VERSION 5.8 ;
BUSBITCHARS "[]" ;
DIVIDERCHAR "/" ;
UNITS
    DATABASE MICRONS 1000 ;
END UNITS

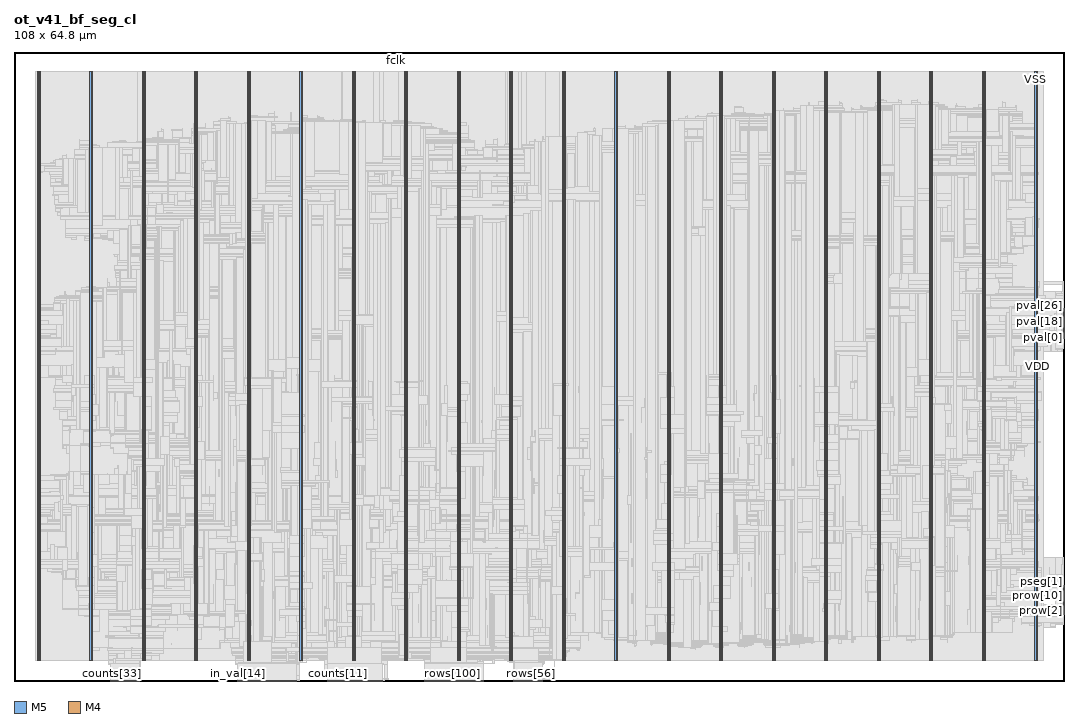
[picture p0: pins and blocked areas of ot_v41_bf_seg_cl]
MACRO ot_v41_bf_seg_cl
  FOREIGN ot_v41_bf_seg_cl 0 0 ;
  CLASS BLOCK ;
  SIZE 108 BY 64.8 ;
  PIN counts[0]
    DIRECTION INPUT ;
    USE SIGNAL ;
    PORT
      LAYER M5 ;
        RECT  32.208 0 32.232 0.084 ;
    END
  END counts[0]
  PIN counts[10]
    DIRECTION INPUT ;
    USE SIGNAL ;
    PORT
      LAYER M5 ;
        RECT  33.168 0 33.192 0.084 ;
    END
  END counts[10]
  PIN counts[11]
    DIRECTION INPUT ;
    USE SIGNAL ;
    PORT
      LAYER M5 ;
        RECT  33.264 0 33.288 0.084 ;
    END
  END counts[11]
  PIN counts[12]
    DIRECTION INPUT ;
    USE SIGNAL ;
    PORT
      LAYER M5 ;
        RECT  33.36 0 33.384 0.084 ;
    END
  END counts[12]
  PIN counts[13]
    DIRECTION INPUT ;
    USE SIGNAL ;
    PORT
      LAYER M5 ;
        RECT  33.456 0 33.48 0.084 ;
    END
  END counts[13]
  PIN counts[14]
    DIRECTION INPUT ;
    USE SIGNAL ;
    PORT
      LAYER M5 ;
        RECT  33.552 0 33.576 0.084 ;
    END
  END counts[14]
  PIN counts[15]
    DIRECTION INPUT ;
    USE SIGNAL ;
    PORT
      LAYER M5 ;
        RECT  33.648 0 33.672 0.084 ;
    END
  END counts[15]
  PIN counts[16]
    DIRECTION INPUT ;
    USE SIGNAL ;
    PORT
      LAYER M5 ;
        RECT  33.744 0 33.768 0.084 ;
    END
  END counts[16]
  PIN counts[17]
    DIRECTION INPUT ;
    USE SIGNAL ;
    PORT
      LAYER M5 ;
        RECT  33.84 0 33.864 0.084 ;
    END
  END counts[17]
  PIN counts[18]
    DIRECTION INPUT ;
    USE SIGNAL ;
    PORT
      LAYER M5 ;
        RECT  33.936 0 33.96 0.084 ;
    END
  END counts[18]
  PIN counts[19]
    DIRECTION INPUT ;
    USE SIGNAL ;
    PORT
      LAYER M5 ;
        RECT  34.032 0 34.056 0.084 ;
    END
  END counts[19]
  PIN counts[1]
    DIRECTION INPUT ;
    USE SIGNAL ;
    PORT
      LAYER M5 ;
        RECT  32.304 0 32.328 0.084 ;
    END
  END counts[1]
  PIN counts[20]
    DIRECTION INPUT ;
    USE SIGNAL ;
    PORT
      LAYER M5 ;
        RECT  34.128 0 34.152 0.084 ;
    END
  END counts[20]
  PIN counts[21]
    DIRECTION INPUT ;
    USE SIGNAL ;
    PORT
      LAYER M5 ;
        RECT  34.224 0 34.248 0.084 ;
    END
  END counts[21]
  PIN counts[22]
    DIRECTION INPUT ;
    USE SIGNAL ;
    PORT
      LAYER M5 ;
        RECT  34.32 0 34.344 0.084 ;
    END
  END counts[22]
  PIN counts[23]
    DIRECTION INPUT ;
    USE SIGNAL ;
    PORT
      LAYER M5 ;
        RECT  34.416 0 34.44 0.084 ;
    END
  END counts[23]
  PIN counts[24]
    DIRECTION INPUT ;
    USE SIGNAL ;
    PORT
      LAYER M5 ;
        RECT  34.512 0 34.536 0.084 ;
    END
  END counts[24]
  PIN counts[25]
    DIRECTION INPUT ;
    USE SIGNAL ;
    PORT
      LAYER M5 ;
        RECT  34.608 0 34.632 0.084 ;
    END
  END counts[25]
  PIN counts[26]
    DIRECTION INPUT ;
    USE SIGNAL ;
    PORT
      LAYER M5 ;
        RECT  34.704 0 34.728 0.084 ;
    END
  END counts[26]
  PIN counts[27]
    DIRECTION INPUT ;
    USE SIGNAL ;
    PORT
      LAYER M5 ;
        RECT  34.8 0 34.824 0.084 ;
    END
  END counts[27]
  PIN counts[28]
    DIRECTION INPUT ;
    USE SIGNAL ;
    PORT
      LAYER M5 ;
        RECT  34.896 0 34.92 0.084 ;
    END
  END counts[28]
  PIN counts[29]
    DIRECTION INPUT ;
    USE SIGNAL ;
    PORT
      LAYER M5 ;
        RECT  34.992 0 35.016 0.084 ;
    END
  END counts[29]
  PIN counts[2]
    DIRECTION INPUT ;
    USE SIGNAL ;
    PORT
      LAYER M5 ;
        RECT  32.4 0 32.424 0.084 ;
    END
  END counts[2]
  PIN counts[30]
    DIRECTION INPUT ;
    USE SIGNAL ;
    PORT
      LAYER M5 ;
        RECT  35.088 0 35.112 0.084 ;
    END
  END counts[30]
  PIN counts[31]
    DIRECTION INPUT ;
    USE SIGNAL ;
    PORT
      LAYER M5 ;
        RECT  35.184 0 35.208 0.084 ;
    END
  END counts[31]
  PIN counts[32]
    DIRECTION INPUT ;
    USE SIGNAL ;
    PORT
      LAYER M5 ;
        RECT  9.936 0 9.96 0.084 ;
    END
  END counts[32]
  PIN counts[33]
    DIRECTION INPUT ;
    USE SIGNAL ;
    PORT
      LAYER M5 ;
        RECT  10.032 0 10.056 0.084 ;
    END
  END counts[33]
  PIN counts[34]
    DIRECTION INPUT ;
    USE SIGNAL ;
    PORT
      LAYER M5 ;
        RECT  10.128 0 10.152 0.084 ;
    END
  END counts[34]
  PIN counts[35]
    DIRECTION INPUT ;
    USE SIGNAL ;
    PORT
      LAYER M5 ;
        RECT  10.224 0 10.248 0.084 ;
    END
  END counts[35]
  PIN counts[36]
    DIRECTION INPUT ;
    USE SIGNAL ;
    PORT
      LAYER M5 ;
        RECT  10.32 0 10.344 0.084 ;
    END
  END counts[36]
  PIN counts[37]
    DIRECTION INPUT ;
    USE SIGNAL ;
    PORT
      LAYER M5 ;
        RECT  10.416 0 10.44 0.084 ;
    END
  END counts[37]
  PIN counts[38]
    DIRECTION INPUT ;
    USE SIGNAL ;
    PORT
      LAYER M5 ;
        RECT  10.512 0 10.536 0.084 ;
    END
  END counts[38]
  PIN counts[39]
    DIRECTION INPUT ;
    USE SIGNAL ;
    PORT
      LAYER M5 ;
        RECT  10.608 0 10.632 0.084 ;
    END
  END counts[39]
  PIN counts[3]
    DIRECTION INPUT ;
    USE SIGNAL ;
    PORT
      LAYER M5 ;
        RECT  32.496 0 32.52 0.084 ;
    END
  END counts[3]
  PIN counts[4]
    DIRECTION INPUT ;
    USE SIGNAL ;
    PORT
      LAYER M5 ;
        RECT  32.592 0 32.616 0.084 ;
    END
  END counts[4]
  PIN counts[5]
    DIRECTION INPUT ;
    USE SIGNAL ;
    PORT
      LAYER M5 ;
        RECT  32.688 0 32.712 0.084 ;
    END
  END counts[5]
  PIN counts[6]
    DIRECTION INPUT ;
    USE SIGNAL ;
    PORT
      LAYER M5 ;
        RECT  32.784 0 32.808 0.084 ;
    END
  END counts[6]
  PIN counts[7]
    DIRECTION INPUT ;
    USE SIGNAL ;
    PORT
      LAYER M5 ;
        RECT  32.88 0 32.904 0.084 ;
    END
  END counts[7]
  PIN counts[8]
    DIRECTION INPUT ;
    USE SIGNAL ;
    PORT
      LAYER M5 ;
        RECT  32.976 0 33 0.084 ;
    END
  END counts[8]
  PIN counts[9]
    DIRECTION INPUT ;
    USE SIGNAL ;
    PORT
      LAYER M5 ;
        RECT  33.072 0 33.096 0.084 ;
    END
  END counts[9]
  PIN fault
    DIRECTION OUTPUT ;
    USE SIGNAL ;
    PORT
      LAYER M4 ;
        RECT  107.916 6.864 108 6.888 ;
    END
  END fault
  PIN fclk
    DIRECTION INPUT ;
    USE SIGNAL ;
    PORT
      LAYER M5 ;
        RECT  39.312 64.716 39.336 64.8 ;
    END
  END fclk
  PIN in_err
    DIRECTION INPUT ;
    USE SIGNAL ;
    PORT
      LAYER M5 ;
        RECT  10.704 0 10.728 0.084 ;
    END
  END in_err
  PIN in_final
    DIRECTION INPUT ;
    USE SIGNAL ;
    PORT
      LAYER M5 ;
        RECT  10.8 0 10.824 0.084 ;
    END
  END in_final
  PIN in_pos[0]
    DIRECTION INPUT ;
    USE SIGNAL ;
    PORT
      LAYER M5 ;
        RECT  10.896 0 10.92 0.084 ;
    END
  END in_pos[0]
  PIN in_pos[1]
    DIRECTION INPUT ;
    USE SIGNAL ;
    PORT
      LAYER M5 ;
        RECT  10.992 0 11.016 0.084 ;
    END
  END in_pos[1]
  PIN in_pos[2]
    DIRECTION INPUT ;
    USE SIGNAL ;
    PORT
      LAYER M5 ;
        RECT  11.088 0 11.112 0.084 ;
    END
  END in_pos[2]
  PIN in_tree[0]
    DIRECTION INPUT ;
    USE SIGNAL ;
    PORT
      LAYER M5 ;
        RECT  11.184 0 11.208 0.084 ;
    END
  END in_tree[0]
  PIN in_tree[1]
    DIRECTION INPUT ;
    USE SIGNAL ;
    PORT
      LAYER M5 ;
        RECT  11.28 0 11.304 0.084 ;
    END
  END in_tree[1]
  PIN in_tree[2]
    DIRECTION INPUT ;
    USE SIGNAL ;
    PORT
      LAYER M5 ;
        RECT  11.376 0 11.4 0.084 ;
    END
  END in_tree[2]
  PIN in_tree[3]
    DIRECTION INPUT ;
    USE SIGNAL ;
    PORT
      LAYER M5 ;
        RECT  11.472 0 11.496 0.084 ;
    END
  END in_tree[3]
  PIN in_v
    DIRECTION INPUT ;
    USE SIGNAL ;
    PORT
      LAYER M5 ;
        RECT  11.568 0 11.592 0.084 ;
    END
  END in_v
  PIN in_val[0]
    DIRECTION INPUT ;
    USE SIGNAL ;
    PORT
      LAYER M5 ;
        RECT  11.664 0 11.688 0.084 ;
    END
  END in_val[0]
  PIN in_val[10]
    DIRECTION INPUT ;
    USE SIGNAL ;
    PORT
      LAYER M5 ;
        RECT  12.624 0 12.648 0.084 ;
    END
  END in_val[10]
  PIN in_val[11]
    DIRECTION INPUT ;
    USE SIGNAL ;
    PORT
      LAYER M5 ;
        RECT  12.72 0 12.744 0.084 ;
    END
  END in_val[11]
  PIN in_val[12]
    DIRECTION INPUT ;
    USE SIGNAL ;
    PORT
      LAYER M5 ;
        RECT  12.816 0 12.84 0.084 ;
    END
  END in_val[12]
  PIN in_val[13]
    DIRECTION INPUT ;
    USE SIGNAL ;
    PORT
      LAYER M5 ;
        RECT  12.912 0 12.936 0.084 ;
    END
  END in_val[13]
  PIN in_val[14]
    DIRECTION INPUT ;
    USE SIGNAL ;
    PORT
      LAYER M5 ;
        RECT  22.992 0 23.016 0.084 ;
    END
  END in_val[14]
  PIN in_val[15]
    DIRECTION INPUT ;
    USE SIGNAL ;
    PORT
      LAYER M5 ;
        RECT  23.088 0 23.112 0.084 ;
    END
  END in_val[15]
  PIN in_val[16]
    DIRECTION INPUT ;
    USE SIGNAL ;
    PORT
      LAYER M5 ;
        RECT  23.184 0 23.208 0.084 ;
    END
  END in_val[16]
  PIN in_val[17]
    DIRECTION INPUT ;
    USE SIGNAL ;
    PORT
      LAYER M5 ;
        RECT  23.28 0 23.304 0.084 ;
    END
  END in_val[17]
  PIN in_val[18]
    DIRECTION INPUT ;
    USE SIGNAL ;
    PORT
      LAYER M5 ;
        RECT  23.376 0 23.4 0.084 ;
    END
  END in_val[18]
  PIN in_val[19]
    DIRECTION INPUT ;
    USE SIGNAL ;
    PORT
      LAYER M5 ;
        RECT  23.472 0 23.496 0.084 ;
    END
  END in_val[19]
  PIN in_val[1]
    DIRECTION INPUT ;
    USE SIGNAL ;
    PORT
      LAYER M5 ;
        RECT  11.76 0 11.784 0.084 ;
    END
  END in_val[1]
  PIN in_val[20]
    DIRECTION INPUT ;
    USE SIGNAL ;
    PORT
      LAYER M5 ;
        RECT  23.568 0 23.592 0.084 ;
    END
  END in_val[20]
  PIN in_val[21]
    DIRECTION INPUT ;
    USE SIGNAL ;
    PORT
      LAYER M5 ;
        RECT  23.664 0 23.688 0.084 ;
    END
  END in_val[21]
  PIN in_val[22]
    DIRECTION INPUT ;
    USE SIGNAL ;
    PORT
      LAYER M5 ;
        RECT  23.76 0 23.784 0.084 ;
    END
  END in_val[22]
  PIN in_val[23]
    DIRECTION INPUT ;
    USE SIGNAL ;
    PORT
      LAYER M5 ;
        RECT  23.856 0 23.88 0.084 ;
    END
  END in_val[23]
  PIN in_val[24]
    DIRECTION INPUT ;
    USE SIGNAL ;
    PORT
      LAYER M5 ;
        RECT  23.952 0 23.976 0.084 ;
    END
  END in_val[24]
  PIN in_val[25]
    DIRECTION INPUT ;
    USE SIGNAL ;
    PORT
      LAYER M5 ;
        RECT  24.048 0 24.072 0.084 ;
    END
  END in_val[25]
  PIN in_val[26]
    DIRECTION INPUT ;
    USE SIGNAL ;
    PORT
      LAYER M5 ;
        RECT  24.144 0 24.168 0.084 ;
    END
  END in_val[26]
  PIN in_val[27]
    DIRECTION INPUT ;
    USE SIGNAL ;
    PORT
      LAYER M5 ;
        RECT  24.24 0 24.264 0.084 ;
    END
  END in_val[27]
  PIN in_val[28]
    DIRECTION INPUT ;
    USE SIGNAL ;
    PORT
      LAYER M5 ;
        RECT  24.336 0 24.36 0.084 ;
    END
  END in_val[28]
  PIN in_val[29]
    DIRECTION INPUT ;
    USE SIGNAL ;
    PORT
      LAYER M5 ;
        RECT  24.432 0 24.456 0.084 ;
    END
  END in_val[29]
  PIN in_val[2]
    DIRECTION INPUT ;
    USE SIGNAL ;
    PORT
      LAYER M5 ;
        RECT  11.856 0 11.88 0.084 ;
    END
  END in_val[2]
  PIN in_val[30]
    DIRECTION INPUT ;
    USE SIGNAL ;
    PORT
      LAYER M5 ;
        RECT  24.528 0 24.552 0.084 ;
    END
  END in_val[30]
  PIN in_val[31]
    DIRECTION INPUT ;
    USE SIGNAL ;
    PORT
      LAYER M5 ;
        RECT  24.624 0 24.648 0.084 ;
    END
  END in_val[31]
  PIN in_val[3]
    DIRECTION INPUT ;
    USE SIGNAL ;
    PORT
      LAYER M5 ;
        RECT  11.952 0 11.976 0.084 ;
    END
  END in_val[3]
  PIN in_val[4]
    DIRECTION INPUT ;
    USE SIGNAL ;
    PORT
      LAYER M5 ;
        RECT  12.048 0 12.072 0.084 ;
    END
  END in_val[4]
  PIN in_val[5]
    DIRECTION INPUT ;
    USE SIGNAL ;
    PORT
      LAYER M5 ;
        RECT  12.144 0 12.168 0.084 ;
    END
  END in_val[5]
  PIN in_val[6]
    DIRECTION INPUT ;
    USE SIGNAL ;
    PORT
      LAYER M5 ;
        RECT  12.24 0 12.264 0.084 ;
    END
  END in_val[6]
  PIN in_val[7]
    DIRECTION INPUT ;
    USE SIGNAL ;
    PORT
      LAYER M5 ;
        RECT  12.336 0 12.36 0.084 ;
    END
  END in_val[7]
  PIN in_val[8]
    DIRECTION INPUT ;
    USE SIGNAL ;
    PORT
      LAYER M5 ;
        RECT  12.432 0 12.456 0.084 ;
    END
  END in_val[8]
  PIN in_val[9]
    DIRECTION INPUT ;
    USE SIGNAL ;
    PORT
      LAYER M5 ;
        RECT  12.528 0 12.552 0.084 ;
    END
  END in_val[9]
  PIN indices[0]
    DIRECTION INPUT ;
    USE SIGNAL ;
    PORT
      LAYER M5 ;
        RECT  24.72 0 24.744 0.084 ;
    END
  END indices[0]
  PIN indices[10]
    DIRECTION INPUT ;
    USE SIGNAL ;
    PORT
      LAYER M5 ;
        RECT  25.68 0 25.704 0.084 ;
    END
  END indices[10]
  PIN indices[11]
    DIRECTION INPUT ;
    USE SIGNAL ;
    PORT
      LAYER M5 ;
        RECT  25.776 0 25.8 0.084 ;
    END
  END indices[11]
  PIN indices[12]
    DIRECTION INPUT ;
    USE SIGNAL ;
    PORT
      LAYER M5 ;
        RECT  25.872 0 25.896 0.084 ;
    END
  END indices[12]
  PIN indices[13]
    DIRECTION INPUT ;
    USE SIGNAL ;
    PORT
      LAYER M5 ;
        RECT  25.968 0 25.992 0.084 ;
    END
  END indices[13]
  PIN indices[14]
    DIRECTION INPUT ;
    USE SIGNAL ;
    PORT
      LAYER M5 ;
        RECT  26.064 0 26.088 0.084 ;
    END
  END indices[14]
  PIN indices[15]
    DIRECTION INPUT ;
    USE SIGNAL ;
    PORT
      LAYER M5 ;
        RECT  26.16 0 26.184 0.084 ;
    END
  END indices[15]
  PIN indices[16]
    DIRECTION INPUT ;
    USE SIGNAL ;
    PORT
      LAYER M5 ;
        RECT  26.256 0 26.28 0.084 ;
    END
  END indices[16]
  PIN indices[17]
    DIRECTION INPUT ;
    USE SIGNAL ;
    PORT
      LAYER M5 ;
        RECT  26.352 0 26.376 0.084 ;
    END
  END indices[17]
  PIN indices[18]
    DIRECTION INPUT ;
    USE SIGNAL ;
    PORT
      LAYER M5 ;
        RECT  26.448 0 26.472 0.084 ;
    END
  END indices[18]
  PIN indices[19]
    DIRECTION INPUT ;
    USE SIGNAL ;
    PORT
      LAYER M5 ;
        RECT  26.544 0 26.568 0.084 ;
    END
  END indices[19]
  PIN indices[1]
    DIRECTION INPUT ;
    USE SIGNAL ;
    PORT
      LAYER M5 ;
        RECT  24.816 0 24.84 0.084 ;
    END
  END indices[1]
  PIN indices[20]
    DIRECTION INPUT ;
    USE SIGNAL ;
    PORT
      LAYER M5 ;
        RECT  26.64 0 26.664 0.084 ;
    END
  END indices[20]
  PIN indices[21]
    DIRECTION INPUT ;
    USE SIGNAL ;
    PORT
      LAYER M5 ;
        RECT  26.736 0 26.76 0.084 ;
    END
  END indices[21]
  PIN indices[22]
    DIRECTION INPUT ;
    USE SIGNAL ;
    PORT
      LAYER M5 ;
        RECT  26.832 0 26.856 0.084 ;
    END
  END indices[22]
  PIN indices[23]
    DIRECTION INPUT ;
    USE SIGNAL ;
    PORT
      LAYER M5 ;
        RECT  26.928 0 26.952 0.084 ;
    END
  END indices[23]
  PIN indices[24]
    DIRECTION INPUT ;
    USE SIGNAL ;
    PORT
      LAYER M5 ;
        RECT  27.024 0 27.048 0.084 ;
    END
  END indices[24]
  PIN indices[25]
    DIRECTION INPUT ;
    USE SIGNAL ;
    PORT
      LAYER M5 ;
        RECT  27.12 0 27.144 0.084 ;
    END
  END indices[25]
  PIN indices[26]
    DIRECTION INPUT ;
    USE SIGNAL ;
    PORT
      LAYER M5 ;
        RECT  27.216 0 27.24 0.084 ;
    END
  END indices[26]
  PIN indices[27]
    DIRECTION INPUT ;
    USE SIGNAL ;
    PORT
      LAYER M5 ;
        RECT  27.312 0 27.336 0.084 ;
    END
  END indices[27]
  PIN indices[28]
    DIRECTION INPUT ;
    USE SIGNAL ;
    PORT
      LAYER M5 ;
        RECT  27.408 0 27.432 0.084 ;
    END
  END indices[28]
  PIN indices[29]
    DIRECTION INPUT ;
    USE SIGNAL ;
    PORT
      LAYER M5 ;
        RECT  27.504 0 27.528 0.084 ;
    END
  END indices[29]
  PIN indices[2]
    DIRECTION INPUT ;
    USE SIGNAL ;
    PORT
      LAYER M5 ;
        RECT  24.912 0 24.936 0.084 ;
    END
  END indices[2]
  PIN indices[30]
    DIRECTION INPUT ;
    USE SIGNAL ;
    PORT
      LAYER M5 ;
        RECT  27.6 0 27.624 0.084 ;
    END
  END indices[30]
  PIN indices[31]
    DIRECTION INPUT ;
    USE SIGNAL ;
    PORT
      LAYER M5 ;
        RECT  27.696 0 27.72 0.084 ;
    END
  END indices[31]
  PIN indices[32]
    DIRECTION INPUT ;
    USE SIGNAL ;
    PORT
      LAYER M5 ;
        RECT  27.792 0 27.816 0.084 ;
    END
  END indices[32]
  PIN indices[33]
    DIRECTION INPUT ;
    USE SIGNAL ;
    PORT
      LAYER M5 ;
        RECT  27.888 0 27.912 0.084 ;
    END
  END indices[33]
  PIN indices[34]
    DIRECTION INPUT ;
    USE SIGNAL ;
    PORT
      LAYER M5 ;
        RECT  27.984 0 28.008 0.084 ;
    END
  END indices[34]
  PIN indices[35]
    DIRECTION INPUT ;
    USE SIGNAL ;
    PORT
      LAYER M5 ;
        RECT  28.08 0 28.104 0.084 ;
    END
  END indices[35]
  PIN indices[36]
    DIRECTION INPUT ;
    USE SIGNAL ;
    PORT
      LAYER M5 ;
        RECT  28.176 0 28.2 0.084 ;
    END
  END indices[36]
  PIN indices[37]
    DIRECTION INPUT ;
    USE SIGNAL ;
    PORT
      LAYER M5 ;
        RECT  28.272 0 28.296 0.084 ;
    END
  END indices[37]
  PIN indices[38]
    DIRECTION INPUT ;
    USE SIGNAL ;
    PORT
      LAYER M5 ;
        RECT  28.368 0 28.392 0.084 ;
    END
  END indices[38]
  PIN indices[39]
    DIRECTION INPUT ;
    USE SIGNAL ;
    PORT
      LAYER M5 ;
        RECT  28.464 0 28.488 0.084 ;
    END
  END indices[39]
  PIN indices[3]
    DIRECTION INPUT ;
    USE SIGNAL ;
    PORT
      LAYER M5 ;
        RECT  25.008 0 25.032 0.084 ;
    END
  END indices[3]
  PIN indices[4]
    DIRECTION INPUT ;
    USE SIGNAL ;
    PORT
      LAYER M5 ;
        RECT  25.104 0 25.128 0.084 ;
    END
  END indices[4]
  PIN indices[5]
    DIRECTION INPUT ;
    USE SIGNAL ;
    PORT
      LAYER M5 ;
        RECT  25.2 0 25.224 0.084 ;
    END
  END indices[5]
  PIN indices[6]
    DIRECTION INPUT ;
    USE SIGNAL ;
    PORT
      LAYER M5 ;
        RECT  25.296 0 25.32 0.084 ;
    END
  END indices[6]
  PIN indices[7]
    DIRECTION INPUT ;
    USE SIGNAL ;
    PORT
      LAYER M5 ;
        RECT  25.392 0 25.416 0.084 ;
    END
  END indices[7]
  PIN indices[8]
    DIRECTION INPUT ;
    USE SIGNAL ;
    PORT
      LAYER M5 ;
        RECT  25.488 0 25.512 0.084 ;
    END
  END indices[8]
  PIN indices[9]
    DIRECTION INPUT ;
    USE SIGNAL ;
    PORT
      LAYER M5 ;
        RECT  25.584 0 25.608 0.084 ;
    END
  END indices[9]
  PIN perr
    DIRECTION OUTPUT ;
    USE SIGNAL ;
    PORT
      LAYER M4 ;
        RECT  107.916 6.96 108 6.984 ;
    END
  END perr
  PIN pnseg[0]
    DIRECTION OUTPUT ;
    USE SIGNAL ;
    PORT
      LAYER M4 ;
        RECT  107.916 7.056 108 7.08 ;
    END
  END pnseg[0]
  PIN pnseg[1]
    DIRECTION OUTPUT ;
    USE SIGNAL ;
    PORT
      LAYER M4 ;
        RECT  107.916 7.152 108 7.176 ;
    END
  END pnseg[1]
  PIN pnseg[2]
    DIRECTION OUTPUT ;
    USE SIGNAL ;
    PORT
      LAYER M4 ;
        RECT  107.916 7.248 108 7.272 ;
    END
  END pnseg[2]
  PIN pnseg[3]
    DIRECTION OUTPUT ;
    USE SIGNAL ;
    PORT
      LAYER M4 ;
        RECT  107.916 7.344 108 7.368 ;
    END
  END pnseg[3]
  PIN pnseg[4]
    DIRECTION OUTPUT ;
    USE SIGNAL ;
    PORT
      LAYER M4 ;
        RECT  107.916 7.44 108 7.464 ;
    END
  END pnseg[4]
  PIN ppos[0]
    DIRECTION OUTPUT ;
    USE SIGNAL ;
    PORT
      LAYER M4 ;
        RECT  107.916 7.536 108 7.56 ;
    END
  END ppos[0]
  PIN ppos[1]
    DIRECTION OUTPUT ;
    USE SIGNAL ;
    PORT
      LAYER M4 ;
        RECT  107.916 7.632 108 7.656 ;
    END
  END ppos[1]
  PIN ppos[2]
    DIRECTION OUTPUT ;
    USE SIGNAL ;
    PORT
      LAYER M4 ;
        RECT  107.916 7.728 108 7.752 ;
    END
  END ppos[2]
  PIN prow[0]
    DIRECTION OUTPUT ;
    USE SIGNAL ;
    PORT
      LAYER M4 ;
        RECT  107.916 7.824 108 7.848 ;
    END
  END prow[0]
  PIN prow[10]
    DIRECTION OUTPUT ;
    USE SIGNAL ;
    PORT
      LAYER M4 ;
        RECT  107.916 8.784 108 8.808 ;
    END
  END prow[10]
  PIN prow[11]
    DIRECTION OUTPUT ;
    USE SIGNAL ;
    PORT
      LAYER M4 ;
        RECT  107.916 8.88 108 8.904 ;
    END
  END prow[11]
  PIN prow[12]
    DIRECTION OUTPUT ;
    USE SIGNAL ;
    PORT
      LAYER M4 ;
        RECT  107.916 8.976 108 9 ;
    END
  END prow[12]
  PIN prow[13]
    DIRECTION OUTPUT ;
    USE SIGNAL ;
    PORT
      LAYER M4 ;
        RECT  107.916 9.072 108 9.096 ;
    END
  END prow[13]
  PIN prow[14]
    DIRECTION OUTPUT ;
    USE SIGNAL ;
    PORT
      LAYER M4 ;
        RECT  107.916 9.168 108 9.192 ;
    END
  END prow[14]
  PIN prow[15]
    DIRECTION OUTPUT ;
    USE SIGNAL ;
    PORT
      LAYER M4 ;
        RECT  107.916 9.264 108 9.288 ;
    END
  END prow[15]
  PIN prow[1]
    DIRECTION OUTPUT ;
    USE SIGNAL ;
    PORT
      LAYER M4 ;
        RECT  107.916 7.92 108 7.944 ;
    END
  END prow[1]
  PIN prow[2]
    DIRECTION OUTPUT ;
    USE SIGNAL ;
    PORT
      LAYER M4 ;
        RECT  107.916 8.016 108 8.04 ;
    END
  END prow[2]
  PIN prow[3]
    DIRECTION OUTPUT ;
    USE SIGNAL ;
    PORT
      LAYER M4 ;
        RECT  107.916 8.112 108 8.136 ;
    END
  END prow[3]
  PIN prow[4]
    DIRECTION OUTPUT ;
    USE SIGNAL ;
    PORT
      LAYER M4 ;
        RECT  107.916 8.208 108 8.232 ;
    END
  END prow[4]
  PIN prow[5]
    DIRECTION OUTPUT ;
    USE SIGNAL ;
    PORT
      LAYER M4 ;
        RECT  107.916 8.304 108 8.328 ;
    END
  END prow[5]
  PIN prow[6]
    DIRECTION OUTPUT ;
    USE SIGNAL ;
    PORT
      LAYER M4 ;
        RECT  107.916 8.4 108 8.424 ;
    END
  END prow[6]
  PIN prow[7]
    DIRECTION OUTPUT ;
    USE SIGNAL ;
    PORT
      LAYER M4 ;
        RECT  107.916 8.496 108 8.52 ;
    END
  END prow[7]
  PIN prow[8]
    DIRECTION OUTPUT ;
    USE SIGNAL ;
    PORT
      LAYER M4 ;
        RECT  107.916 8.592 108 8.616 ;
    END
  END prow[8]
  PIN prow[9]
    DIRECTION OUTPUT ;
    USE SIGNAL ;
    PORT
      LAYER M4 ;
        RECT  107.916 8.688 108 8.712 ;
    END
  END prow[9]
  PIN pseg[0]
    DIRECTION OUTPUT ;
    USE SIGNAL ;
    PORT
      LAYER M4 ;
        RECT  107.916 9.36 108 9.384 ;
    END
  END pseg[0]
  PIN pseg[1]
    DIRECTION OUTPUT ;
    USE SIGNAL ;
    PORT
      LAYER M4 ;
        RECT  107.916 9.456 108 9.48 ;
    END
  END pseg[1]
  PIN pseg[2]
    DIRECTION OUTPUT ;
    USE SIGNAL ;
    PORT
      LAYER M4 ;
        RECT  107.916 9.552 108 9.576 ;
    END
  END pseg[2]
  PIN pseg[3]
    DIRECTION OUTPUT ;
    USE SIGNAL ;
    PORT
      LAYER M4 ;
        RECT  107.916 9.648 108 9.672 ;
    END
  END pseg[3]
  PIN pseg[4]
    DIRECTION OUTPUT ;
    USE SIGNAL ;
    PORT
      LAYER M4 ;
        RECT  107.916 9.744 108 9.768 ;
    END
  END pseg[4]
  PIN pv
    DIRECTION OUTPUT ;
    USE SIGNAL ;
    PORT
      LAYER M4 ;
        RECT  107.916 9.84 108 9.864 ;
    END
  END pv
  PIN pval[0]
    DIRECTION OUTPUT ;
    USE SIGNAL ;
    PORT
      LAYER M4 ;
        RECT  107.916 35.28 108 35.304 ;
    END
  END pval[0]
  PIN pval[10]
    DIRECTION OUTPUT ;
    USE SIGNAL ;
    PORT
      LAYER M4 ;
        RECT  107.916 36.24 108 36.264 ;
    END
  END pval[10]
  PIN pval[11]
    DIRECTION OUTPUT ;
    USE SIGNAL ;
    PORT
      LAYER M4 ;
        RECT  107.916 36.336 108 36.36 ;
    END
  END pval[11]
  PIN pval[12]
    DIRECTION OUTPUT ;
    USE SIGNAL ;
    PORT
      LAYER M4 ;
        RECT  107.916 36.432 108 36.456 ;
    END
  END pval[12]
  PIN pval[13]
    DIRECTION OUTPUT ;
    USE SIGNAL ;
    PORT
      LAYER M4 ;
        RECT  107.916 36.528 108 36.552 ;
    END
  END pval[13]
  PIN pval[14]
    DIRECTION OUTPUT ;
    USE SIGNAL ;
    PORT
      LAYER M4 ;
        RECT  107.916 36.624 108 36.648 ;
    END
  END pval[14]
  PIN pval[15]
    DIRECTION OUTPUT ;
    USE SIGNAL ;
    PORT
      LAYER M4 ;
        RECT  107.916 36.72 108 36.744 ;
    END
  END pval[15]
  PIN pval[16]
    DIRECTION OUTPUT ;
    USE SIGNAL ;
    PORT
      LAYER M4 ;
        RECT  107.916 36.816 108 36.84 ;
    END
  END pval[16]
  PIN pval[17]
    DIRECTION OUTPUT ;
    USE SIGNAL ;
    PORT
      LAYER M4 ;
        RECT  107.916 36.912 108 36.936 ;
    END
  END pval[17]
  PIN pval[18]
    DIRECTION OUTPUT ;
    USE SIGNAL ;
    PORT
      LAYER M4 ;
        RECT  107.916 37.008 108 37.032 ;
    END
  END pval[18]
  PIN pval[19]
    DIRECTION OUTPUT ;
    USE SIGNAL ;
    PORT
      LAYER M4 ;
        RECT  107.916 37.104 108 37.128 ;
    END
  END pval[19]
  PIN pval[1]
    DIRECTION OUTPUT ;
    USE SIGNAL ;
    PORT
      LAYER M4 ;
        RECT  107.916 35.376 108 35.4 ;
    END
  END pval[1]
  PIN pval[20]
    DIRECTION OUTPUT ;
    USE SIGNAL ;
    PORT
      LAYER M4 ;
        RECT  107.916 37.2 108 37.224 ;
    END
  END pval[20]
  PIN pval[21]
    DIRECTION OUTPUT ;
    USE SIGNAL ;
    PORT
      LAYER M4 ;
        RECT  107.916 37.296 108 37.32 ;
    END
  END pval[21]
  PIN pval[22]
    DIRECTION OUTPUT ;
    USE SIGNAL ;
    PORT
      LAYER M4 ;
        RECT  107.916 37.392 108 37.416 ;
    END
  END pval[22]
  PIN pval[23]
    DIRECTION OUTPUT ;
    USE SIGNAL ;
    PORT
      LAYER M4 ;
        RECT  107.916 37.488 108 37.512 ;
    END
  END pval[23]
  PIN pval[24]
    DIRECTION OUTPUT ;
    USE SIGNAL ;
    PORT
      LAYER M4 ;
        RECT  107.916 37.584 108 37.608 ;
    END
  END pval[24]
  PIN pval[25]
    DIRECTION OUTPUT ;
    USE SIGNAL ;
    PORT
      LAYER M4 ;
        RECT  107.916 37.68 108 37.704 ;
    END
  END pval[25]
  PIN pval[26]
    DIRECTION OUTPUT ;
    USE SIGNAL ;
    PORT
      LAYER M4 ;
        RECT  107.916 37.776 108 37.8 ;
    END
  END pval[26]
  PIN pval[27]
    DIRECTION OUTPUT ;
    USE SIGNAL ;
    PORT
      LAYER M4 ;
        RECT  107.916 37.872 108 37.896 ;
    END
  END pval[27]
  PIN pval[28]
    DIRECTION OUTPUT ;
    USE SIGNAL ;
    PORT
      LAYER M4 ;
        RECT  107.916 37.968 108 37.992 ;
    END
  END pval[28]
  PIN pval[29]
    DIRECTION OUTPUT ;
    USE SIGNAL ;
    PORT
      LAYER M4 ;
        RECT  107.916 38.064 108 38.088 ;
    END
  END pval[29]
  PIN pval[2]
    DIRECTION OUTPUT ;
    USE SIGNAL ;
    PORT
      LAYER M4 ;
        RECT  107.916 35.472 108 35.496 ;
    END
  END pval[2]
  PIN pval[30]
    DIRECTION OUTPUT ;
    USE SIGNAL ;
    PORT
      LAYER M4 ;
        RECT  107.916 38.16 108 38.184 ;
    END
  END pval[30]
  PIN pval[31]
    DIRECTION OUTPUT ;
    USE SIGNAL ;
    PORT
      LAYER M4 ;
        RECT  107.916 38.256 108 38.28 ;
    END
  END pval[31]
  PIN pval[3]
    DIRECTION OUTPUT ;
    USE SIGNAL ;
    PORT
      LAYER M4 ;
        RECT  107.916 35.568 108 35.592 ;
    END
  END pval[3]
  PIN pval[4]
    DIRECTION OUTPUT ;
    USE SIGNAL ;
    PORT
      LAYER M4 ;
        RECT  107.916 35.664 108 35.688 ;
    END
  END pval[4]
  PIN pval[5]
    DIRECTION OUTPUT ;
    USE SIGNAL ;
    PORT
      LAYER M4 ;
        RECT  107.916 35.76 108 35.784 ;
    END
  END pval[5]
  PIN pval[6]
    DIRECTION OUTPUT ;
    USE SIGNAL ;
    PORT
      LAYER M4 ;
        RECT  107.916 35.856 108 35.88 ;
    END
  END pval[6]
  PIN pval[7]
    DIRECTION OUTPUT ;
    USE SIGNAL ;
    PORT
      LAYER M4 ;
        RECT  107.916 35.952 108 35.976 ;
    END
  END pval[7]
  PIN pval[8]
    DIRECTION OUTPUT ;
    USE SIGNAL ;
    PORT
      LAYER M4 ;
        RECT  107.916 36.048 108 36.072 ;
    END
  END pval[8]
  PIN pval[9]
    DIRECTION OUTPUT ;
    USE SIGNAL ;
    PORT
      LAYER M4 ;
        RECT  107.916 36.144 108 36.168 ;
    END
  END pval[9]
  PIN rows[0]
    DIRECTION INPUT ;
    USE SIGNAL ;
    PORT
      LAYER M5 ;
        RECT  28.56 0 28.584 0.084 ;
    END
  END rows[0]
  PIN rows[100]
    DIRECTION INPUT ;
    USE SIGNAL ;
    PORT
      LAYER M5 ;
        RECT  45.072 0 45.096 0.084 ;
    END
  END rows[100]
  PIN rows[101]
    DIRECTION INPUT ;
    USE SIGNAL ;
    PORT
      LAYER M5 ;
        RECT  45.168 0 45.192 0.084 ;
    END
  END rows[101]
  PIN rows[102]
    DIRECTION INPUT ;
    USE SIGNAL ;
    PORT
      LAYER M5 ;
        RECT  35.28 0 35.304 0.084 ;
    END
  END rows[102]
  PIN rows[103]
    DIRECTION INPUT ;
    USE SIGNAL ;
    PORT
      LAYER M5 ;
        RECT  35.376 0 35.4 0.084 ;
    END
  END rows[103]
  PIN rows[104]
    DIRECTION INPUT ;
    USE SIGNAL ;
    PORT
      LAYER M5 ;
        RECT  35.472 0 35.496 0.084 ;
    END
  END rows[104]
  PIN rows[105]
    DIRECTION INPUT ;
    USE SIGNAL ;
    PORT
      LAYER M5 ;
        RECT  35.568 0 35.592 0.084 ;
    END
  END rows[105]
  PIN rows[106]
    DIRECTION INPUT ;
    USE SIGNAL ;
    PORT
      LAYER M5 ;
        RECT  35.664 0 35.688 0.084 ;
    END
  END rows[106]
  PIN rows[107]
    DIRECTION INPUT ;
    USE SIGNAL ;
    PORT
      LAYER M5 ;
        RECT  35.76 0 35.784 0.084 ;
    END
  END rows[107]
  PIN rows[108]
    DIRECTION INPUT ;
    USE SIGNAL ;
    PORT
      LAYER M5 ;
        RECT  35.856 0 35.88 0.084 ;
    END
  END rows[108]
  PIN rows[109]
    DIRECTION INPUT ;
    USE SIGNAL ;
    PORT
      LAYER M5 ;
        RECT  35.952 0 35.976 0.084 ;
    END
  END rows[109]
  PIN rows[10]
    DIRECTION INPUT ;
    USE SIGNAL ;
    PORT
      LAYER M5 ;
        RECT  45.648 0 45.672 0.084 ;
    END
  END rows[10]
  PIN rows[110]
    DIRECTION INPUT ;
    USE SIGNAL ;
    PORT
      LAYER M5 ;
        RECT  36.048 0 36.072 0.084 ;
    END
  END rows[110]
  PIN rows[111]
    DIRECTION INPUT ;
    USE SIGNAL ;
    PORT
      LAYER M5 ;
        RECT  36.144 0 36.168 0.084 ;
    END
  END rows[111]
  PIN rows[112]
    DIRECTION INPUT ;
    USE SIGNAL ;
    PORT
      LAYER M5 ;
        RECT  36.24 0 36.264 0.084 ;
    END
  END rows[112]
  PIN rows[113]
    DIRECTION INPUT ;
    USE SIGNAL ;
    PORT
      LAYER M5 ;
        RECT  36.336 0 36.36 0.084 ;
    END
  END rows[113]
  PIN rows[114]
    DIRECTION INPUT ;
    USE SIGNAL ;
    PORT
      LAYER M5 ;
        RECT  36.432 0 36.456 0.084 ;
    END
  END rows[114]
  PIN rows[115]
    DIRECTION INPUT ;
    USE SIGNAL ;
    PORT
      LAYER M5 ;
        RECT  36.528 0 36.552 0.084 ;
    END
  END rows[115]
  PIN rows[116]
    DIRECTION INPUT ;
    USE SIGNAL ;
    PORT
      LAYER M5 ;
        RECT  36.624 0 36.648 0.084 ;
    END
  END rows[116]
  PIN rows[117]
    DIRECTION INPUT ;
    USE SIGNAL ;
    PORT
      LAYER M5 ;
        RECT  36.72 0 36.744 0.084 ;
    END
  END rows[117]
  PIN rows[118]
    DIRECTION INPUT ;
    USE SIGNAL ;
    PORT
      LAYER M5 ;
        RECT  36.816 0 36.84 0.084 ;
    END
  END rows[118]
  PIN rows[119]
    DIRECTION INPUT ;
    USE SIGNAL ;
    PORT
      LAYER M5 ;
        RECT  36.912 0 36.936 0.084 ;
    END
  END rows[119]
  PIN rows[11]
    DIRECTION INPUT ;
    USE SIGNAL ;
    PORT
      LAYER M5 ;
        RECT  45.744 0 45.768 0.084 ;
    END
  END rows[11]
  PIN rows[120]
    DIRECTION INPUT ;
    USE SIGNAL ;
    PORT
      LAYER M5 ;
        RECT  37.008 0 37.032 0.084 ;
    END
  END rows[120]
  PIN rows[121]
    DIRECTION INPUT ;
    USE SIGNAL ;
    PORT
      LAYER M5 ;
        RECT  37.104 0 37.128 0.084 ;
    END
  END rows[121]
  PIN rows[122]
    DIRECTION INPUT ;
    USE SIGNAL ;
    PORT
      LAYER M5 ;
        RECT  37.2 0 37.224 0.084 ;
    END
  END rows[122]
  PIN rows[123]
    DIRECTION INPUT ;
    USE SIGNAL ;
    PORT
      LAYER M5 ;
        RECT  37.296 0 37.32 0.084 ;
    END
  END rows[123]
  PIN rows[124]
    DIRECTION INPUT ;
    USE SIGNAL ;
    PORT
      LAYER M5 ;
        RECT  37.392 0 37.416 0.084 ;
    END
  END rows[124]
  PIN rows[125]
    DIRECTION INPUT ;
    USE SIGNAL ;
    PORT
      LAYER M5 ;
        RECT  37.488 0 37.512 0.084 ;
    END
  END rows[125]
  PIN rows[126]
    DIRECTION INPUT ;
    USE SIGNAL ;
    PORT
      LAYER M5 ;
        RECT  37.584 0 37.608 0.084 ;
    END
  END rows[126]
  PIN rows[127]
    DIRECTION INPUT ;
    USE SIGNAL ;
    PORT
      LAYER M5 ;
        RECT  37.68 0 37.704 0.084 ;
    END
  END rows[127]
  PIN rows[12]
    DIRECTION INPUT ;
    USE SIGNAL ;
    PORT
      LAYER M5 ;
        RECT  45.84 0 45.864 0.084 ;
    END
  END rows[12]
  PIN rows[13]
    DIRECTION INPUT ;
    USE SIGNAL ;
    PORT
      LAYER M5 ;
        RECT  45.936 0 45.96 0.084 ;
    END
  END rows[13]
  PIN rows[14]
    DIRECTION INPUT ;
    USE SIGNAL ;
    PORT
      LAYER M5 ;
        RECT  46.032 0 46.056 0.084 ;
    END
  END rows[14]
  PIN rows[15]
    DIRECTION INPUT ;
    USE SIGNAL ;
    PORT
      LAYER M5 ;
        RECT  46.128 0 46.152 0.084 ;
    END
  END rows[15]
  PIN rows[16]
    DIRECTION INPUT ;
    USE SIGNAL ;
    PORT
      LAYER M5 ;
        RECT  46.224 0 46.248 0.084 ;
    END
  END rows[16]
  PIN rows[17]
    DIRECTION INPUT ;
    USE SIGNAL ;
    PORT
      LAYER M5 ;
        RECT  46.32 0 46.344 0.084 ;
    END
  END rows[17]
  PIN rows[18]
    DIRECTION INPUT ;
    USE SIGNAL ;
    PORT
      LAYER M5 ;
        RECT  46.416 0 46.44 0.084 ;
    END
  END rows[18]
  PIN rows[19]
    DIRECTION INPUT ;
    USE SIGNAL ;
    PORT
      LAYER M5 ;
        RECT  46.512 0 46.536 0.084 ;
    END
  END rows[19]
  PIN rows[1]
    DIRECTION INPUT ;
    USE SIGNAL ;
    PORT
      LAYER M5 ;
        RECT  28.656 0 28.68 0.084 ;
    END
  END rows[1]
  PIN rows[20]
    DIRECTION INPUT ;
    USE SIGNAL ;
    PORT
      LAYER M5 ;
        RECT  46.608 0 46.632 0.084 ;
    END
  END rows[20]
  PIN rows[21]
    DIRECTION INPUT ;
    USE SIGNAL ;
    PORT
      LAYER M5 ;
        RECT  46.704 0 46.728 0.084 ;
    END
  END rows[21]
  PIN rows[22]
    DIRECTION INPUT ;
    USE SIGNAL ;
    PORT
      LAYER M5 ;
        RECT  46.8 0 46.824 0.084 ;
    END
  END rows[22]
  PIN rows[23]
    DIRECTION INPUT ;
    USE SIGNAL ;
    PORT
      LAYER M5 ;
        RECT  46.896 0 46.92 0.084 ;
    END
  END rows[23]
  PIN rows[24]
    DIRECTION INPUT ;
    USE SIGNAL ;
    PORT
      LAYER M5 ;
        RECT  46.992 0 47.016 0.084 ;
    END
  END rows[24]
  PIN rows[25]
    DIRECTION INPUT ;
    USE SIGNAL ;
    PORT
      LAYER M5 ;
        RECT  47.088 0 47.112 0.084 ;
    END
  END rows[25]
  PIN rows[26]
    DIRECTION INPUT ;
    USE SIGNAL ;
    PORT
      LAYER M5 ;
        RECT  47.184 0 47.208 0.084 ;
    END
  END rows[26]
  PIN rows[27]
    DIRECTION INPUT ;
    USE SIGNAL ;
    PORT
      LAYER M5 ;
        RECT  47.28 0 47.304 0.084 ;
    END
  END rows[27]
  PIN rows[28]
    DIRECTION INPUT ;
    USE SIGNAL ;
    PORT
      LAYER M5 ;
        RECT  47.376 0 47.4 0.084 ;
    END
  END rows[28]
  PIN rows[29]
    DIRECTION INPUT ;
    USE SIGNAL ;
    PORT
      LAYER M5 ;
        RECT  47.472 0 47.496 0.084 ;
    END
  END rows[29]
  PIN rows[2]
    DIRECTION INPUT ;
    USE SIGNAL ;
    PORT
      LAYER M5 ;
        RECT  28.752 0 28.776 0.084 ;
    END
  END rows[2]
  PIN rows[30]
    DIRECTION INPUT ;
    USE SIGNAL ;
    PORT
      LAYER M5 ;
        RECT  47.568 0 47.592 0.084 ;
    END
  END rows[30]
  PIN rows[31]
    DIRECTION INPUT ;
    USE SIGNAL ;
    PORT
      LAYER M5 ;
        RECT  47.664 0 47.688 0.084 ;
    END
  END rows[31]
  PIN rows[32]
    DIRECTION INPUT ;
    USE SIGNAL ;
    PORT
      LAYER M5 ;
        RECT  47.76 0 47.784 0.084 ;
    END
  END rows[32]
  PIN rows[33]
    DIRECTION INPUT ;
    USE SIGNAL ;
    PORT
      LAYER M5 ;
        RECT  47.856 0 47.88 0.084 ;
    END
  END rows[33]
  PIN rows[34]
    DIRECTION INPUT ;
    USE SIGNAL ;
    PORT
      LAYER M5 ;
        RECT  47.952 0 47.976 0.084 ;
    END
  END rows[34]
  PIN rows[35]
    DIRECTION INPUT ;
    USE SIGNAL ;
    PORT
      LAYER M5 ;
        RECT  48.048 0 48.072 0.084 ;
    END
  END rows[35]
  PIN rows[36]
    DIRECTION INPUT ;
    USE SIGNAL ;
    PORT
      LAYER M5 ;
        RECT  48.144 0 48.168 0.084 ;
    END
  END rows[36]
  PIN rows[37]
    DIRECTION INPUT ;
    USE SIGNAL ;
    PORT
      LAYER M5 ;
        RECT  48.24 0 48.264 0.084 ;
    END
  END rows[37]
  PIN rows[38]
    DIRECTION INPUT ;
    USE SIGNAL ;
    PORT
      LAYER M5 ;
        RECT  51.408 0 51.432 0.084 ;
    END
  END rows[38]
  PIN rows[39]
    DIRECTION INPUT ;
    USE SIGNAL ;
    PORT
      LAYER M5 ;
        RECT  51.504 0 51.528 0.084 ;
    END
  END rows[39]
  PIN rows[3]
    DIRECTION INPUT ;
    USE SIGNAL ;
    PORT
      LAYER M5 ;
        RECT  28.848 0 28.872 0.084 ;
    END
  END rows[3]
  PIN rows[40]
    DIRECTION INPUT ;
    USE SIGNAL ;
    PORT
      LAYER M5 ;
        RECT  51.6 0 51.624 0.084 ;
    END
  END rows[40]
  PIN rows[41]
    DIRECTION INPUT ;
    USE SIGNAL ;
    PORT
      LAYER M5 ;
        RECT  51.696 0 51.72 0.084 ;
    END
  END rows[41]
  PIN rows[42]
    DIRECTION INPUT ;
    USE SIGNAL ;
    PORT
      LAYER M5 ;
        RECT  51.792 0 51.816 0.084 ;
    END
  END rows[42]
  PIN rows[43]
    DIRECTION INPUT ;
    USE SIGNAL ;
    PORT
      LAYER M5 ;
        RECT  51.888 0 51.912 0.084 ;
    END
  END rows[43]
  PIN rows[44]
    DIRECTION INPUT ;
    USE SIGNAL ;
    PORT
      LAYER M5 ;
        RECT  51.984 0 52.008 0.084 ;
    END
  END rows[44]
  PIN rows[45]
    DIRECTION INPUT ;
    USE SIGNAL ;
    PORT
      LAYER M5 ;
        RECT  52.08 0 52.104 0.084 ;
    END
  END rows[45]
  PIN rows[46]
    DIRECTION INPUT ;
    USE SIGNAL ;
    PORT
      LAYER M5 ;
        RECT  52.176 0 52.2 0.084 ;
    END
  END rows[46]
  PIN rows[47]
    DIRECTION INPUT ;
    USE SIGNAL ;
    PORT
      LAYER M5 ;
        RECT  52.272 0 52.296 0.084 ;
    END
  END rows[47]
  PIN rows[48]
    DIRECTION INPUT ;
    USE SIGNAL ;
    PORT
      LAYER M5 ;
        RECT  52.368 0 52.392 0.084 ;
    END
  END rows[48]
  PIN rows[49]
    DIRECTION INPUT ;
    USE SIGNAL ;
    PORT
      LAYER M5 ;
        RECT  52.464 0 52.488 0.084 ;
    END
  END rows[49]
  PIN rows[4]
    DIRECTION INPUT ;
    USE SIGNAL ;
    PORT
      LAYER M5 ;
        RECT  28.944 0 28.968 0.084 ;
    END
  END rows[4]
  PIN rows[50]
    DIRECTION INPUT ;
    USE SIGNAL ;
    PORT
      LAYER M5 ;
        RECT  52.56 0 52.584 0.084 ;
    END
  END rows[50]
  PIN rows[51]
    DIRECTION INPUT ;
    USE SIGNAL ;
    PORT
      LAYER M5 ;
        RECT  52.656 0 52.68 0.084 ;
    END
  END rows[51]
  PIN rows[52]
    DIRECTION INPUT ;
    USE SIGNAL ;
    PORT
      LAYER M5 ;
        RECT  52.752 0 52.776 0.084 ;
    END
  END rows[52]
  PIN rows[53]
    DIRECTION INPUT ;
    USE SIGNAL ;
    PORT
      LAYER M5 ;
        RECT  52.848 0 52.872 0.084 ;
    END
  END rows[53]
  PIN rows[54]
    DIRECTION INPUT ;
    USE SIGNAL ;
    PORT
      LAYER M5 ;
        RECT  52.944 0 52.968 0.084 ;
    END
  END rows[54]
  PIN rows[55]
    DIRECTION INPUT ;
    USE SIGNAL ;
    PORT
      LAYER M5 ;
        RECT  53.04 0 53.064 0.084 ;
    END
  END rows[55]
  PIN rows[56]
    DIRECTION INPUT ;
    USE SIGNAL ;
    PORT
      LAYER M5 ;
        RECT  53.136 0 53.16 0.084 ;
    END
  END rows[56]
  PIN rows[57]
    DIRECTION INPUT ;
    USE SIGNAL ;
    PORT
      LAYER M5 ;
        RECT  53.232 0 53.256 0.084 ;
    END
  END rows[57]
  PIN rows[58]
    DIRECTION INPUT ;
    USE SIGNAL ;
    PORT
      LAYER M5 ;
        RECT  53.328 0 53.352 0.084 ;
    END
  END rows[58]
  PIN rows[59]
    DIRECTION INPUT ;
    USE SIGNAL ;
    PORT
      LAYER M5 ;
        RECT  53.424 0 53.448 0.084 ;
    END
  END rows[59]
  PIN rows[5]
    DIRECTION INPUT ;
    USE SIGNAL ;
    PORT
      LAYER M5 ;
        RECT  29.04 0 29.064 0.084 ;
    END
  END rows[5]
  PIN rows[60]
    DIRECTION INPUT ;
    USE SIGNAL ;
    PORT
      LAYER M5 ;
        RECT  53.52 0 53.544 0.084 ;
    END
  END rows[60]
  PIN rows[61]
    DIRECTION INPUT ;
    USE SIGNAL ;
    PORT
      LAYER M5 ;
        RECT  53.616 0 53.64 0.084 ;
    END
  END rows[61]
  PIN rows[62]
    DIRECTION INPUT ;
    USE SIGNAL ;
    PORT
      LAYER M5 ;
        RECT  53.712 0 53.736 0.084 ;
    END
  END rows[62]
  PIN rows[63]
    DIRECTION INPUT ;
    USE SIGNAL ;
    PORT
      LAYER M5 ;
        RECT  53.808 0 53.832 0.084 ;
    END
  END rows[63]
  PIN rows[64]
    DIRECTION INPUT ;
    USE SIGNAL ;
    PORT
      LAYER M5 ;
        RECT  53.904 0 53.928 0.084 ;
    END
  END rows[64]
  PIN rows[65]
    DIRECTION INPUT ;
    USE SIGNAL ;
    PORT
      LAYER M5 ;
        RECT  54 0 54.024 0.084 ;
    END
  END rows[65]
  PIN rows[66]
    DIRECTION INPUT ;
    USE SIGNAL ;
    PORT
      LAYER M5 ;
        RECT  54.096 0 54.12 0.084 ;
    END
  END rows[66]
  PIN rows[67]
    DIRECTION INPUT ;
    USE SIGNAL ;
    PORT
      LAYER M5 ;
        RECT  54.192 0 54.216 0.084 ;
    END
  END rows[67]
  PIN rows[68]
    DIRECTION INPUT ;
    USE SIGNAL ;
    PORT
      LAYER M5 ;
        RECT  54.288 0 54.312 0.084 ;
    END
  END rows[68]
  PIN rows[69]
    DIRECTION INPUT ;
    USE SIGNAL ;
    PORT
      LAYER M5 ;
        RECT  54.384 0 54.408 0.084 ;
    END
  END rows[69]
  PIN rows[6]
    DIRECTION INPUT ;
    USE SIGNAL ;
    PORT
      LAYER M5 ;
        RECT  45.264 0 45.288 0.084 ;
    END
  END rows[6]
  PIN rows[70]
    DIRECTION INPUT ;
    USE SIGNAL ;
    PORT
      LAYER M5 ;
        RECT  42.192 0 42.216 0.084 ;
    END
  END rows[70]
  PIN rows[71]
    DIRECTION INPUT ;
    USE SIGNAL ;
    PORT
      LAYER M5 ;
        RECT  42.288 0 42.312 0.084 ;
    END
  END rows[71]
  PIN rows[72]
    DIRECTION INPUT ;
    USE SIGNAL ;
    PORT
      LAYER M5 ;
        RECT  42.384 0 42.408 0.084 ;
    END
  END rows[72]
  PIN rows[73]
    DIRECTION INPUT ;
    USE SIGNAL ;
    PORT
      LAYER M5 ;
        RECT  42.48 0 42.504 0.084 ;
    END
  END rows[73]
  PIN rows[74]
    DIRECTION INPUT ;
    USE SIGNAL ;
    PORT
      LAYER M5 ;
        RECT  42.576 0 42.6 0.084 ;
    END
  END rows[74]
  PIN rows[75]
    DIRECTION INPUT ;
    USE SIGNAL ;
    PORT
      LAYER M5 ;
        RECT  42.672 0 42.696 0.084 ;
    END
  END rows[75]
  PIN rows[76]
    DIRECTION INPUT ;
    USE SIGNAL ;
    PORT
      LAYER M5 ;
        RECT  42.768 0 42.792 0.084 ;
    END
  END rows[76]
  PIN rows[77]
    DIRECTION INPUT ;
    USE SIGNAL ;
    PORT
      LAYER M5 ;
        RECT  42.864 0 42.888 0.084 ;
    END
  END rows[77]
  PIN rows[78]
    DIRECTION INPUT ;
    USE SIGNAL ;
    PORT
      LAYER M5 ;
        RECT  42.96 0 42.984 0.084 ;
    END
  END rows[78]
  PIN rows[79]
    DIRECTION INPUT ;
    USE SIGNAL ;
    PORT
      LAYER M5 ;
        RECT  43.056 0 43.08 0.084 ;
    END
  END rows[79]
  PIN rows[7]
    DIRECTION INPUT ;
    USE SIGNAL ;
    PORT
      LAYER M5 ;
        RECT  45.36 0 45.384 0.084 ;
    END
  END rows[7]
  PIN rows[80]
    DIRECTION INPUT ;
    USE SIGNAL ;
    PORT
      LAYER M5 ;
        RECT  43.152 0 43.176 0.084 ;
    END
  END rows[80]
  PIN rows[81]
    DIRECTION INPUT ;
    USE SIGNAL ;
    PORT
      LAYER M5 ;
        RECT  43.248 0 43.272 0.084 ;
    END
  END rows[81]
  PIN rows[82]
    DIRECTION INPUT ;
    USE SIGNAL ;
    PORT
      LAYER M5 ;
        RECT  43.344 0 43.368 0.084 ;
    END
  END rows[82]
  PIN rows[83]
    DIRECTION INPUT ;
    USE SIGNAL ;
    PORT
      LAYER M5 ;
        RECT  43.44 0 43.464 0.084 ;
    END
  END rows[83]
  PIN rows[84]
    DIRECTION INPUT ;
    USE SIGNAL ;
    PORT
      LAYER M5 ;
        RECT  43.536 0 43.56 0.084 ;
    END
  END rows[84]
  PIN rows[85]
    DIRECTION INPUT ;
    USE SIGNAL ;
    PORT
      LAYER M5 ;
        RECT  43.632 0 43.656 0.084 ;
    END
  END rows[85]
  PIN rows[86]
    DIRECTION INPUT ;
    USE SIGNAL ;
    PORT
      LAYER M5 ;
        RECT  43.728 0 43.752 0.084 ;
    END
  END rows[86]
  PIN rows[87]
    DIRECTION INPUT ;
    USE SIGNAL ;
    PORT
      LAYER M5 ;
        RECT  43.824 0 43.848 0.084 ;
    END
  END rows[87]
  PIN rows[88]
    DIRECTION INPUT ;
    USE SIGNAL ;
    PORT
      LAYER M5 ;
        RECT  43.92 0 43.944 0.084 ;
    END
  END rows[88]
  PIN rows[89]
    DIRECTION INPUT ;
    USE SIGNAL ;
    PORT
      LAYER M5 ;
        RECT  44.016 0 44.04 0.084 ;
    END
  END rows[89]
  PIN rows[8]
    DIRECTION INPUT ;
    USE SIGNAL ;
    PORT
      LAYER M5 ;
        RECT  45.456 0 45.48 0.084 ;
    END
  END rows[8]
  PIN rows[90]
    DIRECTION INPUT ;
    USE SIGNAL ;
    PORT
      LAYER M5 ;
        RECT  44.112 0 44.136 0.084 ;
    END
  END rows[90]
  PIN rows[91]
    DIRECTION INPUT ;
    USE SIGNAL ;
    PORT
      LAYER M5 ;
        RECT  44.208 0 44.232 0.084 ;
    END
  END rows[91]
  PIN rows[92]
    DIRECTION INPUT ;
    USE SIGNAL ;
    PORT
      LAYER M5 ;
        RECT  44.304 0 44.328 0.084 ;
    END
  END rows[92]
  PIN rows[93]
    DIRECTION INPUT ;
    USE SIGNAL ;
    PORT
      LAYER M5 ;
        RECT  44.4 0 44.424 0.084 ;
    END
  END rows[93]
  PIN rows[94]
    DIRECTION INPUT ;
    USE SIGNAL ;
    PORT
      LAYER M5 ;
        RECT  44.496 0 44.52 0.084 ;
    END
  END rows[94]
  PIN rows[95]
    DIRECTION INPUT ;
    USE SIGNAL ;
    PORT
      LAYER M5 ;
        RECT  44.592 0 44.616 0.084 ;
    END
  END rows[95]
  PIN rows[96]
    DIRECTION INPUT ;
    USE SIGNAL ;
    PORT
      LAYER M5 ;
        RECT  44.688 0 44.712 0.084 ;
    END
  END rows[96]
  PIN rows[97]
    DIRECTION INPUT ;
    USE SIGNAL ;
    PORT
      LAYER M5 ;
        RECT  44.784 0 44.808 0.084 ;
    END
  END rows[97]
  PIN rows[98]
    DIRECTION INPUT ;
    USE SIGNAL ;
    PORT
      LAYER M5 ;
        RECT  44.88 0 44.904 0.084 ;
    END
  END rows[98]
  PIN rows[99]
    DIRECTION INPUT ;
    USE SIGNAL ;
    PORT
      LAYER M5 ;
        RECT  44.976 0 45 0.084 ;
    END
  END rows[99]
  PIN rows[9]
    DIRECTION INPUT ;
    USE SIGNAL ;
    PORT
      LAYER M5 ;
        RECT  45.552 0 45.576 0.084 ;
    END
  END rows[9]
  PIN rst_pin
    DIRECTION INPUT ;
    USE SIGNAL ;
    PORT
      LAYER M5 ;
        RECT  37.776 0 37.8 0.084 ;
    END
  END rst_pin
  PIN ze_d
    DIRECTION INPUT ;
    USE SIGNAL ;
    PORT
      LAYER M5 ;
        RECT  37.872 0 37.896 0.084 ;
    END
  END ze_d
  PIN VSS
    DIRECTION INOUT ;
    USE GROUND ;
    PORT
      LAYER M5 ;
        RECT  105 2.137 105.12 62.663 ;
        RECT  99.6 2.137 99.72 62.663 ;
        RECT  94.2 2.137 94.32 62.663 ;
        RECT  88.8 2.137 88.92 62.663 ;
        RECT  83.4 2.137 83.52 62.663 ;
        RECT  78 2.137 78.12 62.663 ;
        RECT  72.6 2.137 72.72 62.663 ;
        RECT  67.2 2.137 67.32 62.663 ;
        RECT  61.8 2.137 61.92 62.663 ;
        RECT  56.4 2.137 56.52 62.663 ;
        RECT  51 2.137 51.12 62.663 ;
        RECT  45.6 2.137 45.72 62.663 ;
        RECT  40.2 2.137 40.32 62.663 ;
        RECT  34.8 2.137 34.92 62.663 ;
        RECT  29.4 2.137 29.52 62.663 ;
        RECT  24 2.137 24.12 62.663 ;
        RECT  18.6 2.137 18.72 62.663 ;
        RECT  13.2 2.137 13.32 62.663 ;
        RECT  7.8 2.137 7.92 62.663 ;
        RECT  2.4 2.137 2.52 62.663 ;
    END
  END VSS
  PIN VDD
    DIRECTION INOUT ;
    USE POWER ;
    PORT
      LAYER M5 ;
        RECT  105.192 2.151 105.312 62.649 ;
        RECT  99.792 2.151 99.912 62.649 ;
        RECT  94.392 2.151 94.512 62.649 ;
        RECT  88.992 2.151 89.112 62.649 ;
        RECT  83.592 2.151 83.712 62.649 ;
        RECT  78.192 2.151 78.312 62.649 ;
        RECT  72.792 2.151 72.912 62.649 ;
        RECT  67.392 2.151 67.512 62.649 ;
        RECT  61.992 2.151 62.112 62.649 ;
        RECT  56.592 2.151 56.712 62.649 ;
        RECT  51.192 2.151 51.312 62.649 ;
        RECT  45.792 2.151 45.912 62.649 ;
        RECT  40.392 2.151 40.512 62.649 ;
        RECT  34.992 2.151 35.112 62.649 ;
        RECT  29.592 2.151 29.712 62.649 ;
        RECT  24.192 2.151 24.312 62.649 ;
        RECT  18.792 2.151 18.912 62.649 ;
        RECT  13.392 2.151 13.512 62.649 ;
        RECT  7.992 2.151 8.112 62.649 ;
        RECT  2.592 2.151 2.712 62.649 ;
    END
  END VDD
  OBS
    LAYER RVTN ;
     RECT  2.16 2.16 105.84 2.295 ;
     RECT  2.16 2.565 105.84 2.835 ;
     RECT  2.16 3.105 105.84 3.375 ;
     RECT  2.16 3.645 105.84 3.915 ;
     RECT  2.16 4.185 105.84 4.455 ;
     RECT  2.16 4.725 105.84 4.995 ;
     RECT  2.16 5.265 105.84 5.535 ;
     RECT  2.16 5.805 105.84 6.075 ;
     RECT  2.16 6.345 105.84 6.615 ;
     RECT  2.16 6.885 105.84 7.155 ;
     RECT  2.16 7.425 105.84 7.695 ;
     RECT  2.16 7.965 105.84 8.235 ;
     RECT  2.16 8.505 105.84 8.775 ;
     RECT  2.16 9.045 105.84 9.315 ;
     RECT  2.16 9.585 105.84 9.855 ;
     RECT  2.16 10.125 105.84 10.395 ;
     RECT  2.16 10.665 105.84 10.935 ;
     RECT  2.16 11.205 105.84 11.475 ;
     RECT  2.16 11.745 105.84 12.015 ;
     RECT  2.16 12.285 105.84 12.555 ;
     RECT  2.16 12.825 105.84 13.095 ;
     RECT  2.16 13.365 105.84 13.635 ;
     RECT  2.16 13.905 105.84 14.175 ;
     RECT  2.16 14.445 105.84 14.715 ;
     RECT  2.16 14.985 105.84 15.255 ;
     RECT  2.16 15.525 105.84 15.795 ;
     RECT  2.16 16.065 105.84 16.335 ;
     RECT  2.16 16.605 105.84 16.875 ;
     RECT  2.16 17.145 105.84 17.415 ;
     RECT  2.16 17.685 105.84 17.955 ;
     RECT  2.16 18.225 105.84 18.495 ;
     RECT  2.16 18.765 105.84 19.035 ;
     RECT  2.16 19.305 105.84 19.575 ;
     RECT  2.16 19.845 105.84 20.115 ;
     RECT  2.16 20.385 105.84 20.655 ;
     RECT  2.16 20.925 105.84 21.195 ;
     RECT  2.16 21.465 105.84 21.735 ;
     RECT  2.16 22.005 105.84 22.275 ;
     RECT  2.16 22.545 105.84 22.815 ;
     RECT  2.16 23.085 105.84 23.355 ;
     RECT  2.16 23.625 105.84 23.895 ;
     RECT  2.16 24.165 105.84 24.435 ;
     RECT  2.16 24.705 105.84 24.975 ;
     RECT  2.16 25.245 105.84 25.515 ;
     RECT  2.16 25.785 105.84 26.055 ;
     RECT  2.16 26.325 105.84 26.595 ;
     RECT  2.16 26.865 105.84 27.135 ;
     RECT  2.16 27.405 105.84 27.675 ;
     RECT  2.16 27.945 105.84 28.215 ;
     RECT  2.16 28.485 105.84 28.755 ;
     RECT  2.16 29.025 105.84 29.295 ;
     RECT  2.16 29.565 105.84 29.835 ;
     RECT  2.16 30.105 105.84 30.375 ;
     RECT  2.16 30.645 105.84 30.915 ;
     RECT  2.16 31.185 105.84 31.455 ;
     RECT  2.16 31.725 105.84 31.995 ;
     RECT  2.16 32.265 105.84 32.535 ;
     RECT  2.16 32.805 105.84 33.075 ;
     RECT  2.16 33.345 105.84 33.615 ;
     RECT  2.16 33.885 105.84 34.155 ;
     RECT  2.16 34.425 105.84 34.695 ;
     RECT  2.16 34.965 105.84 35.235 ;
     RECT  2.16 35.505 105.84 35.775 ;
     RECT  2.16 36.045 105.84 36.315 ;
     RECT  2.16 36.585 105.84 36.855 ;
     RECT  2.16 37.125 105.84 37.395 ;
     RECT  2.16 37.665 105.84 37.935 ;
     RECT  2.16 38.205 105.84 38.475 ;
     RECT  2.16 38.745 105.84 39.015 ;
     RECT  2.16 39.285 105.84 39.555 ;
     RECT  2.16 39.825 105.84 40.095 ;
     RECT  2.16 40.365 105.84 40.635 ;
     RECT  2.16 40.905 105.84 41.175 ;
     RECT  2.16 41.445 105.84 41.715 ;
     RECT  2.16 41.985 105.84 42.255 ;
     RECT  2.16 42.525 105.84 42.795 ;
     RECT  2.16 43.065 105.84 43.335 ;
     RECT  2.16 43.605 105.84 43.875 ;
     RECT  2.16 44.145 105.84 44.415 ;
     RECT  2.16 44.685 105.84 44.955 ;
     RECT  2.16 45.225 105.84 45.495 ;
     RECT  2.16 45.765 105.84 46.035 ;
     RECT  2.16 46.305 105.84 46.575 ;
     RECT  2.16 46.845 105.84 47.115 ;
     RECT  2.16 47.385 105.84 47.655 ;
     RECT  2.16 47.925 105.84 48.195 ;
     RECT  2.16 48.465 105.84 48.735 ;
     RECT  2.16 49.005 105.84 49.275 ;
     RECT  2.16 49.545 105.84 49.815 ;
     RECT  2.16 50.085 105.84 50.355 ;
     RECT  2.16 50.625 105.84 50.895 ;
     RECT  2.16 51.165 105.84 51.435 ;
     RECT  2.16 51.705 105.84 51.975 ;
     RECT  2.16 52.245 105.84 52.515 ;
     RECT  2.16 52.785 105.84 53.055 ;
     RECT  2.16 53.325 105.84 53.595 ;
     RECT  2.16 53.865 105.84 54.135 ;
     RECT  2.16 54.405 105.84 54.675 ;
     RECT  2.16 54.945 105.84 55.215 ;
     RECT  2.16 55.485 105.84 55.755 ;
     RECT  2.16 56.025 105.84 56.295 ;
     RECT  2.16 56.565 105.84 56.835 ;
     RECT  2.16 57.105 105.84 57.375 ;
     RECT  2.16 57.645 105.84 57.915 ;
     RECT  2.16 58.185 105.84 58.455 ;
     RECT  2.16 58.725 105.84 58.995 ;
     RECT  2.16 59.265 105.84 59.535 ;
     RECT  2.16 59.805 105.84 60.075 ;
     RECT  2.16 60.345 105.84 60.615 ;
     RECT  2.16 60.885 105.84 61.155 ;
     RECT  2.16 61.425 105.84 61.695 ;
     RECT  2.16 61.965 105.84 62.235 ;
     RECT  2.16 62.505 105.84 62.64 ;
    LAYER RVTP ;
     RECT  2.16 2.295 105.84 2.565 ;
     RECT  2.16 2.835 105.84 3.105 ;
     RECT  2.16 3.375 105.84 3.645 ;
     RECT  2.16 3.915 105.84 4.185 ;
     RECT  2.16 4.455 105.84 4.725 ;
     RECT  2.16 4.995 105.84 5.265 ;
     RECT  2.16 5.535 105.84 5.805 ;
     RECT  2.16 6.075 105.84 6.345 ;
     RECT  2.16 6.615 105.84 6.885 ;
     RECT  2.16 7.155 105.84 7.425 ;
     RECT  2.16 7.695 105.84 7.965 ;
     RECT  2.16 8.235 105.84 8.505 ;
     RECT  2.16 8.775 105.84 9.045 ;
     RECT  2.16 9.315 105.84 9.585 ;
     RECT  2.16 9.855 105.84 10.125 ;
     RECT  2.16 10.395 105.84 10.665 ;
     RECT  2.16 10.935 105.84 11.205 ;
     RECT  2.16 11.475 105.84 11.745 ;
     RECT  2.16 12.015 105.84 12.285 ;
     RECT  2.16 12.555 105.84 12.825 ;
     RECT  2.16 13.095 105.84 13.365 ;
     RECT  2.16 13.635 105.84 13.905 ;
     RECT  2.16 14.175 105.84 14.445 ;
     RECT  2.16 14.715 105.84 14.985 ;
     RECT  2.16 15.255 105.84 15.525 ;
     RECT  2.16 15.795 105.84 16.065 ;
     RECT  2.16 16.335 105.84 16.605 ;
     RECT  2.16 16.875 105.84 17.145 ;
     RECT  2.16 17.415 105.84 17.685 ;
     RECT  2.16 17.955 105.84 18.225 ;
     RECT  2.16 18.495 105.84 18.765 ;
     RECT  2.16 19.035 105.84 19.305 ;
     RECT  2.16 19.575 105.84 19.845 ;
     RECT  2.16 20.115 105.84 20.385 ;
     RECT  2.16 20.655 105.84 20.925 ;
     RECT  2.16 21.195 105.84 21.465 ;
     RECT  2.16 21.735 105.84 22.005 ;
     RECT  2.16 22.275 105.84 22.545 ;
     RECT  2.16 22.815 105.84 23.085 ;
     RECT  2.16 23.355 105.84 23.625 ;
     RECT  2.16 23.895 105.84 24.165 ;
     RECT  2.16 24.435 105.84 24.705 ;
     RECT  2.16 24.975 105.84 25.245 ;
     RECT  2.16 25.515 105.84 25.785 ;
     RECT  2.16 26.055 105.84 26.325 ;
     RECT  2.16 26.595 105.84 26.865 ;
     RECT  2.16 27.135 105.84 27.405 ;
     RECT  2.16 27.675 105.84 27.945 ;
     RECT  2.16 28.215 105.84 28.485 ;
     RECT  2.16 28.755 105.84 29.025 ;
     RECT  2.16 29.295 105.84 29.565 ;
     RECT  2.16 29.835 105.84 30.105 ;
     RECT  2.16 30.375 105.84 30.645 ;
     RECT  2.16 30.915 105.84 31.185 ;
     RECT  2.16 31.455 105.84 31.725 ;
     RECT  2.16 31.995 105.84 32.265 ;
     RECT  2.16 32.535 105.84 32.805 ;
     RECT  2.16 33.075 105.84 33.345 ;
     RECT  2.16 33.615 105.84 33.885 ;
     RECT  2.16 34.155 105.84 34.425 ;
     RECT  2.16 34.695 105.84 34.965 ;
     RECT  2.16 35.235 105.84 35.505 ;
     RECT  2.16 35.775 105.84 36.045 ;
     RECT  2.16 36.315 105.84 36.585 ;
     RECT  2.16 36.855 105.84 37.125 ;
     RECT  2.16 37.395 105.84 37.665 ;
     RECT  2.16 37.935 105.84 38.205 ;
     RECT  2.16 38.475 105.84 38.745 ;
     RECT  2.16 39.015 105.84 39.285 ;
     RECT  2.16 39.555 105.84 39.825 ;
     RECT  2.16 40.095 105.84 40.365 ;
     RECT  2.16 40.635 105.84 40.905 ;
     RECT  2.16 41.175 105.84 41.445 ;
     RECT  2.16 41.715 105.84 41.985 ;
     RECT  2.16 42.255 105.84 42.525 ;
     RECT  2.16 42.795 105.84 43.065 ;
     RECT  2.16 43.335 105.84 43.605 ;
     RECT  2.16 43.875 105.84 44.145 ;
     RECT  2.16 44.415 105.84 44.685 ;
     RECT  2.16 44.955 105.84 45.225 ;
     RECT  2.16 45.495 105.84 45.765 ;
     RECT  2.16 46.035 105.84 46.305 ;
     RECT  2.16 46.575 105.84 46.845 ;
     RECT  2.16 47.115 105.84 47.385 ;
     RECT  2.16 47.655 105.84 47.925 ;
     RECT  2.16 48.195 105.84 48.465 ;
     RECT  2.16 48.735 105.84 49.005 ;
     RECT  2.16 49.275 105.84 49.545 ;
     RECT  2.16 49.815 105.84 50.085 ;
     RECT  2.16 50.355 105.84 50.625 ;
     RECT  2.16 50.895 105.84 51.165 ;
     RECT  2.16 51.435 105.84 51.705 ;
     RECT  2.16 51.975 105.84 52.245 ;
     RECT  2.16 52.515 105.84 52.785 ;
     RECT  2.16 53.055 105.84 53.325 ;
     RECT  2.16 53.595 105.84 53.865 ;
     RECT  2.16 54.135 105.84 54.405 ;
     RECT  2.16 54.675 105.84 54.945 ;
     RECT  2.16 55.215 105.84 55.485 ;
     RECT  2.16 55.755 105.84 56.025 ;
     RECT  2.16 56.295 105.84 56.565 ;
     RECT  2.16 56.835 105.84 57.105 ;
     RECT  2.16 57.375 105.84 57.645 ;
     RECT  2.16 57.915 105.84 58.185 ;
     RECT  2.16 58.455 105.84 58.725 ;
     RECT  2.16 58.995 105.84 59.265 ;
     RECT  2.16 59.535 105.84 59.805 ;
     RECT  2.16 60.075 105.84 60.345 ;
     RECT  2.16 60.615 105.84 60.885 ;
     RECT  2.16 61.155 105.84 61.425 ;
     RECT  2.16 61.695 105.84 61.965 ;
     RECT  2.16 62.235 105.84 62.505 ;
    LAYER M1 ;
     RECT  2.16 2.151 105.84 62.649 ;
    LAYER M2 ;
     RECT  2.16 2.151 12.739 62.649 ;
     RECT  12.739 2.106 13.559 62.649 ;
     RECT  13.559 2.151 33.655 62.649 ;
     RECT  33.655 2.106 33.827 62.649 ;
     RECT  35.959 1.152 36.059 1.17 ;
     RECT  36.787 1.152 36.887 1.17 ;
     RECT  33.827 2.151 37.003 62.649 ;
     RECT  37.003 2.106 37.579 62.649 ;
     RECT  37.579 2.07 37.967 62.649 ;
     RECT  37.967 2.106 39.551 62.649 ;
     RECT  46.363 1.152 46.463 1.17 ;
     RECT  47.371 1.224 47.443 1.242 ;
     RECT  47.443 1.152 47.471 1.242 ;
     RECT  47.471 1.152 48.263 1.17 ;
     RECT  39.551 2.151 50.503 62.649 ;
     RECT  50.503 2.106 50.719 62.649 ;
     RECT  50.719 1.998 50.971 62.649 ;
     RECT  50.971 1.926 51.935 62.649 ;
     RECT  51.907 1.152 51.979 1.17 ;
     RECT  51.979 1.152 52.079 1.242 ;
     RECT  51.935 2.07 52.223 62.649 ;
     RECT  52.223 2.106 52.691 62.649 ;
     RECT  53.023 1.152 53.599 1.17 ;
     RECT  53.599 1.152 53.707 1.278 ;
     RECT  53.707 1.152 53.843 1.359 ;
     RECT  53.843 1.152 54.095 1.17 ;
     RECT  52.691 2.151 54.715 62.649 ;
     RECT  54.715 2.106 56.075 62.649 ;
     RECT  56.075 2.151 105.84 62.649 ;
     RECT  105.84 8.748 106.043 8.766 ;
     RECT  105.84 33.858 106.619 37.044 ;
     RECT  106.619 33.858 106.691 35.964 ;
     RECT  106.619 36.756 107.123 37.044 ;
     RECT  105.84 38.106 107.123 40.014 ;
     RECT  105.84 5.544 107.159 7.884 ;
     RECT  105.84 9.756 107.159 12.744 ;
     RECT  107.123 36.756 107.159 36.774 ;
     RECT  107.123 38.106 107.159 38.124 ;
     RECT  107.159 5.778 107.303 7.884 ;
     RECT  107.303 5.778 107.339 7.074 ;
     RECT  106.691 33.858 107.339 35.334 ;
     RECT  107.339 33.858 107.771 34.758 ;
     RECT  107.339 5.778 107.807 6.57 ;
     RECT  107.159 10.476 107.807 12.744 ;
     RECT  107.123 39.096 107.807 40.014 ;
     RECT  107.807 10.476 107.843 11.232 ;
     RECT  107.771 33.858 107.843 34.686 ;
     RECT  105.84 40.806 107.843 41.094 ;
     RECT  107.807 5.778 107.879 6.264 ;
     RECT  107.843 34.164 107.879 34.686 ;
     RECT  107.807 39.096 107.879 39.744 ;
     RECT  107.879 5.778 107.915 6.174 ;
     RECT  107.843 10.476 107.915 11.124 ;
     RECT  107.879 34.164 107.915 34.182 ;
     RECT  107.879 39.096 107.915 39.114 ;
     RECT  107.807 12.186 107.951 12.744 ;
     RECT  107.915 5.778 107.987 5.796 ;
     RECT  107.887 8.01 107.987 8.028 ;
     RECT  107.707 9.666 107.987 9.684 ;
     RECT  107.951 12.186 107.987 12.204 ;
     RECT  107.843 41.076 107.987 41.094 ;
    LAYER M3 ;
     RECT  25.992 0.043 26.01 0.091 ;
     RECT  28.044 0.043 28.062 0.091 ;
     RECT  12.996 0.091 13.014 0.139 ;
     RECT  25.776 0.091 28.386 0.139 ;
     RECT  29.34 0.091 29.358 0.139 ;
     RECT  35.28 0.091 35.982 0.139 ;
     RECT  38.088 0.091 38.106 0.139 ;
     RECT  43.596 0.091 43.614 0.139 ;
     RECT  45.576 0.091 45.594 0.139 ;
     RECT  46.44 0.091 46.458 0.139 ;
     RECT  47.376 0.091 47.97 0.139 ;
     RECT  53.028 0.091 53.046 0.139 ;
     RECT  38.088 0.139 38.322 0.187 ;
     RECT  46.44 0.139 47.97 0.187 ;
     RECT  52.38 0.139 53.046 0.187 ;
     RECT  53.82 0.091 53.838 0.187 ;
     RECT  45.36 0.139 45.594 0.221 ;
     RECT  46.44 0.187 48.042 0.235 ;
     RECT  35.28 0.139 36.774 0.317 ;
     RECT  32.508 0.091 33.318 0.523 ;
     RECT  42.264 0.427 42.282 0.523 ;
     RECT  52.38 0.187 53.838 0.523 ;
     RECT  11.088 0.091 11.61 0.571 ;
     RECT  12.42 0.139 13.014 0.571 ;
     RECT  24.624 0.091 24.642 0.571 ;
     RECT  25.776 0.139 29.358 0.571 ;
     RECT  35.964 0.317 36.774 0.571 ;
     RECT  51.984 0.523 54.018 0.571 ;
     RECT  51.408 0.571 54.018 0.619 ;
     RECT  23.472 0.571 23.49 1.147 ;
     RECT  42.228 0.523 42.282 1.147 ;
     RECT  43.452 0.139 43.614 1.147 ;
     RECT  46.44 0.235 48.258 1.147 ;
     RECT  51.336 0.619 54.018 1.147 ;
     RECT  35.964 0.571 36.882 1.175 ;
     RECT  46.368 1.147 48.258 1.175 ;
     RECT  10.116 1.147 10.134 1.627 ;
     RECT  11.088 0.571 13.014 1.627 ;
     RECT  10.116 1.627 13.014 1.723 ;
     RECT  23.184 1.147 23.49 1.723 ;
     RECT  24.624 0.571 29.358 1.723 ;
     RECT  31.968 0.523 33.318 1.723 ;
     RECT  36.036 1.175 36.882 1.723 ;
     RECT  38.088 0.187 38.466 1.723 ;
     RECT  42.228 1.147 43.614 1.723 ;
     RECT  44.46 0.091 44.478 1.723 ;
     RECT  45.36 0.221 45.378 1.723 ;
     RECT  46.368 1.175 48.15 1.723 ;
     RECT  51.336 1.147 54.09 1.723 ;
     RECT  22.824 1.723 23.742 1.771 ;
     RECT  24.552 1.723 29.358 1.771 ;
     RECT  51.336 1.723 54.486 1.771 ;
     RECT  49.176 1.771 49.194 1.819 ;
     RECT  42.228 1.723 48.15 1.915 ;
     RECT  51.336 1.771 54.594 1.921 ;
     RECT  50.976 1.921 54.594 1.993 ;
     RECT  9.684 1.723 13.014 2.101 ;
     RECT  36.036 1.723 38.466 2.101 ;
     RECT  50.724 1.993 54.594 2.101 ;
     RECT  55.584 0.187 55.602 2.101 ;
     RECT  22.824 1.771 29.358 2.143 ;
     RECT  30.096 1.867 30.114 2.143 ;
     RECT  36.036 2.101 39.546 2.143 ;
     RECT  55.584 2.101 56.07 2.143 ;
     RECT  9.684 2.101 13.554 2.191 ;
     RECT  31.968 1.723 35.262 2.191 ;
     RECT  36.036 2.143 40.305 2.191 ;
     RECT  42.228 1.915 48.222 2.191 ;
     RECT  49.176 1.819 49.446 2.191 ;
     RECT  50.508 2.101 54.738 2.191 ;
     RECT  55.584 2.143 56.505 2.191 ;
     RECT  31.968 2.191 40.305 2.227 ;
     RECT  42.228 2.191 49.446 2.227 ;
     RECT  31.428 2.227 40.305 2.263 ;
     RECT  42.084 2.227 49.446 2.263 ;
     RECT  50.436 2.191 56.505 2.263 ;
     RECT  31.356 2.263 40.305 2.299 ;
     RECT  41.364 2.263 56.505 2.299 ;
     RECT  22.824 2.143 30.114 2.335 ;
     RECT  22.824 2.335 30.258 2.371 ;
     RECT  31.356 2.299 56.505 2.371 ;
     RECT  2.415 2.143 2.505 2.413 ;
     RECT  7.815 2.143 7.905 2.413 ;
     RECT  18.615 2.143 18.705 2.413 ;
     RECT  22.824 2.371 56.505 2.413 ;
     RECT  61.815 2.143 61.905 2.413 ;
     RECT  67.215 2.143 67.305 2.413 ;
     RECT  72.615 2.143 72.705 2.413 ;
     RECT  78.015 2.143 78.105 2.413 ;
     RECT  83.415 2.143 83.505 2.413 ;
     RECT  88.815 2.143 88.905 2.413 ;
     RECT  94.215 2.143 94.305 2.413 ;
     RECT  99.615 2.143 99.705 2.413 ;
     RECT  105.015 2.143 105.105 2.413 ;
     RECT  22.824 2.413 56.697 2.497 ;
     RECT  9.684 2.191 14.094 2.641 ;
     RECT  14.94 2.227 14.958 2.641 ;
     RECT  22.824 2.497 56.826 2.641 ;
     RECT  9.684 2.641 14.958 2.803 ;
     RECT  22.428 2.641 56.826 2.803 ;
     RECT  22.356 2.803 56.826 2.911 ;
     RECT  22.356 2.911 56.934 3.067 ;
     RECT  7.815 2.413 8.097 3.181 ;
     RECT  9.684 2.803 15.354 3.181 ;
     RECT  58.104 3.109 58.122 3.181 ;
     RECT  57.924 3.181 58.122 3.271 ;
     RECT  9.612 3.181 15.354 3.299 ;
     RECT  57.888 3.271 58.122 3.307 ;
     RECT  67.215 2.413 67.497 3.307 ;
     RECT  67.176 3.307 67.497 3.343 ;
     RECT  70.128 3.271 70.146 3.343 ;
     RECT  22.356 3.067 57.114 3.379 ;
     RECT  57.888 3.307 58.23 3.379 ;
     RECT  69.624 3.343 70.146 3.403 ;
     RECT  72.615 2.413 72.897 3.415 ;
     RECT  78.015 2.413 78.297 3.415 ;
     RECT  7.815 3.181 8.766 3.437 ;
     RECT  22.356 3.379 58.23 3.451 ;
     RECT  68.904 3.403 70.146 3.451 ;
     RECT  72.396 3.415 72.897 3.451 ;
     RECT  77.256 3.415 78.297 3.451 ;
     RECT  67.176 3.343 67.554 3.541 ;
     RECT  68.328 3.451 70.614 3.541 ;
     RECT  72.144 3.451 72.954 3.541 ;
     RECT  75.132 3.415 75.15 3.541 ;
     RECT  67.176 3.541 70.614 3.577 ;
     RECT  74.484 3.541 75.15 3.577 ;
     RECT  21.168 3.307 21.186 3.613 ;
     RECT  71.928 3.541 72.954 3.613 ;
     RECT  74.484 3.577 75.474 3.613 ;
     RECT  77.256 3.451 78.822 3.649 ;
     RECT  79.668 3.613 79.686 3.649 ;
     RECT  63.864 3.541 63.882 3.685 ;
     RECT  67.176 3.577 70.686 3.685 ;
     RECT  74.448 3.613 75.474 3.685 ;
     RECT  77.148 3.649 78.858 3.685 ;
     RECT  79.668 3.649 79.794 3.685 ;
     RECT  65.592 3.649 65.61 3.721 ;
     RECT  67.176 3.685 70.866 3.721 ;
     RECT  71.928 3.613 73.53 3.721 ;
     RECT  74.448 3.685 75.87 3.721 ;
     RECT  77.148 3.685 79.794 3.721 ;
     RECT  80.748 3.451 80.766 3.721 ;
     RECT  21.096 3.613 21.186 3.749 ;
     RECT  21.168 3.749 21.186 3.811 ;
     RECT  65.448 3.721 65.646 3.811 ;
     RECT  66.816 3.721 73.53 3.811 ;
     RECT  74.448 3.721 76.05 3.811 ;
     RECT  16.164 3.721 16.182 3.839 ;
     RECT  77.04 3.721 80.766 3.847 ;
     RECT  83.415 2.413 83.697 3.847 ;
     RECT  63.864 3.685 64.062 3.883 ;
     RECT  85.14 3.811 85.158 3.883 ;
     RECT  21.168 3.811 21.222 3.919 ;
     RECT  22.248 3.451 58.23 3.919 ;
     RECT  82.08 3.847 82.098 3.919 ;
     RECT  63.612 3.883 64.062 3.931 ;
     RECT  65.448 3.811 76.05 3.955 ;
     RECT  77.04 3.847 81.342 3.955 ;
     RECT  82.08 3.919 82.242 3.955 ;
     RECT  86.184 3.931 86.202 3.955 ;
     RECT  65.448 3.955 81.342 3.991 ;
     RECT  82.08 3.955 82.35 3.991 ;
     RECT  65.448 3.991 82.35 4.075 ;
     RECT  63.108 3.931 64.062 4.081 ;
     RECT  65.448 4.075 82.674 4.117 ;
     RECT  21.168 3.919 58.23 4.145 ;
     RECT  61.815 2.413 62.097 4.153 ;
     RECT  63.108 4.081 64.17 4.171 ;
     RECT  61.704 4.153 62.097 4.189 ;
     RECT  63.108 4.171 64.206 4.189 ;
     RECT  65.16 4.117 82.674 4.189 ;
     RECT  88.815 2.413 89.097 4.189 ;
     RECT  90 4.117 90.018 4.189 ;
     RECT  92.304 3.991 92.322 4.189 ;
     RECT  91.764 4.189 92.574 4.216 ;
     RECT  21.78 4.145 58.23 4.217 ;
     RECT  94.215 2.413 94.497 4.219 ;
     RECT  61.632 4.189 64.206 4.225 ;
     RECT  18.615 2.413 18.897 4.261 ;
     RECT  61.488 4.225 64.206 4.261 ;
     RECT  65.124 4.189 82.674 4.261 ;
     RECT  83.415 3.847 83.79 4.261 ;
     RECT  84.78 3.883 85.158 4.261 ;
     RECT  86.112 3.955 86.31 4.261 ;
     RECT  91.764 4.216 92.718 4.261 ;
     RECT  93.924 4.219 94.497 4.261 ;
     RECT  95.976 3.991 95.994 4.261 ;
     RECT  9.684 3.299 15.354 4.387 ;
     RECT  65.124 4.261 83.934 4.387 ;
     RECT  84.78 4.261 86.598 4.387 ;
     RECT  9.684 4.387 15.39 4.423 ;
     RECT  60.768 4.261 64.206 4.495 ;
     RECT  65.124 4.387 86.598 4.495 ;
     RECT  95.292 4.261 95.994 4.495 ;
     RECT  60.444 4.495 64.206 4.531 ;
     RECT  64.98 4.495 86.598 4.531 ;
     RECT  90.792 4.495 90.81 4.531 ;
     RECT  88.815 4.189 90.018 4.603 ;
     RECT  90.792 4.531 91.026 4.603 ;
     RECT  90.756 4.603 91.026 4.621 ;
     RECT  91.764 4.261 94.497 4.621 ;
     RECT  95.292 4.495 96.534 4.621 ;
     RECT  88.524 4.603 90.018 4.651 ;
     RECT  90.756 4.621 96.534 4.651 ;
     RECT  60.444 4.531 86.598 4.657 ;
     RECT  88.524 4.651 96.534 4.657 ;
     RECT  9.432 4.423 15.39 4.685 ;
     RECT  88.524 4.657 96.57 4.693 ;
     RECT  21.96 4.217 58.23 4.729 ;
     RECT  59.112 4.153 59.13 4.729 ;
     RECT  88.344 4.693 96.57 4.729 ;
     RECT  60.444 4.657 87.138 4.765 ;
     RECT  88.344 4.729 96.642 4.765 ;
     RECT  60.444 4.765 87.354 4.801 ;
     RECT  88.344 4.765 96.786 4.801 ;
     RECT  60.444 4.801 96.786 4.891 ;
     RECT  59.868 4.891 96.786 5.035 ;
     RECT  7.815 3.437 8.097 5.071 ;
     RECT  9.684 4.685 15.39 5.071 ;
     RECT  21.96 4.729 59.13 5.071 ;
     RECT  59.868 5.035 96.93 5.071 ;
     RECT  99.615 2.413 99.897 5.071 ;
     RECT  99 5.071 99.897 5.161 ;
     RECT  21.96 5.071 96.93 5.261 ;
     RECT  21.096 5.161 21.114 5.341 ;
     RECT  21.96 5.261 96.858 5.341 ;
     RECT  21.096 5.341 96.858 5.459 ;
     RECT  21.096 5.459 21.186 5.467 ;
     RECT  20.7 5.467 21.186 5.503 ;
     RECT  105.015 2.413 105.297 5.575 ;
     RECT  107.136 5.539 107.154 5.611 ;
     RECT  20.52 5.503 21.186 5.639 ;
     RECT  104.94 5.575 105.498 5.701 ;
     RECT  22.212 5.459 96.858 5.729 ;
     RECT  103.644 5.845 103.662 5.881 ;
     RECT  104.4 5.701 105.642 5.881 ;
     RECT  106.596 5.611 107.154 5.881 ;
     RECT  107.964 5.773 107.982 5.881 ;
     RECT  21.096 5.639 21.186 5.909 ;
     RECT  22.5 5.729 96.858 5.999 ;
     RECT  103.644 5.881 105.642 6.007 ;
     RECT  106.596 5.881 107.982 6.007 ;
     RECT  23.904 5.999 96.858 6.043 ;
     RECT  97.74 5.161 99.897 6.043 ;
     RECT  100.62 5.563 100.638 6.043 ;
     RECT  102.708 4.987 102.726 6.115 ;
     RECT  23.904 6.043 99.897 6.151 ;
     RECT  100.62 6.043 101.25 6.151 ;
     RECT  18.615 4.261 19.278 6.277 ;
     RECT  9.684 5.071 15.606 6.349 ;
     RECT  23.904 6.151 101.25 6.385 ;
     RECT  102.708 6.115 102.906 6.385 ;
     RECT  102.564 6.385 102.906 6.421 ;
     RECT  23.904 6.385 101.43 6.475 ;
     RECT  102.492 6.421 102.906 6.475 ;
     RECT  22.5 5.999 23.094 6.583 ;
     RECT  18.036 6.277 19.278 6.613 ;
     RECT  7.815 5.071 8.766 6.619 ;
     RECT  18.036 6.613 19.53 6.655 ;
     RECT  21.168 5.909 21.186 6.655 ;
     RECT  22.32 6.583 23.094 6.655 ;
     RECT  23.904 6.475 102.906 6.655 ;
     RECT  103.644 6.007 107.982 6.655 ;
     RECT  7.272 6.619 8.766 6.691 ;
     RECT  9.684 6.349 16.002 6.691 ;
     RECT  16.812 5.161 16.83 6.691 ;
     RECT  17.964 6.655 20.142 6.691 ;
     RECT  21.168 6.655 23.094 6.691 ;
     RECT  9.684 6.691 16.83 6.808 ;
     RECT  17.82 6.691 23.094 6.808 ;
     RECT  23.904 6.655 107.982 6.811 ;
     RECT  9.684 6.808 23.094 6.961 ;
     RECT  23.832 6.811 107.982 6.961 ;
     RECT  9.684 6.961 107.982 7.187 ;
     RECT  9.684 7.187 106.002 7.373 ;
     RECT  9.684 7.373 105.642 7.655 ;
     RECT  6.66 6.691 8.766 7.771 ;
     RECT  9.684 7.655 85.554 7.771 ;
     RECT  6.66 7.771 85.554 7.799 ;
     RECT  107.172 7.187 107.982 8.033 ;
     RECT  86.436 7.655 105.642 8.395 ;
     RECT  43.2 7.799 85.554 8.473 ;
     RECT  86.436 8.395 106.038 8.473 ;
     RECT  6.66 7.799 42.462 8.581 ;
     RECT  43.2 8.473 106.038 8.581 ;
     RECT  6.66 8.581 106.038 8.771 ;
     RECT  107.172 8.033 107.91 8.779 ;
     RECT  6.66 8.771 105.57 9.355 ;
     RECT  106.524 8.779 107.91 9.661 ;
     RECT  6.444 9.355 105.57 9.677 ;
     RECT  6.516 9.677 105.57 10.291 ;
     RECT  6.516 10.291 105.714 10.319 ;
     RECT  6.516 10.319 67.662 10.471 ;
     RECT  5.076 10.471 67.662 10.733 ;
     RECT  5.076 10.733 42.498 10.933 ;
     RECT  106.524 9.661 107.982 10.967 ;
     RECT  5.004 10.933 42.498 10.975 ;
     RECT  43.488 10.733 67.662 11.137 ;
     RECT  68.436 10.319 105.714 11.137 ;
     RECT  43.488 11.137 105.714 11.165 ;
     RECT  4.86 10.975 42.498 11.173 ;
     RECT  4.212 11.173 42.498 11.209 ;
     RECT  3.852 11.209 42.498 11.245 ;
     RECT  3.78 11.245 42.498 11.281 ;
     RECT  43.56 11.165 105.714 11.399 ;
     RECT  2.415 2.413 2.697 11.551 ;
     RECT  3.42 11.281 42.498 11.551 ;
     RECT  43.56 11.399 105.642 11.669 ;
     RECT  106.524 10.967 106.542 11.669 ;
     RECT  43.56 11.669 105.426 11.741 ;
     RECT  107.712 10.967 107.982 11.939 ;
     RECT  43.56 11.741 105.39 11.975 ;
     RECT  2.415 11.551 42.75 11.983 ;
     RECT  43.56 11.975 105.354 11.983 ;
     RECT  107.928 11.939 107.982 12.209 ;
     RECT  2.415 11.983 105.354 12.245 ;
     RECT  2.415 12.245 105.297 12.557 ;
     RECT  107.928 12.209 107.946 12.749 ;
     RECT  3.528 12.557 105.297 13.369 ;
     RECT  3.492 13.369 105.297 13.595 ;
     RECT  3.492 13.595 38.574 13.639 ;
     RECT  39.348 13.595 105.297 14.405 ;
     RECT  39.492 14.405 105.297 14.675 ;
     RECT  39.6 14.675 105.297 15.421 ;
     RECT  2.415 12.557 2.697 15.493 ;
     RECT  3.42 13.639 38.574 15.493 ;
     RECT  2.415 15.493 38.79 15.601 ;
     RECT  39.564 15.421 105.297 15.601 ;
     RECT  2.415 15.601 105.297 15.629 ;
     RECT  2.415 15.629 30.69 16.141 ;
     RECT  2.376 16.141 30.69 16.169 ;
     RECT  3.42 16.169 30.69 16.411 ;
     RECT  31.572 15.629 105.297 16.411 ;
     RECT  3.42 16.411 105.354 16.501 ;
     RECT  3.42 16.501 105.462 16.601 ;
     RECT  2.376 16.169 2.697 16.951 ;
     RECT  3.42 16.601 105.354 16.951 ;
     RECT  2.376 16.951 105.354 16.979 ;
     RECT  2.412 16.979 105.354 17.069 ;
     RECT  2.412 17.069 38.574 17.105 ;
     RECT  39.348 17.069 105.354 17.141 ;
     RECT  2.415 17.105 38.574 17.375 ;
     RECT  38.556 17.375 38.574 17.411 ;
     RECT  2.415 17.375 37.746 17.609 ;
     RECT  2.415 17.609 37.638 17.879 ;
     RECT  39.348 17.141 105.297 18.157 ;
     RECT  2.415 17.879 37.098 18.185 ;
     RECT  38.916 18.157 105.297 18.499 ;
     RECT  38.628 18.499 105.297 18.571 ;
     RECT  38.628 18.571 105.354 18.689 ;
     RECT  2.415 18.185 25.038 18.931 ;
     RECT  25.848 18.185 37.098 18.931 ;
     RECT  76.356 18.689 105.354 18.959 ;
     RECT  2.415 18.931 37.098 19.075 ;
     RECT  38.628 18.689 75.51 19.075 ;
     RECT  38.484 19.075 75.51 19.103 ;
     RECT  2.415 19.075 37.674 19.111 ;
     RECT  38.484 19.103 65.754 19.111 ;
     RECT  66.708 19.103 75.51 19.139 ;
     RECT  66.96 19.139 75.51 19.421 ;
     RECT  66.96 19.421 68.598 19.517 ;
     RECT  69.336 19.421 75.51 19.543 ;
     RECT  76.356 18.959 105.297 19.543 ;
     RECT  69.336 19.543 105.297 19.679 ;
     RECT  2.415 19.111 65.754 19.805 ;
     RECT  39.636 19.805 65.754 19.913 ;
     RECT  44.136 19.913 65.754 19.921 ;
     RECT  44.136 19.921 66.114 19.963 ;
     RECT  76.788 19.679 105.297 20.147 ;
     RECT  66.996 19.517 68.598 20.191 ;
     RECT  69.336 19.679 75.978 20.191 ;
     RECT  76.788 20.147 104.274 20.417 ;
     RECT  44.136 19.963 66.258 20.425 ;
     RECT  66.996 20.191 75.978 20.425 ;
     RECT  2.415 19.805 38.898 20.587 ;
     RECT  39.636 19.913 43.398 20.587 ;
     RECT  44.136 20.425 75.978 20.683 ;
     RECT  76.788 20.417 104.238 20.683 ;
     RECT  44.136 20.683 104.238 20.687 ;
     RECT  44.136 20.687 79.506 20.723 ;
     RECT  80.244 20.687 103.338 20.723 ;
     RECT  2.415 20.587 43.398 20.731 ;
     RECT  44.136 20.723 77.13 20.731 ;
     RECT  77.94 20.723 79.506 20.759 ;
     RECT  104.148 20.687 104.238 20.849 ;
     RECT  104.148 20.849 104.166 20.885 ;
     RECT  80.244 20.723 103.122 20.963 ;
     RECT  2.415 20.731 77.13 21.029 ;
     RECT  2.415 21.029 10.71 21.119 ;
     RECT  98.712 20.963 103.122 21.119 ;
     RECT  3.708 21.119 10.71 21.155 ;
     RECT  11.52 21.029 77.13 21.155 ;
     RECT  80.244 20.963 97.614 21.155 ;
     RECT  3.708 21.155 9.594 21.197 ;
     RECT  3.708 21.197 8.097 21.227 ;
     RECT  5.076 21.227 8.097 21.263 ;
     RECT  9.576 21.197 9.594 21.299 ;
     RECT  5.436 21.263 8.097 21.389 ;
     RECT  11.556 21.155 77.13 21.389 ;
     RECT  80.244 21.155 97.002 21.389 ;
     RECT  98.712 21.119 102.546 21.389 ;
     RECT  5.688 21.389 5.922 21.425 ;
     RECT  11.556 21.389 26.55 21.425 ;
     RECT  77.94 20.759 79.434 21.499 ;
     RECT  99.504 21.389 102.546 21.533 ;
     RECT  77.868 21.499 79.434 21.541 ;
     RECT  98.712 21.389 98.73 21.569 ;
     RECT  6.768 21.389 8.097 21.581 ;
     RECT  11.556 21.425 26.442 21.581 ;
     RECT  77.868 21.541 79.47 21.631 ;
     RECT  80.244 21.389 90.882 21.631 ;
     RECT  11.628 21.581 26.442 21.695 ;
     RECT  99.504 21.533 102.294 21.695 ;
     RECT  27.396 21.389 77.13 21.703 ;
     RECT  77.868 21.631 90.882 21.703 ;
     RECT  10.332 21.155 10.71 21.839 ;
     RECT  91.692 21.389 97.002 21.929 ;
     RECT  27.396 21.703 90.882 22.171 ;
     RECT  95.364 21.929 97.002 22.171 ;
     RECT  10.692 21.839 10.71 22.199 ;
     RECT  27.288 22.171 90.882 22.207 ;
     RECT  91.692 21.929 94.626 22.207 ;
     RECT  12.24 21.695 26.442 22.243 ;
     RECT  27.288 22.207 94.626 22.243 ;
     RECT  99.615 21.695 102.294 22.253 ;
     RECT  95.364 22.171 97.434 22.351 ;
     RECT  99.615 22.253 101.322 22.441 ;
     RECT  12.24 22.243 94.626 22.711 ;
     RECT  95.364 22.351 97.974 22.711 ;
     RECT  102.276 22.253 102.294 22.711 ;
     RECT  12.24 22.711 97.974 22.783 ;
     RECT  99 22.441 101.322 22.783 ;
     RECT  12.24 22.783 101.322 22.795 ;
     RECT  11.736 22.795 101.322 22.981 ;
     RECT  102.276 22.711 102.762 22.981 ;
     RECT  11.736 22.981 102.762 23.161 ;
     RECT  11.736 23.161 102.87 23.665 ;
     RECT  103.896 23.125 103.914 23.665 ;
     RECT  10.224 23.371 10.242 23.893 ;
     RECT  5.364 23.371 5.382 23.899 ;
     RECT  11.736 23.665 103.914 23.971 ;
     RECT  5.04 23.899 5.382 23.999 ;
     RECT  9.9 23.893 10.242 23.999 ;
     RECT  9.9 23.999 9.918 24.089 ;
     RECT  11.448 23.971 103.914 24.169 ;
     RECT  6.876 21.581 8.097 24.187 ;
     RECT  8.856 24.139 8.874 24.187 ;
     RECT  11.448 24.169 104.094 24.241 ;
     RECT  6.876 24.187 8.874 24.275 ;
     RECT  5.04 23.999 5.058 24.317 ;
     RECT  6.876 24.275 8.226 24.359 ;
     RECT  11.448 24.241 104.202 24.379 ;
     RECT  6.876 24.359 8.097 24.431 ;
     RECT  10.836 24.379 104.202 24.475 ;
     RECT  10.836 24.475 104.274 24.509 ;
     RECT  105.015 20.147 105.297 24.511 ;
     RECT  105.015 24.511 105.606 24.629 ;
     RECT  11.448 24.509 104.274 24.709 ;
     RECT  105.015 24.629 105.297 24.709 ;
     RECT  11.448 24.709 105.297 24.899 ;
     RECT  16.74 24.899 105.297 24.935 ;
     RECT  10.044 25.141 10.062 25.285 ;
     RECT  16.74 24.935 84.906 25.313 ;
     RECT  10.044 25.285 10.206 25.321 ;
     RECT  11.448 24.899 16.002 25.321 ;
     RECT  10.044 25.321 16.002 25.447 ;
     RECT  9.864 25.447 16.002 25.483 ;
     RECT  5.832 25.519 5.85 25.675 ;
     RECT  9.828 25.483 16.002 25.675 ;
     RECT  7.164 24.431 8.097 25.681 ;
     RECT  9.792 25.675 16.002 25.753 ;
     RECT  7.164 25.681 8.406 25.789 ;
     RECT  9.756 25.753 16.002 25.789 ;
     RECT  7.164 25.789 16.11 25.819 ;
     RECT  5.688 25.675 5.85 26.203 ;
     RECT  4.968 26.203 5.85 26.293 ;
     RECT  6.804 25.819 16.11 26.293 ;
     RECT  16.848 25.313 84.906 26.293 ;
     RECT  85.68 24.935 105.297 26.293 ;
     RECT  4.968 26.293 16.11 26.329 ;
     RECT  16.848 26.293 105.297 26.329 ;
     RECT  4.968 26.329 105.297 26.761 ;
     RECT  4.968 26.761 105.426 26.869 ;
     RECT  4.644 26.869 105.426 26.933 ;
     RECT  5.472 26.933 105.426 27.167 ;
     RECT  4.644 26.933 4.662 27.715 ;
     RECT  5.472 27.167 105.354 27.715 ;
     RECT  4.644 27.715 105.354 27.883 ;
     RECT  4.104 27.883 105.354 27.905 ;
     RECT  4.104 27.905 105.297 28.139 ;
     RECT  4.248 28.139 105.297 28.831 ;
     RECT  4.248 28.831 105.714 29.641 ;
     RECT  4.032 29.641 105.714 29.759 ;
     RECT  4.032 29.759 105.297 30.065 ;
     RECT  4.212 30.065 105.297 30.443 ;
     RECT  4.284 30.443 105.297 30.991 ;
     RECT  4.284 30.991 105.606 31.217 ;
     RECT  3.492 31.225 3.51 31.261 ;
     RECT  4.284 31.217 105.297 31.261 ;
     RECT  2.415 21.119 2.697 31.351 ;
     RECT  3.492 31.261 105.297 31.351 ;
     RECT  2.415 31.351 105.297 33.925 ;
     RECT  2.415 33.925 105.426 33.961 ;
     RECT  107.82 33.853 107.838 34.051 ;
     RECT  107.172 34.051 107.838 34.159 ;
     RECT  2.415 33.961 105.606 34.393 ;
     RECT  2.415 34.393 106.29 35.239 ;
     RECT  107.172 34.159 107.91 35.239 ;
     RECT  2.415 35.239 107.91 35.309 ;
     RECT  2.415 35.309 107.874 35.405 ;
     RECT  2.415 35.405 107.838 35.501 ;
     RECT  2.415 35.501 107.802 35.693 ;
     RECT  2.415 35.693 107.766 35.789 ;
     RECT  2.415 35.789 107.334 36.173 ;
     RECT  2.415 36.173 107.19 36.653 ;
     RECT  2.415 36.653 107.154 37.579 ;
     RECT  107.892 37.483 107.91 37.579 ;
     RECT  2.415 37.579 107.91 38.347 ;
     RECT  2.415 38.347 107.982 38.399 ;
     RECT  2.415 38.399 4.806 38.705 ;
     RECT  4.032 38.705 4.806 38.939 ;
     RECT  4.176 38.939 4.806 39.181 ;
     RECT  5.58 38.399 107.982 39.181 ;
     RECT  4.176 39.181 107.982 39.293 ;
     RECT  97.236 39.293 107.982 39.317 ;
     RECT  4.176 39.293 96.498 39.479 ;
     RECT  4.32 39.479 96.498 39.515 ;
     RECT  4.68 39.515 96.426 39.587 ;
     RECT  107.172 39.317 107.982 39.623 ;
     RECT  4.68 39.587 96.318 39.659 ;
     RECT  97.236 39.317 106.074 39.659 ;
     RECT  5.148 39.659 5.418 39.749 ;
     RECT  97.236 39.659 105.39 39.749 ;
     RECT  97.236 39.749 99.897 39.821 ;
     RECT  107.208 39.623 107.982 39.857 ;
     RECT  100.98 39.749 105.39 39.893 ;
     RECT  5.148 39.749 5.31 40.019 ;
     RECT  6.336 39.659 96.318 40.019 ;
     RECT  107.784 39.857 107.982 40.019 ;
     RECT  5.292 40.019 5.31 40.055 ;
     RECT  6.336 40.019 8.73 40.055 ;
     RECT  97.56 39.821 99.897 40.091 ;
     RECT  6.372 40.055 8.73 40.127 ;
     RECT  97.92 40.091 99.897 40.163 ;
     RECT  98.928 40.163 99.897 40.199 ;
     RECT  9.468 40.019 96.318 40.205 ;
     RECT  6.948 40.127 8.73 40.289 ;
     RECT  9.468 40.205 86.634 40.289 ;
     RECT  101.232 39.893 105.39 40.289 ;
     RECT  87.48 40.205 96.318 40.361 ;
     RECT  91.836 40.361 96.318 40.397 ;
     RECT  98.964 40.199 99.897 40.397 ;
     RECT  101.376 40.289 105.39 40.441 ;
     RECT  6.948 40.289 8.406 40.469 ;
     RECT  9.468 40.289 80.154 40.469 ;
     RECT  80.928 40.289 86.634 40.469 ;
     RECT  88.38 40.361 91.098 40.469 ;
     RECT  101.376 40.441 105.462 40.469 ;
     RECT  7.416 40.469 8.406 40.559 ;
     RECT  9.648 40.469 80.154 40.559 ;
     RECT  101.376 40.469 103.914 40.559 ;
     RECT  104.976 40.469 105.462 40.559 ;
     RECT  91.98 40.397 96.318 40.739 ;
     RECT  80.928 40.469 84.438 40.829 ;
     RECT  107.82 40.019 107.982 40.829 ;
     RECT  9.648 40.559 9.774 41.021 ;
     RECT  85.284 40.469 86.634 41.035 ;
     RECT  87.48 40.361 87.498 41.035 ;
     RECT  101.376 40.559 102.654 41.035 ;
     RECT  10.512 40.559 80.154 41.071 ;
     RECT  80.928 40.829 84.258 41.071 ;
     RECT  107.964 40.829 107.982 41.099 ;
     RECT  105.015 40.559 105.462 41.135 ;
     RECT  85.284 41.035 87.498 41.171 ;
     RECT  92.052 40.739 96.318 41.171 ;
     RECT  88.38 40.469 89.874 41.215 ;
     RECT  86.94 41.171 87.498 41.227 ;
     RECT  88.38 41.215 89.946 41.227 ;
     RECT  85.284 41.171 86.166 41.323 ;
     RECT  91.044 40.469 91.098 41.341 ;
     RECT  85.212 41.323 86.166 41.369 ;
     RECT  86.94 41.227 89.946 41.369 ;
     RECT  9.648 41.021 9.666 41.405 ;
     RECT  101.304 41.035 102.654 41.413 ;
     RECT  101.232 41.413 102.654 41.449 ;
     RECT  88.38 41.369 89.946 41.485 ;
     RECT  101.052 41.449 102.654 41.485 ;
     RECT  10.512 41.071 84.258 41.521 ;
     RECT  10.404 41.521 84.258 41.683 ;
     RECT  10.404 41.683 84.294 41.755 ;
     RECT  88.38 41.485 90.09 41.755 ;
     RECT  88.38 41.755 90.162 41.791 ;
     RECT  99.18 40.397 99.897 41.881 ;
     RECT  100.908 41.485 102.654 41.881 ;
     RECT  10.404 41.755 84.366 41.917 ;
     RECT  96.804 41.647 96.822 41.981 ;
     RECT  88.38 41.791 90.234 41.989 ;
     RECT  91.044 41.341 91.278 41.989 ;
     RECT  97.92 40.163 97.938 42.043 ;
     RECT  10.404 41.917 84.402 42.061 ;
     RECT  85.212 41.369 85.806 42.061 ;
     RECT  10.404 42.061 85.806 42.187 ;
     RECT  86.652 41.899 86.67 42.187 ;
     RECT  87.48 41.369 87.498 42.187 ;
     RECT  10.368 42.187 85.806 42.223 ;
     RECT  86.544 42.187 87.498 42.223 ;
     RECT  92.052 41.171 96.03 42.223 ;
     RECT  97.884 42.043 97.938 42.223 ;
     RECT  10.368 42.223 87.498 42.295 ;
     RECT  88.38 41.989 91.278 42.295 ;
     RECT  10.368 42.295 91.278 42.331 ;
     RECT  92.052 42.223 96.462 42.331 ;
     RECT  97.884 42.223 98.154 42.331 ;
     RECT  97.236 42.331 98.154 42.493 ;
     RECT  99.18 41.881 102.654 42.493 ;
     RECT  97.236 42.493 102.654 42.715 ;
     RECT  10.368 42.331 96.462 42.719 ;
     RECT  97.236 42.715 103.014 42.755 ;
     RECT  97.236 42.755 102.654 42.989 ;
     RECT  10.62 42.719 96.462 43.069 ;
     RECT  97.236 42.989 102.186 43.069 ;
     RECT  10.62 43.069 102.186 43.681 ;
     RECT  10.296 43.681 102.186 43.879 ;
     RECT  10.296 43.879 103.158 43.901 ;
     RECT  10.836 43.901 103.158 43.951 ;
     RECT  10.836 43.951 103.806 44.443 ;
     RECT  10.836 44.443 103.842 44.609 ;
     RECT  10.836 44.609 103.014 44.645 ;
     RECT  103.752 44.609 103.842 44.689 ;
     RECT  103.752 44.689 104.202 44.761 ;
     RECT  105.015 41.135 105.297 44.761 ;
     RECT  10.836 44.645 102.942 45.067 ;
     RECT  10.296 45.067 102.942 45.265 ;
     RECT  7.815 40.559 8.097 45.301 ;
     RECT  9.72 45.265 102.942 45.427 ;
     RECT  9.108 45.427 102.942 45.535 ;
     RECT  5.94 45.391 6.426 45.571 ;
     RECT  7.2 45.301 8.097 45.661 ;
     RECT  8.928 45.535 102.942 45.733 ;
     RECT  103.752 44.761 105.297 45.733 ;
     RECT  8.928 45.733 105.297 45.773 ;
     RECT  5.328 45.571 6.426 45.805 ;
     RECT  7.2 45.661 8.154 45.805 ;
     RECT  5.328 45.805 8.154 46.003 ;
     RECT  8.928 45.773 70.362 46.003 ;
     RECT  5.328 46.003 70.362 46.541 ;
     RECT  12.708 46.541 70.362 46.615 ;
     RECT  71.136 45.773 105.297 46.615 ;
     RECT  12.708 46.615 105.297 46.651 ;
     RECT  12.708 46.651 105.354 46.913 ;
     RECT  14.508 46.913 105.354 46.949 ;
     RECT  5.328 46.541 11.97 47.425 ;
     RECT  12.708 46.913 13.698 47.425 ;
     RECT  14.544 46.949 105.354 47.461 ;
     RECT  14.544 47.461 105.462 47.579 ;
     RECT  14.544 47.579 105.297 47.615 ;
     RECT  4.788 47.425 13.698 47.731 ;
     RECT  14.544 47.615 31.986 47.731 ;
     RECT  4.788 47.731 31.986 47.849 ;
     RECT  4.788 47.849 4.806 47.857 ;
     RECT  4.716 47.857 4.806 47.929 ;
     RECT  14.508 47.849 31.986 48.119 ;
     RECT  4.464 47.929 4.806 48.235 ;
     RECT  4.428 48.235 4.806 48.271 ;
     RECT  15.372 48.119 31.986 48.361 ;
     RECT  4.284 48.271 4.806 48.631 ;
     RECT  32.796 47.615 105.297 48.659 ;
     RECT  15.372 48.361 32.022 48.667 ;
     RECT  32.796 48.659 33.174 48.667 ;
     RECT  4.284 48.631 4.95 48.703 ;
     RECT  5.724 47.849 13.77 48.703 ;
     RECT  14.508 48.119 14.634 48.703 ;
     RECT  4.284 48.703 14.634 48.929 ;
     RECT  4.284 48.929 13.842 48.941 ;
     RECT  4.284 48.941 13.662 48.973 ;
     RECT  15.372 48.667 33.174 49.003 ;
     RECT  14.688 49.003 33.174 49.271 ;
     RECT  32.58 49.271 33.174 49.379 ;
     RECT  32.976 49.379 33.174 49.441 ;
     RECT  33.912 48.659 105.297 49.441 ;
     RECT  14.688 49.271 31.482 49.469 ;
     RECT  4.176 48.973 13.662 49.505 ;
     RECT  14.688 49.469 16.794 49.855 ;
     RECT  4.176 49.505 13.554 49.891 ;
     RECT  3.96 49.891 13.554 50.045 ;
     RECT  14.472 49.855 16.794 50.089 ;
     RECT  32.976 49.441 105.297 50.107 ;
     RECT  17.676 49.469 31.482 50.161 ;
     RECT  32.76 50.107 105.297 50.161 ;
     RECT  17.676 50.161 105.297 50.189 ;
     RECT  4.032 50.045 13.554 50.359 ;
     RECT  14.292 50.089 16.794 50.359 ;
     RECT  17.676 50.189 51.714 50.359 ;
     RECT  4.032 50.359 51.714 50.863 ;
     RECT  3.78 50.863 51.714 50.935 ;
     RECT  52.452 50.189 105.297 50.935 ;
     RECT  3.744 50.935 105.297 51.269 ;
     RECT  11.952 51.269 105.297 51.437 ;
     RECT  11.988 51.437 105.297 51.467 ;
     RECT  3.744 51.269 11.214 51.899 ;
     RECT  64.656 51.467 105.297 52.051 ;
     RECT  3.744 51.899 11.178 52.141 ;
     RECT  11.988 51.467 63.882 52.241 ;
     RECT  44.424 52.241 63.882 52.249 ;
     RECT  64.656 52.051 105.426 52.249 ;
     RECT  44.424 52.249 105.426 52.313 ;
     RECT  2.415 38.705 2.697 52.321 ;
     RECT  2.415 52.321 2.898 52.411 ;
     RECT  3.636 52.141 11.178 52.411 ;
     RECT  11.988 52.241 43.542 52.439 ;
     RECT  20.268 52.439 43.542 52.511 ;
     RECT  11.988 52.439 19.53 52.555 ;
     RECT  20.268 52.511 20.358 52.583 ;
     RECT  20.34 52.583 20.358 52.709 ;
     RECT  2.415 52.411 11.178 52.717 ;
     RECT  11.916 52.555 19.53 52.717 ;
     RECT  21.096 52.511 43.542 52.981 ;
     RECT  44.424 52.313 105.297 52.981 ;
     RECT  2.415 52.717 19.53 53.249 ;
     RECT  21.096 52.981 105.297 53.275 ;
     RECT  3.708 53.249 19.53 53.285 ;
     RECT  3.888 53.285 19.53 53.321 ;
     RECT  4.068 53.321 19.53 53.365 ;
     RECT  4.068 53.365 19.746 53.519 ;
     RECT  4.248 53.519 19.746 53.563 ;
     RECT  4.248 53.563 19.854 53.597 ;
     RECT  4.644 53.597 19.854 53.671 ;
     RECT  20.736 53.275 105.297 53.671 ;
     RECT  4.644 53.671 105.297 53.789 ;
     RECT  5.004 53.789 5.382 54.059 ;
     RECT  6.264 53.789 105.297 54.059 ;
     RECT  5.364 54.059 5.382 54.131 ;
     RECT  6.264 54.059 97.938 54.131 ;
     RECT  6.264 54.131 47.718 54.635 ;
     RECT  48.456 54.131 97.938 54.635 ;
     RECT  52.128 54.635 97.938 54.653 ;
     RECT  6.768 54.635 47.718 54.671 ;
     RECT  48.456 54.635 51.297 54.859 ;
     RECT  6.768 54.671 47.322 54.869 ;
     RECT  52.272 54.653 97.938 54.893 ;
     RECT  48.204 54.859 51.297 54.905 ;
     RECT  58.896 54.893 97.938 54.913 ;
     RECT  98.712 54.059 105.297 54.913 ;
     RECT  48.456 54.905 51.297 55.013 ;
     RECT  6.768 54.869 8.838 55.049 ;
     RECT  52.272 54.893 57.978 55.049 ;
     RECT  58.896 54.913 105.297 55.049 ;
     RECT  6.768 55.049 8.478 55.139 ;
     RECT  48.456 55.013 49.734 55.139 ;
     RECT  50.472 55.013 51.297 55.139 ;
     RECT  52.272 55.049 53.658 55.139 ;
     RECT  48.456 55.139 48.51 55.175 ;
     RECT  54.396 55.049 57.978 55.277 ;
     RECT  50.652 55.139 51.297 55.283 ;
     RECT  9.612 54.869 47.322 55.409 ;
     RECT  54.396 55.277 55.458 55.409 ;
     RECT  52.992 55.139 53.658 55.445 ;
     RECT  10.116 55.409 11.61 55.481 ;
     RECT  10.836 55.481 11.61 55.517 ;
     RECT  12.564 55.409 47.322 55.517 ;
     RECT  6.768 55.139 8.097 55.589 ;
     RECT  10.836 55.517 11.502 55.589 ;
     RECT  13.215 55.517 47.322 55.589 ;
     RECT  48.456 55.175 48.474 55.589 ;
     RECT  6.768 55.589 6.786 55.679 ;
     RECT  13.215 55.589 46.998 55.679 ;
     RECT  49.284 55.139 49.734 55.679 ;
     RECT  53.568 55.445 53.658 55.679 ;
     RECT  54.396 55.409 54.846 55.679 ;
     RECT  13.215 55.679 46.782 55.715 ;
     RECT  53.568 55.679 53.586 55.715 ;
     RECT  49.716 55.679 49.734 55.751 ;
     RECT  13.215 55.715 15.39 55.823 ;
     RECT  56.415 55.277 57.978 55.831 ;
     RECT  58.932 55.049 105.297 55.831 ;
     RECT  56.415 55.831 105.297 55.859 ;
     RECT  14.22 55.823 15.39 55.949 ;
     RECT  16.344 55.715 46.782 55.949 ;
     RECT  54.396 55.679 54.45 55.985 ;
     RECT  57.924 55.859 105.297 55.985 ;
     RECT  54.396 55.985 54.414 56.057 ;
     RECT  57.924 55.985 59.814 56.219 ;
     RECT  58.68 56.219 59.814 56.255 ;
     RECT  18.216 55.949 46.782 56.327 ;
     RECT  18.252 56.327 46.782 56.363 ;
     RECT  57.924 56.219 57.942 56.381 ;
     RECT  18.252 56.363 45.897 56.399 ;
     RECT  46.728 56.363 46.782 56.399 ;
     RECT  18.252 56.399 44.622 56.489 ;
     RECT  60.588 55.985 69.318 56.489 ;
     RECT  14.796 55.949 15.39 56.525 ;
     RECT  58.716 56.255 59.814 56.525 ;
     RECT  16.344 55.949 17.334 56.605 ;
     RECT  59.58 56.525 59.814 56.633 ;
     RECT  27.72 56.489 44.622 56.669 ;
     RECT  15.156 56.525 15.39 56.759 ;
     RECT  16.164 56.605 17.334 56.759 ;
     RECT  27.72 56.669 44.046 56.759 ;
     RECT  61.452 56.489 69.318 56.759 ;
     RECT  61.704 56.759 69.318 56.767 ;
     RECT  70.308 55.985 105.297 56.767 ;
     RECT  15.156 56.759 15.174 56.795 ;
     RECT  17.316 56.759 17.334 56.795 ;
     RECT  28.152 56.759 44.046 56.795 ;
     RECT  59.652 56.633 59.814 56.795 ;
     RECT  60.588 56.489 60.606 56.813 ;
     RECT  18.252 56.489 26.91 56.831 ;
     RECT  61.704 56.767 105.297 56.831 ;
     RECT  18.504 56.831 26.91 56.867 ;
     RECT  28.188 56.795 44.046 56.867 ;
     RECT  59.652 56.795 59.742 56.867 ;
     RECT  28.188 56.867 43.434 56.903 ;
     RECT  63.864 56.831 105.297 56.903 ;
     RECT  18.504 56.867 19.674 56.939 ;
     RECT  59.724 56.867 59.742 56.939 ;
     RECT  61.815 56.831 62.874 57.029 ;
     RECT  37.728 56.903 43.182 57.065 ;
     RECT  63.864 56.903 89.514 57.065 ;
     RECT  46.764 56.399 46.782 57.101 ;
     RECT  63.864 57.065 63.882 57.137 ;
     RECT  20.52 56.867 26.91 57.173 ;
     RECT  62.856 57.029 62.874 57.173 ;
     RECT  45.615 56.399 45.897 57.181 ;
     RECT  20.52 57.173 26.838 57.209 ;
     RECT  28.188 56.903 36.882 57.209 ;
     RECT  19.656 56.939 19.674 57.299 ;
     RECT  28.476 57.209 36.882 57.299 ;
     RECT  64.692 57.065 89.514 57.299 ;
     RECT  18.504 56.939 18.897 57.335 ;
     RECT  37.728 57.065 42.93 57.335 ;
     RECT  90.252 56.903 105.297 57.335 ;
     RECT  28.476 57.299 36.81 57.371 ;
     RECT  23.724 57.209 26.838 57.407 ;
     RECT  37.728 57.335 42.21 57.407 ;
     RECT  42.192 57.407 42.21 57.443 ;
     RECT  28.476 57.371 36.126 57.479 ;
     RECT  45.615 57.181 46.53 57.479 ;
     RECT  20.52 57.209 22.914 57.569 ;
     RECT  29.304 57.479 36.126 57.569 ;
     RECT  39.06 57.407 40.878 57.569 ;
     RECT  65.196 57.299 89.514 57.569 ;
     RECT  29.415 57.569 35.097 57.605 ;
     RECT  37.728 57.407 38.25 57.605 ;
     RECT  39.06 57.569 40.497 57.605 ;
     RECT  65.628 57.569 89.514 57.605 ;
     RECT  29.415 57.605 32.886 57.641 ;
     RECT  35.82 57.569 36.126 57.641 ;
     RECT  38.232 57.605 38.25 57.641 ;
     RECT  39.528 57.605 40.497 57.641 ;
     RECT  65.628 57.605 65.646 57.641 ;
     RECT  21.06 57.569 22.302 57.677 ;
     RECT  39.78 57.641 40.497 57.677 ;
     RECT  68.328 57.605 89.514 57.683 ;
     RECT  68.364 57.683 89.514 57.685 ;
     RECT  90.252 57.335 103.77 57.685 ;
     RECT  32.868 57.641 32.886 57.713 ;
     RECT  33.624 57.605 35.097 57.713 ;
     RECT  29.415 57.641 31.914 57.749 ;
     RECT  21.24 57.677 22.302 57.839 ;
     RECT  29.415 57.749 31.878 57.839 ;
     RECT  68.364 57.685 103.77 57.839 ;
     RECT  21.852 57.839 22.302 57.875 ;
     RECT  68.364 57.839 69.246 57.875 ;
     RECT  70.056 57.839 103.77 57.875 ;
     RECT  31.212 57.839 31.878 57.911 ;
     RECT  22.032 57.875 22.302 57.947 ;
     RECT  29.415 57.839 30.222 57.947 ;
     RECT  23.976 57.407 26.838 57.991 ;
     RECT  22.032 57.947 22.05 58.019 ;
     RECT  70.092 57.875 103.77 58.019 ;
     RECT  23.976 57.991 27.09 58.109 ;
     RECT  31.212 57.911 31.446 58.109 ;
     RECT  69.084 57.875 69.246 58.109 ;
     RECT  70.092 58.019 70.362 58.109 ;
     RECT  23.976 58.109 25.038 58.145 ;
     RECT  29.415 57.947 30.186 58.145 ;
     RECT  31.212 58.109 31.23 58.145 ;
     RECT  69.228 58.109 69.246 58.145 ;
     RECT  70.344 58.109 70.362 58.145 ;
     RECT  71.208 58.019 103.77 58.145 ;
     RECT  71.316 58.145 73.026 58.157 ;
     RECT  24.015 58.145 24.93 58.181 ;
     RECT  24.015 58.181 24.354 58.217 ;
     RECT  29.415 58.145 29.934 58.217 ;
     RECT  73.8 58.145 103.77 58.289 ;
     RECT  26.172 58.109 26.802 58.379 ;
     RECT  71.316 58.157 72.897 58.379 ;
     RECT  73.8 58.289 76.158 58.379 ;
     RECT  71.784 58.379 72.897 58.415 ;
     RECT  74.088 58.379 75.87 58.415 ;
     RECT  77.148 58.289 103.77 58.415 ;
     RECT  28.476 57.479 28.494 58.451 ;
     RECT  71.784 58.415 71.802 58.451 ;
     RECT  74.088 58.415 75.258 58.451 ;
     RECT  77.148 58.415 77.166 58.451 ;
     RECT  74.124 58.451 75.078 58.487 ;
     RECT  26.784 58.379 26.802 58.559 ;
     RECT  78.015 58.415 103.77 58.559 ;
     RECT  78.015 58.559 85.374 58.649 ;
     RECT  79.128 58.649 79.29 58.685 ;
     RECT  86.148 58.559 103.158 58.757 ;
     RECT  86.148 58.757 100.17 58.781 ;
     RECT  86.148 58.781 99.897 58.829 ;
     RECT  78.015 58.649 78.354 58.919 ;
     RECT  79.128 58.685 79.146 58.919 ;
     RECT  80.172 58.649 85.374 58.919 ;
     RECT  86.148 58.829 86.346 58.919 ;
     RECT  87.084 58.829 99.897 58.919 ;
     RECT  74.124 58.487 75.006 58.955 ;
     RECT  80.172 58.919 80.19 58.955 ;
     RECT  80.928 58.919 85.302 58.955 ;
     RECT  86.148 58.919 86.166 58.955 ;
     RECT  98.712 58.919 99.897 58.955 ;
     RECT  101.232 58.757 103.158 58.955 ;
     RECT  87.084 58.919 96.066 59.027 ;
     RECT  101.664 58.955 103.158 59.027 ;
     RECT  96.804 58.919 97.902 59.063 ;
     RECT  74.124 58.955 74.826 59.099 ;
     RECT  87.084 59.027 87.318 59.099 ;
     RECT  88.488 59.027 96.066 59.099 ;
     RECT  80.928 58.955 85.194 59.189 ;
     RECT  87.084 59.099 87.138 59.189 ;
     RECT  96.804 59.063 97.002 59.189 ;
     RECT  102.996 59.027 103.158 59.189 ;
     RECT  80.928 59.189 80.946 59.225 ;
     RECT  81.684 59.189 85.194 59.225 ;
     RECT  87.12 59.189 87.138 59.225 ;
     RECT  88.56 59.099 95.742 59.225 ;
     RECT  96.804 59.189 96.966 59.225 ;
     RECT  102.996 59.189 103.014 59.225 ;
     RECT  92.34 59.225 95.742 59.261 ;
     RECT  99.252 58.955 99.897 59.261 ;
     RECT  81.684 59.225 81.81 59.369 ;
     RECT  84.924 59.225 85.194 59.369 ;
     RECT  96.948 59.225 96.966 59.369 ;
     RECT  81.684 59.369 81.774 59.459 ;
     RECT  88.56 59.225 91.242 59.459 ;
     RECT  92.34 59.261 93.258 59.459 ;
     RECT  81.684 59.459 81.702 59.495 ;
     RECT  84.924 59.369 85.086 59.495 ;
     RECT  88.815 59.459 91.242 59.495 ;
     RECT  94.068 59.261 95.13 59.495 ;
     RECT  101.664 59.027 101.934 59.495 ;
     RECT  82.8 59.225 83.697 59.567 ;
     RECT  84.924 59.495 84.942 59.567 ;
     RECT  101.664 59.495 101.682 59.567 ;
     RECT  94.068 59.495 94.497 59.639 ;
     RECT  88.815 59.495 89.694 59.729 ;
     RECT  91.008 59.495 91.242 59.729 ;
     RECT  92.34 59.459 92.934 59.729 ;
     RECT  88.815 59.729 89.478 59.765 ;
     RECT  91.008 59.729 91.026 59.765 ;
     RECT  92.916 59.729 92.934 59.801 ;
     RECT  2.415 53.249 2.697 62.387 ;
     RECT  7.815 55.589 8.097 62.387 ;
     RECT  13.215 55.823 13.497 62.387 ;
     RECT  18.615 57.335 18.897 62.387 ;
     RECT  24.015 58.217 24.297 62.387 ;
     RECT  29.415 58.217 29.697 62.387 ;
     RECT  34.815 57.713 35.097 62.387 ;
     RECT  40.215 57.677 40.497 62.387 ;
     RECT  45.615 57.479 45.897 62.387 ;
     RECT  51.015 55.283 51.297 62.387 ;
     RECT  56.415 55.859 56.697 62.387 ;
     RECT  61.815 57.029 62.097 62.387 ;
     RECT  67.215 57.605 67.497 62.387 ;
     RECT  72.615 58.415 72.897 62.387 ;
     RECT  78.015 58.919 78.297 62.387 ;
     RECT  83.415 59.567 83.697 62.387 ;
     RECT  88.815 59.765 89.097 62.387 ;
     RECT  94.215 59.639 94.497 62.387 ;
     RECT  99.615 59.261 99.897 62.387 ;
     RECT  105.015 57.335 105.297 62.387 ;
     RECT  2.415 62.387 2.505 62.657 ;
     RECT  7.815 62.387 7.905 62.657 ;
     RECT  13.215 62.387 13.305 62.657 ;
     RECT  18.615 62.387 18.705 62.657 ;
     RECT  24.015 62.387 24.105 62.657 ;
     RECT  29.415 62.387 29.505 62.657 ;
     RECT  34.815 62.387 34.905 62.657 ;
     RECT  40.215 62.387 40.305 62.657 ;
     RECT  45.615 62.387 45.705 62.657 ;
     RECT  51.015 62.387 51.105 62.657 ;
     RECT  56.415 62.387 56.505 62.657 ;
     RECT  61.815 62.387 61.905 62.657 ;
     RECT  67.215 62.387 67.305 62.657 ;
     RECT  72.615 62.387 72.705 62.657 ;
     RECT  78.015 62.387 78.105 62.657 ;
     RECT  83.415 62.387 83.505 62.657 ;
     RECT  88.815 62.387 88.905 62.657 ;
     RECT  94.215 62.387 94.305 62.657 ;
     RECT  99.615 62.387 99.705 62.657 ;
     RECT  105.015 62.387 105.105 62.657 ;
    LAYER M4 ;
     RECT  2.408 2.148 2.512 62.652 ;
     RECT  2.512 2.418 2.704 62.382 ;
     RECT  2.704 52.416 3.089 53.016 ;
     RECT  2.704 36.624 3.521 37.032 ;
     RECT  2.704 31.248 3.539 32.472 ;
     RECT  2.704 19.392 3.697 19.416 ;
     RECT  2.704 35.328 3.733 35.352 ;
     RECT  3.697 19.392 3.737 19.512 ;
     RECT  2.704 12.528 3.769 13.32 ;
     RECT  2.704 17.04 3.769 17.064 ;
     RECT  3.769 17.04 3.949 17.496 ;
     RECT  2.704 38.16 4.021 38.184 ;
     RECT  3.949 16.656 4.129 17.496 ;
     RECT  2.704 20.64 4.169 21.144 ;
     RECT  3.769 12.528 4.205 13.992 ;
     RECT  3.877 51.696 4.237 51.72 ;
     RECT  3.089 52.896 4.237 53.016 ;
     RECT  2.704 33.552 4.261 33.576 ;
     RECT  4.261 33.552 4.307 34.152 ;
     RECT  3.733 35.328 4.345 35.592 ;
     RECT  3.521 36.624 4.345 36.648 ;
     RECT  4.307 34.128 4.348 34.152 ;
     RECT  4.309 50.064 4.597 50.088 ;
     RECT  3.737 19.488 4.633 19.512 ;
     RECT  4.169 20.64 4.633 20.76 ;
     RECT  4.633 19.488 4.705 20.76 ;
     RECT  3.539 31.392 4.741 31.416 ;
     RECT  3.539 32.448 4.741 32.472 ;
     RECT  2.704 15.36 4.748 15.384 ;
     RECT  4.129 16.656 4.748 18.408 ;
     RECT  4.021 38.16 4.796 38.808 ;
     RECT  4.748 15.36 4.813 18.408 ;
     RECT  4.705 19.392 4.813 20.76 ;
     RECT  4.237 51.408 4.885 51.72 ;
     RECT  4.837 34.32 4.921 34.344 ;
     RECT  4.345 35.328 4.921 36.648 ;
     RECT  4.921 34.32 4.924 36.648 ;
     RECT  4.885 51.072 4.957 51.72 ;
     RECT  3.913 11.424 4.981 11.448 ;
     RECT  4.741 31.392 4.993 32.472 ;
     RECT  4.957 51.072 4.993 51.768 ;
     RECT  4.237 52.896 4.993 53.592 ;
     RECT  4.813 15.36 4.997 20.76 ;
     RECT  4.981 24.288 5.029 24.312 ;
     RECT  4.993 31.344 5.029 32.472 ;
     RECT  4.796 38.112 5.029 38.808 ;
     RECT  4.957 26.208 5.041 26.232 ;
     RECT  4.981 10.944 5.065 11.448 ;
     RECT  4.993 51.072 5.065 53.592 ;
     RECT  5.029 23.904 5.069 24.312 ;
     RECT  4.924 34.368 5.077 36.648 ;
     RECT  5.029 37.632 5.077 38.808 ;
     RECT  5.065 10.56 5.269 11.448 ;
     RECT  4.205 12.528 5.269 13.8 ;
     RECT  5.269 10.56 5.281 13.8 ;
     RECT  4.997 15.36 5.281 17.064 ;
     RECT  4.997 18.192 5.353 20.76 ;
     RECT  5.069 23.904 5.353 24.264 ;
     RECT  5.029 30.72 5.353 32.472 ;
     RECT  5.281 10.56 5.357 17.064 ;
     RECT  5.077 34.368 5.389 38.808 ;
     RECT  4.093 27.888 5.468 27.912 ;
     RECT  5.353 18.192 5.573 21.096 ;
     RECT  4.597 49.248 5.605 50.088 ;
     RECT  5.065 51.072 5.605 53.784 ;
     RECT  5.573 19.2 5.653 21.096 ;
     RECT  5.353 23.376 5.699 24.264 ;
     RECT  5.653 25.68 5.74 25.848 ;
     RECT  5.389 34.368 5.753 39.384 ;
     RECT  5.573 18.192 5.825 18.216 ;
     RECT  5.468 27.216 5.941 27.912 ;
     RECT  5.353 30.432 5.941 32.472 ;
     RECT  5.357 12.528 5.965 17.064 ;
     RECT  5.605 49.248 6.073 53.784 ;
     RECT  6.073 49.152 6.109 53.784 ;
     RECT  5.653 19.2 6.113 21.576 ;
     RECT  5.941 27.216 6.145 32.568 ;
     RECT  5.753 34.368 6.145 39.096 ;
     RECT  5.357 10.56 6.277 11.448 ;
     RECT  6.109 48.96 6.293 53.784 ;
     RECT  5.74 25.824 6.397 25.848 ;
     RECT  6.145 27.216 6.397 39.096 ;
     RECT  5.965 12.528 6.437 18.072 ;
     RECT  6.277 9.648 6.473 11.448 ;
     RECT  6.293 48.96 6.577 53.592 ;
     RECT  6.473 9.792 6.613 11.448 ;
     RECT  6.437 12.528 6.613 17.928 ;
     RECT  6.397 25.824 6.757 39.096 ;
     RECT  6.757 25.824 6.764 39.144 ;
     RECT  6.113 20.112 6.797 21.576 ;
     RECT  6.764 25.824 6.805 39.336 ;
     RECT  6.805 25.824 6.833 39.96 ;
     RECT  6.797 20.112 7.153 21.192 ;
     RECT  5.699 24.24 7.297 24.264 ;
     RECT  6.577 48.144 7.333 53.592 ;
     RECT  7.333 48.144 7.369 53.928 ;
     RECT  6.613 9.792 7.549 17.928 ;
     RECT  4.981 7.392 7.621 7.416 ;
     RECT  7.369 48.144 7.657 54.648 ;
     RECT  7.297 24.192 7.693 24.264 ;
     RECT  7.549 9.792 7.729 18.024 ;
     RECT  7.621 7.392 7.808 7.992 ;
     RECT  7.729 9.072 7.808 18.024 ;
     RECT  7.153 19.344 7.808 21.192 ;
     RECT  7.693 24.144 7.808 24.264 ;
     RECT  6.833 25.824 7.808 27.672 ;
     RECT  6.833 28.752 7.808 39.96 ;
     RECT  7.369 45.552 7.808 45.72 ;
     RECT  7.657 48.144 7.808 54.888 ;
     RECT  7.808 2.148 7.912 62.652 ;
     RECT  7.912 2.418 8.104 62.382 ;
     RECT  8.104 7.392 8.243 21.192 ;
     RECT  8.104 25.824 8.525 39 ;
     RECT  8.243 9.024 8.561 16.008 ;
     RECT  8.561 10.416 8.668 16.008 ;
     RECT  8.243 17.088 8.669 21.192 ;
     RECT  8.525 25.824 8.813 32.232 ;
     RECT  8.668 10.416 8.885 11.496 ;
     RECT  8.104 24.144 8.885 24.504 ;
     RECT  8.885 10.416 8.921 11.4 ;
     RECT  8.921 10.416 8.957 11.208 ;
     RECT  8.668 12.528 8.957 16.008 ;
     RECT  8.525 33.312 9.068 39 ;
     RECT  8.104 46.848 9.101 54.888 ;
     RECT  9.068 33.312 9.109 39.288 ;
     RECT  8.104 40.416 9.109 40.44 ;
     RECT  9.109 33.312 9.245 40.44 ;
     RECT  8.957 10.416 9.281 11.112 ;
     RECT  9.245 33.312 9.281 34.008 ;
     RECT  8.669 17.088 9.425 18.84 ;
     RECT  9.245 35.04 9.497 40.44 ;
     RECT  9.281 10.416 9.533 10.68 ;
     RECT  8.813 26.112 9.565 32.232 ;
     RECT  8.104 45.552 9.637 45.576 ;
     RECT  9.565 26.112 9.641 32.28 ;
     RECT  9.533 10.416 9.713 10.632 ;
     RECT  9.641 31.2 9.749 32.28 ;
     RECT  9.641 26.112 9.781 29.64 ;
     RECT  8.669 20.256 9.785 21.192 ;
     RECT  9.281 33.984 9.785 34.008 ;
     RECT  9.637 40.992 9.785 41.016 ;
     RECT  9.781 25.68 9.817 29.64 ;
     RECT  8.885 24.24 9.877 24.504 ;
     RECT  9.877 23.904 9.964 24.504 ;
     RECT  9.673 1.728 9.97 1.752 ;
     RECT  9.97 1.728 10.105 1.8 ;
     RECT  8.104 3.408 10.109 3.432 ;
     RECT  9.749 31.392 10.141 32.28 ;
     RECT  10.105 1.152 10.189 1.8 ;
     RECT  9.637 45.552 10.213 46.296 ;
     RECT  10.141 31.392 10.253 32.328 ;
     RECT  10.189 1.632 10.285 1.8 ;
     RECT  9.817 25.488 10.325 29.64 ;
     RECT  10.253 31.392 10.325 32.28 ;
     RECT  9.421 4.512 10.361 4.536 ;
     RECT  9.101 47.856 10.465 54.888 ;
     RECT  8.957 13.008 10.529 16.008 ;
     RECT  10.285 1.632 10.537 2.28 ;
     RECT  8.243 7.392 10.537 7.992 ;
     RECT  8.561 9.024 10.537 9.24 ;
     RECT  10.537 7.392 10.549 9.24 ;
     RECT  10.549 7.296 10.573 9.24 ;
     RECT  9.713 10.416 10.573 10.44 ;
     RECT  9.497 35.04 10.604 39.768 ;
     RECT  10.285 43.872 10.609 43.896 ;
     RECT  10.529 12.528 10.613 16.008 ;
     RECT  10.537 1.632 10.643 2.856 ;
     RECT  10.573 7.296 10.681 10.44 ;
     RECT  9.425 17.76 10.753 18.84 ;
     RECT  9.785 20.304 10.753 21.192 ;
     RECT  10.325 31.392 10.753 32.232 ;
     RECT  10.393 33.6 10.753 33.624 ;
     RECT  10.753 33.6 10.789 33.816 ;
     RECT  10.609 43.248 10.825 43.896 ;
     RECT  10.213 45.024 10.825 46.296 ;
     RECT  10.357 42.192 10.837 42.216 ;
     RECT  9.964 24.384 10.865 24.504 ;
     RECT  10.604 35.04 10.892 40.248 ;
     RECT  10.837 41.616 10.892 42.216 ;
     RECT  10.613 13.296 10.901 16.008 ;
     RECT  10.465 47.472 10.901 54.888 ;
     RECT  10.892 35.04 10.979 42.216 ;
     RECT  10.789 33.6 11.077 34.008 ;
     RECT  10.979 35.04 11.077 39.912 ;
     RECT  10.681 7.296 11.149 11.352 ;
     RECT  11.077 33.6 11.171 39.912 ;
     RECT  10.901 51.744 11.189 54.888 ;
     RECT  10.753 17.76 11.221 21.192 ;
     RECT  10.249 5.616 11.293 5.64 ;
     RECT  10.643 1.728 11.329 2.856 ;
     RECT  10.753 31.296 11.329 32.232 ;
     RECT  11.329 31.152 11.365 32.232 ;
     RECT  11.171 33.6 11.365 34.008 ;
     RECT  11.221 16.992 11.411 21.192 ;
     RECT  11.329 1.728 11.413 3.096 ;
     RECT  10.325 26.064 11.413 29.64 ;
     RECT  11.413 25.632 11.441 29.64 ;
     RECT  11.411 19.92 11.459 21.192 ;
     RECT  10.789 0.096 11.461 0.12 ;
     RECT  11.459 20.256 11.545 21.192 ;
     RECT  11.461 0.096 11.557 0.168 ;
     RECT  11.293 5.52 11.617 5.64 ;
     RECT  11.411 17.616 11.621 18.792 ;
     RECT  11.441 25.632 11.621 29.592 ;
     RECT  10.979 41.424 11.653 42.216 ;
     RECT  10.825 43.248 11.653 46.488 ;
     RECT  11.189 51.744 11.657 54.072 ;
     RECT  10.213 23.376 11.681 23.4 ;
     RECT  11.149 7.296 11.689 11.832 ;
     RECT  10.901 47.472 11.729 50.664 ;
     RECT  11.653 41.424 11.761 46.488 ;
     RECT  11.681 22.8 11.765 23.4 ;
     RECT  11.617 5.232 11.941 5.64 ;
     RECT  11.729 47.904 11.941 50.664 ;
     RECT  11.657 51.744 11.941 52.488 ;
     RECT  11.761 41.424 11.987 46.872 ;
     RECT  11.557 0.096 12.013 0.6 ;
     RECT  11.413 1.728 12.013 2.28 ;
     RECT  11.987 41.424 12.053 42.6 ;
     RECT  11.987 43.776 12.053 46.872 ;
     RECT  10.901 13.296 12.085 13.896 ;
     RECT  10.901 14.928 12.092 16.008 ;
     RECT  12.013 0.096 12.179 2.28 ;
     RECT  12.092 14.928 12.193 16.44 ;
     RECT  11.657 53.472 12.193 54.072 ;
     RECT  12.037 3.408 12.197 3.432 ;
     RECT  11.941 4.944 12.229 5.64 ;
     RECT  11.689 7.296 12.229 11.928 ;
     RECT  12.085 13.056 12.229 13.896 ;
     RECT  11.941 47.904 12.233 52.488 ;
     RECT  11.365 30.672 12.284 34.008 ;
     RECT  11.171 35.04 12.284 39.912 ;
     RECT  11.545 20.256 12.445 21.576 ;
     RECT  12.179 0.096 12.485 0.264 ;
     RECT  12.229 7.296 12.517 13.896 ;
     RECT  12.193 14.88 12.517 16.44 ;
     RECT  12.284 30.672 12.553 39.912 ;
     RECT  12.445 20.064 12.589 21.576 ;
     RECT  12.553 30.672 12.589 40.056 ;
     RECT  12.053 41.424 12.589 42.312 ;
     RECT  11.621 17.616 12.697 18.744 ;
     RECT  12.589 20.064 12.697 22.056 ;
     RECT  12.229 4.944 12.853 5.688 ;
     RECT  10.865 24.384 12.877 24.408 ;
     RECT  11.621 25.776 12.877 29.592 ;
     RECT  12.179 1.728 12.881 2.28 ;
     RECT  12.517 7.296 12.901 16.44 ;
     RECT  12.697 17.616 12.901 22.056 ;
     RECT  12.881 1.824 12.947 2.28 ;
     RECT  12.053 43.776 12.949 43.8 ;
     RECT  12.233 51.888 12.956 52.488 ;
     RECT  12.193 53.472 12.956 54.744 ;
     RECT  12.589 30.672 13.021 42.312 ;
     RECT  12.949 43.296 13.021 43.8 ;
     RECT  12.053 44.88 13.021 46.872 ;
     RECT  12.485 0.096 13.025 0.12 ;
     RECT  12.853 4.512 13.045 5.688 ;
     RECT  12.947 2.148 13.057 2.28 ;
     RECT  12.877 24.384 13.057 29.592 ;
     RECT  13.021 30.672 13.093 46.872 ;
     RECT  12.233 47.904 13.093 50.76 ;
     RECT  13.057 2.148 13.208 2.808 ;
     RECT  13.045 4.416 13.208 5.688 ;
     RECT  12.901 6.672 13.208 22.056 ;
     RECT  11.765 23.136 13.208 23.16 ;
     RECT  13.057 24.384 13.208 29.64 ;
     RECT  13.093 30.672 13.208 50.76 ;
     RECT  12.956 51.888 13.208 54.744 ;
     RECT  13.208 2.148 13.312 62.652 ;
     RECT  13.312 2.418 13.504 62.382 ;
     RECT  13.504 13.68 13.565 24.408 ;
     RECT  13.504 51.36 13.565 52.296 ;
     RECT  13.504 44.64 13.601 46.872 ;
     RECT  13.601 44.64 13.619 46.824 ;
     RECT  13.504 4.416 13.709 4.44 ;
     RECT  13.565 13.68 13.781 18.744 ;
     RECT  13.504 48.912 13.853 50.136 ;
     RECT  13.504 7.824 13.997 11.448 ;
     RECT  13.504 2.784 14.141 2.904 ;
     RECT  13.997 9.12 14.195 11.448 ;
     RECT  13.997 7.824 14.249 7.944 ;
     RECT  14.249 7.872 14.284 7.944 ;
     RECT  13.781 13.872 14.285 18.744 ;
     RECT  14.195 9.12 14.393 11.064 ;
     RECT  13.504 33.072 14.492 43.32 ;
     RECT  13.619 44.64 14.492 45.288 ;
     RECT  13.504 25.536 14.569 32.088 ;
     RECT  14.492 33.072 14.569 45.288 ;
     RECT  13.565 19.824 14.605 24.408 ;
     RECT  14.569 25.536 14.605 45.288 ;
     RECT  14.285 16.512 14.641 18.744 ;
     RECT  14.605 19.824 14.641 45.288 ;
     RECT  13.619 46.32 14.641 46.536 ;
     RECT  13.504 53.664 14.677 55.128 ;
     RECT  14.641 16.512 14.713 45.288 ;
     RECT  14.641 46.32 14.713 46.776 ;
     RECT  14.677 52.704 14.741 55.128 ;
     RECT  13.504 5.52 14.749 5.592 ;
     RECT  14.741 52.704 14.785 55.656 ;
     RECT  14.749 5.52 14.821 5.736 ;
     RECT  14.285 13.872 14.821 15.336 ;
     RECT  13.565 51.36 14.821 51.384 ;
     RECT  14.785 52.704 14.821 56.52 ;
     RECT  14.713 16.512 14.825 46.776 ;
     RECT  14.821 51.36 14.825 56.52 ;
     RECT  14.821 12.336 14.857 12.36 ;
     RECT  14.821 13.824 14.857 15.336 ;
     RECT  14.825 34.176 14.933 46.776 ;
     RECT  14.933 34.176 14.969 43.272 ;
     RECT  14.857 12.336 15.005 15.336 ;
     RECT  14.933 44.448 15.185 46.776 ;
     RECT  13.853 49.2 15.212 50.136 ;
     RECT  15.005 13.68 15.253 15.336 ;
     RECT  14.825 16.512 15.253 32.76 ;
     RECT  15.212 49.008 15.299 50.136 ;
     RECT  15.005 12.336 15.365 12.552 ;
     RECT  14.825 56.496 15.365 56.52 ;
     RECT  15.253 13.68 15.401 32.76 ;
     RECT  14.969 37.104 15.401 43.272 ;
     RECT  14.393 9.792 15.469 11.064 ;
     RECT  15.469 9.792 15.505 11.496 ;
     RECT  15.505 9.504 15.683 11.496 ;
     RECT  15.401 15.84 15.689 32.76 ;
     RECT  15.683 9.504 15.724 11.112 ;
     RECT  15.689 17.088 15.731 32.76 ;
     RECT  15.731 17.184 15.761 32.76 ;
     RECT  15.299 49.2 15.821 50.136 ;
     RECT  14.825 51.36 15.821 55.224 ;
     RECT  15.761 20.112 15.829 32.76 ;
     RECT  15.821 49.2 15.905 55.224 ;
     RECT  15.724 10.512 15.977 11.112 ;
     RECT  15.829 20.112 15.977 33 ;
     RECT  15.977 20.112 16.019 24.168 ;
     RECT  15.977 25.488 16.045 33 ;
     RECT  14.969 34.176 16.045 36.072 ;
     RECT  14.284 7.872 16.117 7.896 ;
     RECT  14.929 6.864 16.189 6.888 ;
     RECT  16.117 7.872 16.189 7.944 ;
     RECT  15.724 9.504 16.229 9.528 ;
     RECT  15.649 48.144 16.259 48.168 ;
     RECT  16.045 25.488 16.265 36.072 ;
     RECT  16.019 20.112 16.337 23.16 ;
     RECT  16.265 25.488 16.337 33.048 ;
     RECT  15.401 13.68 16.405 14.808 ;
     RECT  15.689 15.84 16.405 16.008 ;
     RECT  16.337 25.488 16.409 33 ;
     RECT  15.401 37.104 16.441 43.128 ;
     RECT  15.185 44.448 16.441 46.296 ;
     RECT  16.265 34.176 16.477 36.072 ;
     RECT  16.441 37.104 16.477 46.296 ;
     RECT  16.409 25.488 16.547 32.568 ;
     RECT  15.905 49.2 16.549 50.04 ;
     RECT  16.477 34.176 16.595 46.296 ;
     RECT  15.905 51.6 16.595 55.224 ;
     RECT  16.019 24.144 16.697 24.168 ;
     RECT  15.761 17.184 16.765 19.128 ;
     RECT  16.337 20.112 16.765 22.824 ;
     RECT  16.549 48.96 16.805 50.04 ;
     RECT  15.977 10.656 16.837 11.112 ;
     RECT  16.595 52.32 16.873 55.224 ;
     RECT  16.595 37.872 16.945 46.296 ;
     RECT  16.873 52.32 17.017 55.464 ;
     RECT  16.765 17.184 17.027 22.824 ;
     RECT  17.017 52.32 17.027 55.8 ;
     RECT  16.837 10.656 17.053 11.256 ;
     RECT  15.365 12.528 17.053 12.552 ;
     RECT  17.027 17.184 17.068 22.632 ;
     RECT  16.405 13.68 17.084 16.008 ;
     RECT  17.068 17.184 17.084 21.144 ;
     RECT  16.547 31.2 17.093 32.568 ;
     RECT  16.189 6.864 17.125 7.944 ;
     RECT  16.945 37.872 17.161 46.776 ;
     RECT  17.084 13.68 17.171 21.144 ;
     RECT  17.053 10.656 17.197 12.552 ;
     RECT  17.171 13.68 17.197 16.008 ;
     RECT  17.197 10.656 17.234 16.008 ;
     RECT  17.234 10.656 17.417 15.96 ;
     RECT  17.125 6.816 17.453 7.944 ;
     RECT  17.171 17.184 17.459 21.144 ;
     RECT  17.161 37.872 17.461 47.352 ;
     RECT  16.441 9.264 17.557 9.288 ;
     RECT  17.417 10.656 17.557 10.68 ;
     RECT  16.547 25.488 17.557 30.168 ;
     RECT  16.595 34.176 17.597 36.456 ;
     RECT  17.557 25.008 17.629 30.168 ;
     RECT  17.093 31.2 17.629 32.328 ;
     RECT  17.027 52.32 17.629 54.216 ;
     RECT  17.597 34.176 17.701 34.2 ;
     RECT  17.597 35.28 17.845 36.456 ;
     RECT  17.461 37.872 17.845 47.592 ;
     RECT  17.629 25.008 17.953 32.328 ;
     RECT  17.953 24.144 18.061 32.328 ;
     RECT  17.027 55.44 18.061 55.8 ;
     RECT  17.068 22.224 18.097 22.632 ;
     RECT  18.061 23.904 18.097 32.328 ;
     RECT  17.453 7.2 18.169 7.944 ;
     RECT  17.557 9.264 18.169 10.68 ;
     RECT  16.805 48.96 18.169 49.272 ;
     RECT  17.917 50.88 18.181 50.904 ;
     RECT  17.629 52.176 18.181 54.216 ;
     RECT  18.097 22.224 18.205 32.328 ;
     RECT  17.701 33.552 18.205 34.2 ;
     RECT  18.061 55.248 18.241 55.8 ;
     RECT  18.181 50.88 18.332 54.216 ;
     RECT  18.241 55.248 18.449 56.088 ;
     RECT  18.169 48.96 18.529 49.56 ;
     RECT  18.332 50.736 18.529 54.216 ;
     RECT  14.569 3.312 18.608 3.336 ;
     RECT  14.821 5.52 18.608 5.832 ;
     RECT  18.169 7.2 18.608 10.68 ;
     RECT  17.417 11.952 18.608 15.96 ;
     RECT  17.459 17.184 18.608 21 ;
     RECT  18.205 22.224 18.608 34.2 ;
     RECT  17.845 35.28 18.608 47.592 ;
     RECT  18.529 48.96 18.608 54.216 ;
     RECT  18.449 55.248 18.608 57.048 ;
     RECT  18.608 2.148 18.712 62.652 ;
     RECT  18.712 2.418 18.904 62.382 ;
     RECT  18.904 37.056 18.929 56.376 ;
     RECT  18.904 5.52 19.001 16.008 ;
     RECT  18.929 37.056 19.081 56.184 ;
     RECT  19.081 37.056 19.109 47.16 ;
     RECT  19.081 48.384 19.109 56.184 ;
     RECT  19.109 48.48 19.289 56.184 ;
     RECT  18.904 17.568 19.325 35.304 ;
     RECT  19.289 49.44 19.331 56.184 ;
     RECT  19.109 37.152 19.516 47.16 ;
     RECT  19.001 5.52 19.523 15.48 ;
     RECT  19.523 6.624 19.564 15.48 ;
     RECT  19.331 49.44 19.577 52.488 ;
     RECT  19.325 19.2 19.657 35.304 ;
     RECT  19.331 53.568 19.897 56.184 ;
     RECT  19.564 6.768 19.973 15.48 ;
     RECT  19.657 23.664 20.041 35.304 ;
     RECT  20.041 23.664 20.077 36.072 ;
     RECT  19.516 37.152 20.077 44.952 ;
     RECT  20.077 23.664 20.081 44.952 ;
     RECT  19.516 45.936 20.149 47.16 ;
     RECT  19.973 6.768 20.153 13.512 ;
     RECT  19.577 49.44 20.293 51.384 ;
     RECT  19.325 17.568 20.509 18.216 ;
     RECT  19.897 53.568 20.509 56.376 ;
     RECT  20.509 16.752 20.533 18.216 ;
     RECT  20.293 48.72 20.545 51.384 ;
     RECT  20.149 45.936 20.636 47.352 ;
     RECT  20.545 48.672 20.636 51.384 ;
     RECT  19.523 5.52 20.689 5.592 ;
     RECT  20.636 45.936 20.693 51.384 ;
     RECT  19.577 52.464 20.725 52.488 ;
     RECT  20.509 53.568 20.725 56.568 ;
     RECT  20.153 7.152 20.729 13.512 ;
     RECT  20.533 16.464 20.761 18.216 ;
     RECT  19.657 19.2 20.761 22.632 ;
     RECT  20.725 52.464 20.797 56.568 ;
     RECT  19.973 14.688 20.801 15.48 ;
     RECT  20.693 51.216 20.869 51.384 ;
     RECT  20.797 52.464 20.869 56.664 ;
     RECT  20.689 5.472 20.909 5.592 ;
     RECT  20.869 51.216 20.945 56.664 ;
     RECT  20.081 23.664 21.085 39.336 ;
     RECT  20.081 40.56 21.085 44.952 ;
     RECT  21.085 23.664 21.125 44.952 ;
     RECT  20.693 45.936 21.161 49.992 ;
     RECT  18.904 3.312 21.193 3.336 ;
     RECT  20.945 51.792 21.193 56.664 ;
     RECT  21.049 57.648 21.193 57.672 ;
     RECT  21.193 3.312 21.197 3.96 ;
     RECT  21.161 45.936 21.269 47.928 ;
     RECT  20.761 16.464 21.301 22.632 ;
     RECT  21.125 23.664 21.301 43.368 ;
     RECT  21.161 48.912 21.305 49.992 ;
     RECT  21.301 16.464 21.485 43.368 ;
     RECT  21.485 34.176 21.491 43.368 ;
     RECT  20.729 7.152 21.557 13.128 ;
     RECT  21.485 16.464 21.625 33.192 ;
     RECT  20.909 5.472 21.637 5.544 ;
     RECT  21.625 15.936 21.665 33.192 ;
     RECT  21.197 3.936 21.683 3.96 ;
     RECT  21.637 5.136 21.733 5.544 ;
     RECT  21.557 7.296 21.809 13.128 ;
     RECT  21.125 44.448 21.827 44.952 ;
     RECT  21.809 9.6 21.841 13.128 ;
     RECT  21.193 51.792 21.881 57.672 ;
     RECT  20.801 14.688 21.949 14.856 ;
     RECT  21.665 15.936 22.025 29.688 ;
     RECT  21.305 48.96 22.093 49.992 ;
     RECT  21.827 44.736 22.133 44.952 ;
     RECT  22.133 44.928 22.165 44.952 ;
     RECT  21.269 45.936 22.165 46.056 ;
     RECT  22.093 48.96 22.165 50.808 ;
     RECT  21.881 51.792 22.165 57.384 ;
     RECT  21.949 14.256 22.237 14.856 ;
     RECT  22.025 15.936 22.237 28.296 ;
     RECT  22.025 29.28 22.252 29.688 ;
     RECT  21.269 47.136 22.313 47.928 ;
     RECT  22.252 29.424 22.385 29.688 ;
     RECT  21.733 4.368 22.489 5.544 ;
     RECT  22.165 44.928 22.493 46.056 ;
     RECT  21.491 34.176 22.561 34.2 ;
     RECT  21.491 35.232 22.561 43.368 ;
     RECT  22.165 48.96 22.561 57.384 ;
     RECT  21.665 30.768 22.669 33.192 ;
     RECT  22.561 34.176 22.669 43.368 ;
     RECT  21.809 7.296 22.789 8.616 ;
     RECT  21.841 9.6 22.789 13.176 ;
     RECT  22.385 29.568 22.789 29.688 ;
     RECT  22.669 30.768 22.789 43.368 ;
     RECT  22.313 47.184 22.789 47.928 ;
     RECT  22.561 48.912 22.789 57.384 ;
     RECT  22.493 45.024 22.813 46.056 ;
     RECT  22.813 1.728 22.849 1.752 ;
     RECT  22.789 29.568 22.849 43.368 ;
     RECT  22.237 14.256 22.853 28.296 ;
     RECT  22.813 45.024 22.876 46.152 ;
     RECT  22.789 7.296 22.993 13.176 ;
     RECT  22.853 14.256 22.993 22.584 ;
     RECT  22.849 1.728 23.173 1.848 ;
     RECT  22.489 4.368 23.173 6.12 ;
     RECT  22.853 23.664 23.173 28.296 ;
     RECT  23.173 1.152 23.257 1.848 ;
     RECT  22.876 45.552 23.413 46.152 ;
     RECT  22.789 47.184 23.413 57.384 ;
     RECT  23.461 0.576 23.545 0.6 ;
     RECT  22.849 29.568 23.569 43.56 ;
     RECT  23.173 3.6 23.797 6.12 ;
     RECT  22.993 7.296 23.797 22.584 ;
     RECT  23.797 3.6 23.845 22.584 ;
     RECT  23.569 29.568 23.857 44.376 ;
     RECT  23.413 45.552 23.857 57.384 ;
     RECT  23.845 2.88 23.965 22.584 ;
     RECT  23.173 23.664 23.965 28.44 ;
     RECT  23.257 1.728 24.008 1.848 ;
     RECT  23.965 2.88 24.008 28.44 ;
     RECT  23.857 29.568 24.008 57.384 ;
     RECT  23.941 0.384 24.037 0.408 ;
     RECT  24.008 1.728 24.112 62.652 ;
     RECT  24.112 1.728 24.304 62.382 ;
     RECT  24.304 15.984 24.401 45.048 ;
     RECT  24.037 0.24 24.418 0.408 ;
     RECT  24.401 15.984 24.419 19.368 ;
     RECT  24.304 46.224 24.419 57.624 ;
     RECT  24.304 1.728 24.611 14.712 ;
     RECT  24.611 2.832 24.659 14.712 ;
     RECT  24.419 16.512 24.869 19.368 ;
     RECT  24.418 0.096 24.997 0.408 ;
     RECT  24.419 49.584 25.091 57.624 ;
     RECT  24.659 2.88 25.235 14.712 ;
     RECT  24.997 0.096 25.373 0.6 ;
     RECT  25.235 3.552 25.379 14.712 ;
     RECT  25.379 3.6 25.409 14.712 ;
     RECT  25.409 3.6 25.445 14.232 ;
     RECT  24.419 46.224 25.477 48.36 ;
     RECT  25.477 46.224 25.525 48.504 ;
     RECT  25.525 46.224 25.621 49.032 ;
     RECT  25.445 3.744 25.661 14.232 ;
     RECT  25.621 46.08 25.667 49.032 ;
     RECT  25.667 48.192 25.733 49.032 ;
     RECT  24.869 16.512 25.837 18.168 ;
     RECT  24.869 19.296 25.837 19.368 ;
     RECT  24.401 20.4 25.873 45.048 ;
     RECT  25.667 46.08 25.873 47.16 ;
     RECT  25.091 50.112 25.877 57.624 ;
     RECT  25.877 50.112 25.949 50.136 ;
     RECT  25.877 51.216 25.949 57.576 ;
     RECT  25.373 0.096 25.981 0.216 ;
     RECT  24.611 1.728 26.02 1.752 ;
     RECT  25.837 16.512 26.125 19.368 ;
     RECT  25.873 20.352 26.125 47.16 ;
     RECT  26.125 16.512 26.129 47.16 ;
     RECT  25.949 51.456 26.453 57.576 ;
     RECT  26.269 15.456 26.521 15.48 ;
     RECT  26.129 16.512 26.521 31.944 ;
     RECT  25.661 3.984 26.633 14.232 ;
     RECT  26.521 15.456 26.633 31.944 ;
     RECT  26.633 26.592 26.641 31.944 ;
     RECT  26.02 1.728 26.693 1.8 ;
     RECT  26.129 33.072 26.737 47.16 ;
     RECT  25.733 48.192 26.737 48.984 ;
     RECT  25.981 0.048 26.773 0.216 ;
     RECT  26.633 3.984 26.777 13.176 ;
     RECT  26.633 15.456 26.809 25.608 ;
     RECT  26.777 4.512 26.813 13.176 ;
     RECT  26.813 4.512 26.921 9.72 ;
     RECT  26.453 51.456 26.921 56.328 ;
     RECT  26.809 15.312 26.993 25.608 ;
     RECT  26.693 1.728 27.109 1.848 ;
     RECT  26.633 14.208 27.205 14.232 ;
     RECT  27.109 1.728 27.209 1.896 ;
     RECT  26.737 33.072 27.209 48.984 ;
     RECT  26.773 0.048 27.443 0.552 ;
     RECT  27.205 14.208 27.565 14.28 ;
     RECT  26.993 15.312 27.565 15.336 ;
     RECT  26.993 16.416 27.569 25.608 ;
     RECT  27.209 48.96 27.641 48.984 ;
     RECT  27.569 16.512 27.709 25.608 ;
     RECT  26.641 26.592 27.709 31.848 ;
     RECT  26.813 10.752 27.817 13.176 ;
     RECT  27.565 14.208 27.817 15.336 ;
     RECT  27.709 16.512 27.889 31.848 ;
     RECT  27.209 33.072 27.889 47.736 ;
     RECT  26.921 4.512 27.965 9.672 ;
     RECT  26.953 3.408 27.973 3.432 ;
     RECT  27.889 16.512 28.001 47.736 ;
     RECT  27.443 0.048 28.073 0.264 ;
     RECT  27.973 2.88 28.105 3.432 ;
     RECT  27.817 10.752 28.109 15.336 ;
     RECT  27.965 5.04 28.213 9.672 ;
     RECT  28.109 10.752 28.213 13.656 ;
     RECT  26.921 51.936 28.429 56.328 ;
     RECT  28.213 49.872 28.465 49.896 ;
     RECT  28.429 51.312 28.465 56.328 ;
     RECT  28.105 2.88 28.501 3.48 ;
     RECT  28.109 14.688 28.537 15.336 ;
     RECT  28.001 16.512 28.537 32.184 ;
     RECT  28.001 33.264 28.681 47.736 ;
     RECT  28.681 33.264 28.693 48.456 ;
     RECT  28.465 49.872 28.693 56.328 ;
     RECT  27.209 1.728 28.741 1.848 ;
     RECT  28.073 0.096 28.793 0.264 ;
     RECT  28.793 0.096 28.901 0.168 ;
     RECT  28.741 1.728 28.997 1.896 ;
     RECT  28.501 2.88 28.997 3.816 ;
     RECT  28.997 1.728 29.009 3.816 ;
     RECT  29.009 1.776 29.117 3.816 ;
     RECT  29.117 1.872 29.125 3.816 ;
     RECT  28.213 5.04 29.125 13.656 ;
     RECT  29.125 1.872 29.185 13.656 ;
     RECT  28.537 14.688 29.185 32.184 ;
     RECT  28.901 0.096 29.369 0.12 ;
     RECT  29.185 1.872 29.408 32.184 ;
     RECT  28.693 33.264 29.408 56.328 ;
     RECT  26.453 57.312 29.408 57.576 ;
     RECT  29.408 1.872 29.512 62.652 ;
     RECT  29.512 1.872 29.704 62.382 ;
     RECT  29.704 50.544 29.98 57.576 ;
     RECT  29.704 16.944 29.981 49.512 ;
     RECT  29.704 3.408 30.053 15.864 ;
     RECT  29.981 16.944 30.089 18.792 ;
     RECT  29.704 1.872 30.125 1.896 ;
     RECT  29.981 19.824 30.197 49.512 ;
     RECT  30.197 19.824 30.268 48.984 ;
     RECT  30.053 5.04 30.485 15.864 ;
     RECT  30.053 3.408 30.557 4.008 ;
     RECT  30.268 33.12 30.557 48.984 ;
     RECT  29.98 50.544 30.557 50.712 ;
     RECT  30.557 36.288 30.593 48.984 ;
     RECT  30.485 14.928 30.701 15.864 ;
     RECT  29.98 51.936 30.917 57.576 ;
     RECT  30.701 14.928 31.061 15.48 ;
     RECT  30.557 3.408 31.097 3.432 ;
     RECT  30.089 18.72 31.273 18.792 ;
     RECT  30.268 19.824 31.273 31.8 ;
     RECT  30.485 5.04 31.309 13.656 ;
     RECT  30.557 50.544 31.309 50.568 ;
     RECT  30.089 16.944 31.561 17.64 ;
     RECT  31.273 18.72 31.561 31.8 ;
     RECT  30.557 33.12 31.561 35.016 ;
     RECT  31.561 16.944 31.669 35.016 ;
     RECT  30.593 36.288 31.669 46.872 ;
     RECT  31.309 4.8 31.709 13.656 ;
     RECT  31.061 14.928 31.709 15.288 ;
     RECT  31.709 14.928 31.813 14.952 ;
     RECT  31.669 16.944 31.849 46.872 ;
     RECT  30.593 47.856 31.849 48.984 ;
     RECT  31.709 4.8 32.101 11.304 ;
     RECT  31.709 12.48 32.209 13.656 ;
     RECT  31.813 14.736 32.209 14.952 ;
     RECT  31.849 16.944 32.285 48.984 ;
     RECT  32.101 3.984 32.317 11.304 ;
     RECT  32.285 16.944 32.387 35.112 ;
     RECT  31.957 0.528 32.453 0.552 ;
     RECT  32.453 0.096 32.627 0.552 ;
     RECT  32.381 1.728 32.641 1.752 ;
     RECT  32.209 12.48 32.749 14.952 ;
     RECT  32.627 0.096 32.819 0.456 ;
     RECT  32.317 3.888 32.857 11.304 ;
     RECT  32.749 12.288 32.857 14.952 ;
     RECT  32.387 16.944 32.965 17.64 ;
     RECT  32.285 36.096 32.965 48.984 ;
     RECT  31.309 50.112 32.965 50.568 ;
     RECT  32.965 36.096 33.113 50.568 ;
     RECT  33.109 2.88 33.157 2.904 ;
     RECT  32.857 3.888 33.157 14.952 ;
     RECT  32.965 16.56 33.217 17.64 ;
     RECT  33.157 2.88 33.257 14.952 ;
     RECT  33.257 4.512 33.289 14.952 ;
     RECT  33.217 16.08 33.289 17.64 ;
     RECT  32.641 1.728 33.325 1.8 ;
     RECT  32.819 0.096 33.329 0.12 ;
     RECT  33.113 36.096 33.329 46.872 ;
     RECT  33.289 4.512 33.437 17.64 ;
     RECT  30.917 52.464 33.469 57.576 ;
     RECT  33.113 47.904 33.509 50.568 ;
     RECT  33.437 13.056 33.545 17.64 ;
     RECT  33.325 1.728 33.587 1.848 ;
     RECT  33.257 2.88 33.683 3.432 ;
     RECT  32.387 19.056 33.685 35.112 ;
     RECT  33.437 4.512 33.689 12.072 ;
     RECT  33.329 42.48 33.761 46.872 ;
     RECT  33.685 18.384 33.793 35.112 ;
     RECT  33.329 36.096 33.793 37.032 ;
     RECT  33.509 48.48 34.369 50.568 ;
     RECT  34.369 48.48 34.441 50.616 ;
     RECT  33.469 52.128 34.441 57.576 ;
     RECT  33.545 13.056 34.549 17.256 ;
     RECT  33.793 18.384 34.549 37.032 ;
     RECT  33.683 3.312 34.693 3.432 ;
     RECT  33.689 4.56 34.693 12.072 ;
     RECT  33.329 38.064 34.729 41.4 ;
     RECT  33.761 42.48 34.729 43.656 ;
     RECT  34.549 13.056 34.765 37.032 ;
     RECT  34.729 38.064 34.765 43.656 ;
     RECT  33.587 1.728 34.808 1.8 ;
     RECT  34.693 3.312 34.808 12.072 ;
     RECT  34.765 13.056 34.808 43.656 ;
     RECT  33.761 44.64 34.808 46.872 ;
     RECT  34.441 48.48 34.808 57.576 ;
     RECT  34.808 1.728 34.912 62.652 ;
     RECT  34.885 0.384 34.981 0.408 ;
     RECT  34.912 1.728 35.104 62.382 ;
     RECT  34.981 0.384 35.173 0.6 ;
     RECT  35.173 0.192 35.218 0.6 ;
     RECT  35.104 1.728 35.309 36.648 ;
     RECT  35.104 37.632 35.417 57.432 ;
     RECT  35.309 3.408 35.507 36.648 ;
     RECT  35.309 1.728 35.705 2.28 ;
     RECT  35.507 3.408 35.741 3.48 ;
     RECT  35.218 0.096 35.747 0.6 ;
     RECT  35.507 4.56 35.749 36.648 ;
     RECT  35.741 3.456 35.813 3.48 ;
     RECT  35.749 5.088 35.813 36.648 ;
     RECT  35.813 19.104 35.993 36.648 ;
     RECT  35.993 19.104 36.137 36.504 ;
     RECT  35.417 37.728 36.173 57.432 ;
     RECT  36.173 37.728 36.353 52.392 ;
     RECT  36.353 37.728 36.389 50.424 ;
     RECT  36.353 51.408 36.461 52.392 ;
     RECT  36.389 37.728 36.605 50.376 ;
     RECT  35.813 5.088 36.641 18.072 ;
     RECT  36.641 5.088 36.713 16.584 ;
     RECT  36.713 5.136 36.785 16.584 ;
     RECT  36.605 48.192 36.821 50.376 ;
     RECT  35.747 0.096 36.853 0.216 ;
     RECT  36.853 0.096 36.947 0.6 ;
     RECT  35.705 1.728 36.956 2.232 ;
     RECT  36.137 25.824 36.997 36.504 ;
     RECT  36.605 37.728 36.997 47.064 ;
     RECT  36.641 17.616 37.001 18.072 ;
     RECT  36.461 51.936 37.073 52.392 ;
     RECT  36.821 48.192 37.181 50.088 ;
     RECT  36.137 19.104 37.393 24.744 ;
     RECT  36.997 25.824 37.393 47.064 ;
     RECT  36.956 1.728 37.505 2.28 ;
     RECT  37.073 51.936 37.573 52.056 ;
     RECT  36.785 13.632 37.619 16.584 ;
     RECT  36.637 3.984 37.676 4.056 ;
     RECT  37.393 19.104 37.685 47.064 ;
     RECT  37.676 3.792 37.717 4.056 ;
     RECT  37.717 2.832 37.763 4.056 ;
     RECT  37.505 1.728 37.865 1.8 ;
     RECT  37.573 51.264 37.897 52.056 ;
     RECT  36.785 5.136 37.937 12.552 ;
     RECT  36.173 53.376 37.937 57.432 ;
     RECT  37.937 5.136 37.969 11.976 ;
     RECT  37.969 5.088 37.973 11.976 ;
     RECT  37.865 1.728 38.009 1.752 ;
     RECT  37.619 14.208 38.009 16.584 ;
     RECT  37.937 53.904 38.009 57.432 ;
     RECT  38.009 15.264 38.041 16.584 ;
     RECT  37.001 17.616 38.041 17.64 ;
     RECT  37.763 4.032 38.081 4.056 ;
     RECT  37.897 51.12 38.113 52.056 ;
     RECT  36.947 0.096 38.117 0.216 ;
     RECT  37.763 2.832 38.225 2.856 ;
     RECT  38.041 15.264 38.225 17.64 ;
     RECT  37.685 19.872 38.257 47.064 ;
     RECT  37.181 48.24 38.297 50.088 ;
     RECT  38.117 0.144 38.333 0.216 ;
     RECT  38.113 51.072 38.437 52.2 ;
     RECT  38.257 19.872 38.473 47.112 ;
     RECT  38.297 48.24 38.473 49.608 ;
     RECT  38.333 0.192 38.477 0.216 ;
     RECT  38.473 19.872 38.761 49.608 ;
     RECT  38.225 15.936 38.765 17.64 ;
     RECT  38.761 19.632 38.801 49.608 ;
     RECT  37.973 10.896 38.819 11.976 ;
     RECT  38.437 51.072 38.873 52.488 ;
     RECT  38.009 53.904 38.873 57.384 ;
     RECT  38.765 16.224 38.905 17.64 ;
     RECT  38.873 51.936 38.945 52.488 ;
     RECT  37.973 5.088 38.977 9.624 ;
     RECT  38.819 10.896 38.977 11.016 ;
     RECT  38.945 51.984 39.017 52.488 ;
     RECT  38.149 4.08 39.229 4.104 ;
     RECT  38.977 5.088 39.229 11.016 ;
     RECT  39.373 2.592 39.481 2.616 ;
     RECT  38.801 48.624 39.481 49.608 ;
     RECT  39.445 50.832 39.481 50.856 ;
     RECT  39.373 12 39.541 12.024 ;
     RECT  38.753 13.104 39.541 13.128 ;
     RECT  39.481 2.304 39.553 2.616 ;
     RECT  39.229 4.08 39.553 11.016 ;
     RECT  39.017 52.032 39.769 52.488 ;
     RECT  38.873 53.904 39.769 57.144 ;
     RECT  39.337 14.256 39.836 14.28 ;
     RECT  38.801 19.632 39.841 47.64 ;
     RECT  39.481 48.624 39.841 50.856 ;
     RECT  39.836 14.256 39.877 14.904 ;
     RECT  39.541 12 39.985 13.128 ;
     RECT  39.877 14.208 39.985 14.904 ;
     RECT  39.769 52.032 40.021 57.144 ;
     RECT  39.553 2.304 40.129 11.016 ;
     RECT  39.985 12 40.129 14.904 ;
     RECT  40.129 2.304 40.208 14.904 ;
     RECT  38.905 16.224 40.208 18.216 ;
     RECT  39.841 19.632 40.208 50.856 ;
     RECT  40.021 51.936 40.208 57.144 ;
     RECT  40.208 2.148 40.312 62.652 ;
     RECT  40.312 2.304 40.504 62.382 ;
     RECT  40.504 2.304 40.565 13.464 ;
     RECT  40.565 2.304 40.889 2.904 ;
     RECT  40.504 51.648 40.889 57.096 ;
     RECT  40.565 10.896 40.925 13.464 ;
     RECT  40.565 4.512 40.961 9.912 ;
     RECT  40.925 10.992 41.069 13.464 ;
     RECT  41.069 11.184 41.171 13.464 ;
     RECT  40.889 2.784 41.429 2.904 ;
     RECT  40.504 15.888 41.533 18.168 ;
     RECT  41.171 11.424 41.557 13.464 ;
     RECT  41.533 14.928 41.557 18.168 ;
     RECT  40.504 19.632 41.569 50.328 ;
     RECT  41.557 11.424 41.603 18.168 ;
     RECT  41.603 14.256 41.605 18.168 ;
     RECT  41.569 19.632 41.605 50.616 ;
     RECT  41.605 14.256 41.717 50.616 ;
     RECT  41.717 14.256 41.747 18.216 ;
     RECT  40.961 4.512 41.785 9.528 ;
     RECT  40.889 53.904 41.861 57.096 ;
     RECT  41.717 19.632 41.929 50.616 ;
     RECT  40.889 51.648 41.929 52.488 ;
     RECT  41.785 4.464 41.941 9.528 ;
     RECT  41.603 11.424 41.987 13.128 ;
     RECT  41.929 19.632 42.073 52.488 ;
     RECT  42.073 19.632 42.109 52.536 ;
     RECT  41.861 53.904 42.109 56.808 ;
     RECT  41.747 14.256 42.185 17.64 ;
     RECT  42.217 0.528 42.253 0.552 ;
     RECT  42.181 1.728 42.277 1.752 ;
     RECT  42.109 19.632 42.365 56.808 ;
     RECT  42.277 1.728 42.397 1.8 ;
     RECT  41.941 4.464 42.505 9.96 ;
     RECT  42.253 0.432 42.611 0.552 ;
     RECT  42.365 19.632 42.617 55.272 ;
     RECT  42.397 1.728 42.641 1.848 ;
     RECT  42.617 19.632 42.755 53.544 ;
     RECT  42.641 1.728 42.757 1.896 ;
     RECT  42.185 14.64 42.757 17.64 ;
     RECT  42.755 19.632 42.757 47.88 ;
     RECT  42.755 48.96 42.761 51.48 ;
     RECT  41.987 11.76 42.797 13.128 ;
     RECT  42.505 4.464 42.821 10.536 ;
     RECT  42.757 1.152 42.844 1.896 ;
     RECT  42.821 4.176 42.905 10.536 ;
     RECT  42.757 14.64 42.905 18.072 ;
     RECT  42.761 49.056 42.905 51.48 ;
     RECT  41.429 2.88 42.941 2.904 ;
     RECT  42.844 1.68 42.995 1.896 ;
     RECT  42.797 11.76 43.049 13.08 ;
     RECT  42.905 14.64 43.049 15.192 ;
     RECT  42.755 52.464 43.049 53.544 ;
     RECT  42.995 1.728 43.189 1.896 ;
     RECT  42.617 54.528 43.229 55.272 ;
     RECT  43.049 15.168 43.379 15.192 ;
     RECT  42.905 4.512 43.405 10.536 ;
     RECT  42.757 19.344 43.409 47.88 ;
     RECT  42.905 49.056 43.409 50.904 ;
     RECT  43.405 4.512 43.429 10.68 ;
     RECT  43.049 11.76 43.429 12.792 ;
     RECT  42.905 16.224 43.717 18.072 ;
     RECT  43.409 19.344 43.717 46.68 ;
     RECT  42.365 56.256 43.769 56.808 ;
     RECT  43.717 16.224 43.804 46.68 ;
     RECT  43.804 16.224 43.877 17.88 ;
     RECT  43.813 3.456 43.901 3.48 ;
     RECT  43.429 4.512 43.901 12.792 ;
     RECT  43.409 47.856 43.909 47.88 ;
     RECT  43.409 49.056 43.909 50.76 ;
     RECT  43.877 16.224 43.913 17.64 ;
     RECT  43.804 19.344 43.913 46.68 ;
     RECT  43.909 47.856 43.955 50.76 ;
     RECT  43.913 16.656 43.985 17.64 ;
     RECT  43.955 48.48 44.021 50.76 ;
     RECT  43.901 3.456 44.101 12.792 ;
     RECT  43.189 1.728 44.293 2.28 ;
     RECT  44.021 48.48 44.453 50.664 ;
     RECT  43.985 17.088 44.483 17.64 ;
     RECT  43.913 19.872 44.489 46.68 ;
     RECT  43.049 52.512 44.593 53.544 ;
     RECT  44.101 3.408 44.989 12.792 ;
     RECT  44.809 13.872 44.989 13.896 ;
     RECT  44.593 52.464 45.133 53.544 ;
     RECT  43.229 54.96 45.133 55.272 ;
     RECT  43.333 0.096 45.253 0.168 ;
     RECT  44.437 15.36 45.529 15.384 ;
     RECT  45.529 15.024 45.565 15.384 ;
     RECT  44.293 1.728 45.608 2.328 ;
     RECT  44.989 3.408 45.608 13.896 ;
     RECT  45.565 15.024 45.608 16.056 ;
     RECT  44.483 17.088 45.608 17.16 ;
     RECT  44.489 19.872 45.608 27.192 ;
     RECT  44.489 28.176 45.608 46.632 ;
     RECT  45.356 47.712 45.608 47.736 ;
     RECT  44.453 48.912 45.608 50.664 ;
     RECT  45.133 52.464 45.608 55.272 ;
     RECT  43.769 56.256 45.608 56.28 ;
     RECT  45.253 0.096 45.637 0.312 ;
     RECT  45.608 1.728 45.712 62.652 ;
     RECT  45.637 0.096 45.733 0.456 ;
     RECT  45.712 1.728 45.904 62.382 ;
     RECT  45.904 3.36 45.929 16.056 ;
     RECT  45.904 52.512 46.001 53.016 ;
     RECT  45.733 0.096 46.067 0.552 ;
     RECT  45.929 3.36 46.115 14.52 ;
     RECT  46.115 3.36 46.325 3.384 ;
     RECT  46.001 52.512 46.469 52.872 ;
     RECT  45.904 54.096 46.469 54.888 ;
     RECT  46.469 52.848 46.577 52.872 ;
     RECT  46.115 4.56 46.613 14.52 ;
     RECT  46.469 54.096 46.613 54.6 ;
     RECT  46.067 0.096 46.835 0.456 ;
     RECT  46.613 4.656 46.969 14.52 ;
     RECT  45.929 15.84 46.969 16.056 ;
     RECT  45.904 17.088 46.969 46.632 ;
     RECT  46.969 4.656 47.153 46.632 ;
     RECT  45.904 49.824 47.185 50.568 ;
     RECT  47.153 14.448 47.221 46.632 ;
     RECT  45.904 47.712 47.221 47.736 ;
     RECT  47.221 14.448 47.365 47.736 ;
     RECT  47.365 14.448 47.369 47.928 ;
     RECT  47.369 16.944 47.449 47.928 ;
     RECT  45.904 1.728 47.653 1.8 ;
     RECT  47.185 49.728 47.653 50.568 ;
     RECT  47.153 4.656 47.833 13.08 ;
     RECT  47.653 49.728 47.861 51.528 ;
     RECT  47.449 16.944 47.891 47.88 ;
     RECT  47.861 49.728 47.945 52.488 ;
     RECT  46.835 0.096 47.981 0.264 ;
     RECT  47.653 1.728 48.017 2.232 ;
     RECT  47.981 0.192 48.053 0.264 ;
     RECT  48.017 1.728 48.089 1.944 ;
     RECT  47.945 49.728 48.179 51.528 ;
     RECT  46.613 54.576 48.193 54.6 ;
     RECT  47.369 14.448 48.229 14.52 ;
     RECT  47.891 18.336 48.233 47.88 ;
     RECT  48.053 0.24 48.269 0.264 ;
     RECT  48.089 1.776 48.277 1.944 ;
     RECT  48.193 54.576 48.301 54.888 ;
     RECT  48.229 14.352 48.337 14.52 ;
     RECT  48.337 14.208 48.421 14.52 ;
     RECT  47.369 15.696 48.421 15.72 ;
     RECT  48.421 14.208 48.467 15.72 ;
     RECT  47.833 3.696 48.521 13.08 ;
     RECT  48.521 11.76 48.773 13.08 ;
     RECT  48.467 14.448 48.809 15.72 ;
     RECT  48.809 15.168 48.841 15.72 ;
     RECT  47.891 16.944 48.841 17.352 ;
     RECT  48.773 12.336 48.845 13.08 ;
     RECT  48.521 3.696 48.953 10.488 ;
     RECT  48.953 3.696 49.021 8.952 ;
     RECT  49.021 3.552 49.129 8.952 ;
     RECT  48.845 13.056 49.133 13.08 ;
     RECT  48.179 50.16 49.133 51.528 ;
     RECT  48.277 1.776 49.205 1.848 ;
     RECT  49.129 3.12 49.205 8.952 ;
     RECT  48.301 53.808 49.205 54.888 ;
     RECT  48.841 15.168 49.237 17.352 ;
     RECT  48.233 18.336 49.237 47.208 ;
     RECT  49.205 3.12 49.313 8.856 ;
     RECT  49.313 3.552 49.421 8.856 ;
     RECT  49.205 1.824 49.457 1.848 ;
     RECT  49.345 51.888 49.628 51.912 ;
     RECT  49.237 15.168 49.637 47.208 ;
     RECT  49.205 53.808 49.669 54.6 ;
     RECT  49.421 3.552 49.673 3.576 ;
     RECT  49.637 25.824 49.673 47.208 ;
     RECT  49.561 13.68 49.709 13.704 ;
     RECT  49.133 50.16 49.715 50.856 ;
     RECT  49.628 51.888 49.715 52.104 ;
     RECT  49.669 53.424 49.715 54.6 ;
     RECT  49.715 53.424 49.756 54.12 ;
     RECT  49.715 50.16 49.781 50.184 ;
     RECT  49.637 15.168 49.889 24.744 ;
     RECT  49.673 25.824 49.961 36.936 ;
     RECT  49.673 38.016 49.993 47.208 ;
     RECT  48.953 10.464 49.997 10.488 ;
     RECT  49.237 48.96 50.353 48.984 ;
     RECT  49.993 38.016 50.533 47.304 ;
     RECT  49.421 4.656 50.605 8.856 ;
     RECT  49.961 26.88 50.641 36.936 ;
     RECT  50.533 38.016 50.641 47.928 ;
     RECT  49.715 51.888 50.725 51.912 ;
     RECT  50.605 4.464 51.008 8.856 ;
     RECT  50.749 10.128 51.008 10.152 ;
     RECT  49.957 12 51.008 12.024 ;
     RECT  49.889 15.168 51.008 15.192 ;
     RECT  49.889 16.656 51.008 24.744 ;
     RECT  49.961 25.824 51.008 25.848 ;
     RECT  50.641 26.88 51.008 47.928 ;
     RECT  50.353 48.96 51.008 49.272 ;
     RECT  50.725 51.216 51.008 51.912 ;
     RECT  49.756 54.096 51.008 54.12 ;
     RECT  51.008 2.148 51.112 62.652 ;
     RECT  51.112 2.148 51.304 62.382 ;
     RECT  51.325 0.624 51.361 0.648 ;
     RECT  51.304 51.216 51.365 51.24 ;
     RECT  51.361 0.624 51.397 1.176 ;
     RECT  51.397 0.576 51.469 1.176 ;
     RECT  51.304 49.248 51.473 49.896 ;
     RECT  51.469 0.576 51.635 1.8 ;
     RECT  51.304 10.128 51.689 13.656 ;
     RECT  51.635 1.728 51.731 1.8 ;
     RECT  51.635 0.576 51.827 0.648 ;
     RECT  51.827 0.576 51.932 0.6 ;
     RECT  51.304 14.64 52.013 15.432 ;
     RECT  51.932 0.528 52.261 0.6 ;
     RECT  51.304 16.56 52.271 28.296 ;
     RECT  51.304 29.28 52.271 35.88 ;
     RECT  52.333 3.216 52.405 3.24 ;
     RECT  51.304 4.56 52.405 8.856 ;
     RECT  52.271 16.56 52.405 35.88 ;
     RECT  51.304 54.624 52.412 54.744 ;
     RECT  52.013 15.216 52.441 15.432 ;
     RECT  52.405 16.56 52.441 35.928 ;
     RECT  51.304 37.44 52.453 47.88 ;
     RECT  52.405 50.976 52.513 51 ;
     RECT  51.304 52.992 52.513 53.016 ;
     RECT  52.513 52.272 52.549 53.016 ;
     RECT  52.412 54.336 52.549 54.744 ;
     RECT  51.473 49.536 52.7 49.896 ;
     RECT  52.513 50.976 52.7 51.24 ;
     RECT  51.731 1.728 52.729 1.752 ;
     RECT  51.689 10.128 52.748 10.536 ;
     RECT  51.689 11.712 52.748 13.656 ;
     RECT  52.7 49.536 52.787 51.24 ;
     RECT  52.748 10.128 52.835 13.656 ;
     RECT  52.453 37.44 52.873 48.072 ;
     RECT  52.405 3.216 52.909 8.856 ;
     RECT  52.835 11.712 52.913 13.656 ;
     RECT  52.787 49.536 52.913 49.56 ;
     RECT  52.261 0.096 53.029 0.6 ;
     RECT  52.729 1.728 53.029 1.896 ;
     RECT  52.909 3.216 53.029 9 ;
     RECT  53.029 0.096 53.053 9 ;
     RECT  52.835 10.128 53.053 10.536 ;
     RECT  52.787 50.928 53.089 51.24 ;
     RECT  52.549 52.272 53.089 54.744 ;
     RECT  52.873 36.912 53.112 48.072 ;
     RECT  53.053 0.096 53.129 10.536 ;
     RECT  53.129 4.656 53.171 10.536 ;
     RECT  52.913 11.712 53.201 13.56 ;
     RECT  52.441 15.216 53.233 35.928 ;
     RECT  53.129 0.096 53.273 3.432 ;
     RECT  53.233 14.928 53.305 35.928 ;
     RECT  53.112 36.912 53.305 48.36 ;
     RECT  53.273 0.096 53.315 2.28 ;
     RECT  53.171 4.8 53.345 10.536 ;
     RECT  53.315 1.728 53.459 2.28 ;
     RECT  53.089 50.928 53.557 54.744 ;
     RECT  53.201 12.528 53.741 13.56 ;
     RECT  53.315 0.096 53.849 0.552 ;
     RECT  53.459 1.728 53.885 2.232 ;
     RECT  53.345 4.944 53.917 10.536 ;
     RECT  53.557 50.928 53.953 55.512 ;
     RECT  53.273 3.312 53.957 3.432 ;
     RECT  53.305 14.928 53.957 48.36 ;
     RECT  53.957 14.928 54.029 24.792 ;
     RECT  53.849 0.192 54.035 0.552 ;
     RECT  53.741 13.536 54.097 13.56 ;
     RECT  54.029 14.928 54.097 24.744 ;
     RECT  53.917 4.944 54.131 11.448 ;
     RECT  53.953 50.112 54.133 55.512 ;
     RECT  54.131 11.424 54.241 11.448 ;
     RECT  53.741 12.528 54.241 12.552 ;
     RECT  53.957 25.968 54.241 48.36 ;
     RECT  54.133 50.064 54.241 55.512 ;
     RECT  54.241 11.424 54.281 12.552 ;
     RECT  53.885 1.728 54.497 1.848 ;
     RECT  54.097 13.536 54.515 24.744 ;
     RECT  54.497 1.776 54.605 1.848 ;
     RECT  54.131 4.944 54.709 10.248 ;
     RECT  54.241 25.968 54.709 55.512 ;
     RECT  54.281 11.952 54.889 12.552 ;
     RECT  54.515 13.536 54.889 13.896 ;
     RECT  54.709 25.968 54.929 56.04 ;
     RECT  53.957 3.312 55.177 3.336 ;
     RECT  54.709 4.704 55.177 10.248 ;
     RECT  55.177 3.312 55.237 10.248 ;
     RECT  55.237 3.312 55.321 10.872 ;
     RECT  54.889 11.952 55.321 13.896 ;
     RECT  54.515 14.88 55.357 24.744 ;
     RECT  54.929 25.968 55.357 49.272 ;
     RECT  55.357 14.88 55.361 49.272 ;
     RECT  55.045 2.208 55.429 2.28 ;
     RECT  55.321 3.312 55.429 13.896 ;
     RECT  54.035 0.192 55.613 0.216 ;
     RECT  55.429 2.208 55.789 13.896 ;
     RECT  55.361 14.88 55.789 15.24 ;
     RECT  55.789 2.208 56.408 15.24 ;
     RECT  55.361 16.272 56.408 49.272 ;
     RECT  54.929 50.544 56.408 56.04 ;
     RECT  56.408 2.148 56.512 62.652 ;
     RECT  56.512 2.418 56.704 62.382 ;
     RECT  56.704 4.416 56.765 56.04 ;
     RECT  56.765 50.64 56.801 56.04 ;
     RECT  56.765 4.416 56.909 49.56 ;
     RECT  56.801 50.64 56.915 54.216 ;
     RECT  56.704 3.072 56.945 3.144 ;
     RECT  56.909 4.512 56.945 12.84 ;
     RECT  56.945 3.072 57.125 3.096 ;
     RECT  56.945 4.704 57.233 12.84 ;
     RECT  56.909 13.824 57.557 49.56 ;
     RECT  56.915 50.736 57.665 54.216 ;
     RECT  57.665 50.832 57.769 54.216 ;
     RECT  56.801 55.296 57.769 56.04 ;
     RECT  57.557 13.824 57.773 49.512 ;
     RECT  57.769 50.832 57.913 56.04 ;
     RECT  57.773 13.824 58.169 49.272 ;
     RECT  57.233 4.992 58.489 12.84 ;
     RECT  58.169 13.824 58.489 24.936 ;
     RECT  58.489 4.992 58.565 24.936 ;
     RECT  57.913 50.832 59.033 56.376 ;
     RECT  59.033 50.832 59.173 56.232 ;
     RECT  58.565 19.488 59.245 24.936 ;
     RECT  58.169 25.968 59.245 49.272 ;
     RECT  59.173 50.352 59.537 56.232 ;
     RECT  58.565 4.992 59.749 18.504 ;
     RECT  59.245 19.488 59.749 49.272 ;
     RECT  59.749 4.992 60.181 49.272 ;
     RECT  59.537 50.352 60.181 56.088 ;
     RECT  60.181 4.992 60.473 56.088 ;
     RECT  60.473 4.992 60.541 54.408 ;
     RECT  60.473 55.536 60.577 56.088 ;
     RECT  60.577 55.536 61.525 56.808 ;
     RECT  60.541 4.512 61.808 54.408 ;
     RECT  61.525 55.488 61.808 56.808 ;
     RECT  61.808 2.148 61.912 62.652 ;
     RECT  61.912 2.418 62.104 62.382 ;
     RECT  62.104 4.512 62.165 28.296 ;
     RECT  62.165 4.512 63.097 12.36 ;
     RECT  63.097 3.936 63.169 12.36 ;
     RECT  62.165 13.344 63.169 28.296 ;
     RECT  62.104 29.28 63.209 56.808 ;
     RECT  63.169 3.936 63.251 28.296 ;
     RECT  63.251 4.176 63.685 28.296 ;
     RECT  63.209 29.28 63.685 56.328 ;
     RECT  63.685 4.176 63.893 56.328 ;
     RECT  63.893 50.064 64.249 56.328 ;
     RECT  64.249 50.064 64.681 56.472 ;
     RECT  63.893 4.176 64.933 48.936 ;
     RECT  64.933 4.176 64.969 49.08 ;
     RECT  64.681 50.064 64.969 57.048 ;
     RECT  64.969 4.176 65.149 57.048 ;
     RECT  65.149 4.128 65.945 57.048 ;
     RECT  65.945 4.992 66.013 57.048 ;
     RECT  66.013 4.992 66.161 57.144 ;
     RECT  66.161 14.256 66.337 57.144 ;
     RECT  66.161 4.992 67.129 10.152 ;
     RECT  67.129 4.992 67.201 10.392 ;
     RECT  67.201 4.224 67.208 10.392 ;
     RECT  66.161 11.376 67.208 12.888 ;
     RECT  66.337 14.256 67.208 57.336 ;
     RECT  67.208 2.148 67.312 62.652 ;
     RECT  67.312 2.418 67.504 62.382 ;
     RECT  67.504 13.632 67.853 57.672 ;
     RECT  67.504 3.984 68.893 10.44 ;
     RECT  67.853 13.632 68.917 18.84 ;
     RECT  67.853 19.872 68.917 57.672 ;
     RECT  68.917 13.632 68.956 57.672 ;
     RECT  68.956 13.632 68.969 55.464 ;
     RECT  68.969 13.872 69.005 55.464 ;
     RECT  68.956 56.688 69.005 57.672 ;
     RECT  67.504 11.52 69.041 12.552 ;
     RECT  69.005 14.112 69.1 55.464 ;
     RECT  69.1 20.016 69.149 55.464 ;
     RECT  69.1 14.112 69.437 18.84 ;
     RECT  68.893 3.408 69.653 10.44 ;
     RECT  69.149 23.664 69.653 55.464 ;
     RECT  69.653 4.128 69.937 10.44 ;
     RECT  69.041 11.76 69.937 12.552 ;
     RECT  69.653 46.8 69.937 55.464 ;
     RECT  69.937 11.76 70.081 13.032 ;
     RECT  69.437 14.304 70.297 18.84 ;
     RECT  69.149 20.016 70.297 22.344 ;
     RECT  69.937 4.128 70.549 10.776 ;
     RECT  70.081 11.76 70.549 13.128 ;
     RECT  69.653 23.664 70.657 45.816 ;
     RECT  69.937 46.8 70.837 55.512 ;
     RECT  70.837 46.8 70.841 55.704 ;
     RECT  70.841 49.536 70.873 55.704 ;
     RECT  69.005 56.784 70.873 57.672 ;
     RECT  70.297 14.304 71.075 22.344 ;
     RECT  70.657 23.376 71.125 45.816 ;
     RECT  70.841 46.8 71.125 48.504 ;
     RECT  70.873 49.536 71.269 57.672 ;
     RECT  70.549 4.128 71.372 13.128 ;
     RECT  71.125 23.376 71.453 48.504 ;
     RECT  71.372 3.744 71.459 13.128 ;
     RECT  71.075 20.4 71.461 22.344 ;
     RECT  71.453 23.376 71.461 30.408 ;
     RECT  71.459 3.84 71.756 13.128 ;
     RECT  71.075 14.304 71.756 19.416 ;
     RECT  71.453 31.488 71.917 48.504 ;
     RECT  71.269 49.536 71.917 58.104 ;
     RECT  71.917 31.488 72.241 58.104 ;
     RECT  71.756 3.84 72.608 19.416 ;
     RECT  71.461 20.4 72.608 30.408 ;
     RECT  72.241 31.488 72.608 58.152 ;
     RECT  72.608 2.148 72.712 62.652 ;
     RECT  72.712 2.418 72.904 62.382 ;
     RECT  72.904 20.4 73.037 58.152 ;
     RECT  73.037 20.4 73.235 57.864 ;
     RECT  73.235 50.016 73.649 57.864 ;
     RECT  73.235 20.4 73.685 48.936 ;
     RECT  73.649 50.016 73.901 53.352 ;
     RECT  72.904 13.056 73.964 19.416 ;
     RECT  73.685 20.4 73.964 48.648 ;
     RECT  73.964 13.056 74.051 48.648 ;
     RECT  74.051 13.056 74.117 19.368 ;
     RECT  74.051 20.4 74.153 48.648 ;
     RECT  74.117 13.056 74.189 18.504 ;
     RECT  73.649 54.432 74.189 57.864 ;
     RECT  74.189 54.432 74.579 57.624 ;
     RECT  72.904 3.936 74.585 11.976 ;
     RECT  74.585 4.224 74.617 11.976 ;
     RECT  74.189 13.056 74.617 15 ;
     RECT  74.617 4.224 74.657 15 ;
     RECT  74.579 54.432 74.725 56.616 ;
     RECT  74.657 4.224 74.945 13.08 ;
     RECT  73.901 50.016 75.229 51.144 ;
     RECT  74.189 16.128 75.305 18.504 ;
     RECT  75.305 16.128 75.34 18.456 ;
     RECT  75.229 49.536 75.409 51.144 ;
     RECT  73.901 52.176 75.409 53.352 ;
     RECT  75.409 49.536 75.445 53.352 ;
     RECT  74.725 54.336 75.445 56.616 ;
     RECT  74.153 20.4 75.481 48.456 ;
     RECT  75.34 16.08 75.485 18.456 ;
     RECT  75.445 49.536 75.493 56.616 ;
     RECT  75.481 20.112 75.589 48.456 ;
     RECT  75.493 49.488 75.589 56.616 ;
     RECT  74.579 57.6 75.589 57.624 ;
     RECT  75.589 20.112 75.661 57.624 ;
     RECT  75.661 20.112 75.683 58.104 ;
     RECT  75.485 17.472 75.773 18.456 ;
     RECT  75.485 16.08 75.805 16.392 ;
     RECT  75.683 58.08 75.805 58.104 ;
     RECT  75.805 58.08 76.129 58.152 ;
     RECT  74.945 4.704 76.201 13.08 ;
     RECT  74.657 14.256 76.201 15 ;
     RECT  76.201 4.704 76.317 15 ;
     RECT  75.805 16.032 76.525 16.392 ;
     RECT  75.773 17.472 76.525 17.496 ;
     RECT  75.683 20.112 76.529 56.616 ;
     RECT  76.317 4.416 76.597 15 ;
     RECT  76.525 16.032 76.597 17.496 ;
     RECT  76.529 20.112 76.705 53.016 ;
     RECT  76.597 4.416 76.844 17.496 ;
     RECT  76.129 58.08 77.125 58.2 ;
     RECT  76.844 4.272 77.173 17.496 ;
     RECT  77.173 4.272 77.18 18.216 ;
     RECT  76.705 19.344 77.18 53.016 ;
     RECT  77.18 4.272 77.389 53.016 ;
     RECT  76.529 54.336 77.533 56.616 ;
     RECT  77.125 57.84 77.533 58.2 ;
     RECT  77.389 4.224 77.605 53.016 ;
     RECT  77.533 54.336 77.797 58.2 ;
     RECT  77.605 4.128 77.965 53.016 ;
     RECT  77.797 54.096 77.965 58.2 ;
     RECT  77.965 4.128 78.008 58.2 ;
     RECT  78.008 2.148 78.112 62.652 ;
     RECT  78.112 2.418 78.304 62.382 ;
     RECT  78.304 3.84 78.689 58.68 ;
     RECT  78.689 19.68 79.301 58.68 ;
     RECT  79.301 19.68 79.337 58.152 ;
     RECT  78.689 3.84 79.373 18.696 ;
     RECT  79.373 3.888 79.841 18.696 ;
     RECT  79.841 3.984 79.985 18.696 ;
     RECT  79.337 19.68 80.021 51.144 ;
     RECT  79.985 4.128 80.093 18.696 ;
     RECT  80.093 4.752 80.269 18.696 ;
     RECT  80.021 19.68 80.269 45.336 ;
     RECT  80.021 46.368 80.305 51.144 ;
     RECT  79.337 52.416 80.305 58.152 ;
     RECT  80.305 46.368 80.417 58.152 ;
     RECT  80.417 52.56 80.521 58.152 ;
     RECT  80.269 4.752 80.597 45.336 ;
     RECT  80.597 4.752 80.633 18.792 ;
     RECT  80.521 52.56 80.917 58.344 ;
     RECT  80.597 19.872 81.025 45.336 ;
     RECT  80.417 46.368 81.025 51.144 ;
     RECT  80.633 16.32 81.101 18.792 ;
     RECT  80.633 4.752 81.133 15.288 ;
     RECT  81.133 4.512 81.137 15.288 ;
     RECT  81.137 4.512 81.173 10.728 ;
     RECT  81.025 19.872 81.425 51.144 ;
     RECT  81.425 20.112 81.493 51.144 ;
     RECT  80.917 52.56 81.493 59.208 ;
     RECT  81.173 4.512 81.605 10.68 ;
     RECT  81.137 11.808 82.105 15.288 ;
     RECT  81.101 16.368 82.105 18.792 ;
     RECT  81.605 4.512 82.249 10.152 ;
     RECT  81.493 20.112 82.253 59.208 ;
     RECT  82.105 11.808 82.537 18.792 ;
     RECT  82.537 11.424 82.825 18.792 ;
     RECT  82.253 20.112 82.825 58.728 ;
     RECT  82.249 4.08 82.861 10.152 ;
     RECT  82.825 11.424 82.861 58.728 ;
     RECT  82.861 4.08 83.408 58.728 ;
     RECT  83.408 2.148 83.512 62.652 ;
     RECT  83.512 2.418 83.704 62.382 ;
     RECT  83.704 4.704 84.371 40.92 ;
     RECT  84.371 4.704 84.485 33.864 ;
     RECT  84.485 4.704 84.521 26.424 ;
     RECT  84.485 27.408 84.629 33.864 ;
     RECT  84.521 26.208 84.665 26.424 ;
     RECT  84.521 4.704 84.881 24.984 ;
     RECT  84.629 27.408 84.917 33.624 ;
     RECT  83.704 41.952 84.949 44.52 ;
     RECT  83.704 45.84 84.949 58.488 ;
     RECT  84.949 41.952 84.989 58.488 ;
     RECT  84.989 45.984 85.091 58.488 ;
     RECT  84.371 34.944 85.201 40.92 ;
     RECT  84.989 41.952 85.201 45 ;
     RECT  84.881 4.704 85.565 24.792 ;
     RECT  85.565 4.704 85.628 15.192 ;
     RECT  84.665 26.208 85.885 26.232 ;
     RECT  85.628 4.272 86.105 15.192 ;
     RECT  85.885 25.776 86.141 26.232 ;
     RECT  86.105 4.272 86.149 14.808 ;
     RECT  86.149 3.936 86.236 14.808 ;
     RECT  84.917 27.408 86.281 33.528 ;
     RECT  85.201 34.944 86.389 45 ;
     RECT  85.091 45.984 86.389 47.16 ;
     RECT  86.389 34.944 86.581 47.16 ;
     RECT  85.091 48.144 86.581 58.488 ;
     RECT  86.281 26.928 86.717 33.528 ;
     RECT  85.565 16.368 86.857 24.792 ;
     RECT  86.141 25.776 86.861 25.896 ;
     RECT  86.857 15.984 86.965 24.792 ;
     RECT  86.861 25.776 86.965 25.8 ;
     RECT  86.236 4.608 87.217 14.808 ;
     RECT  86.965 15.984 87.217 25.8 ;
     RECT  86.581 34.944 87.365 58.488 ;
     RECT  87.365 34.944 87.617 44.76 ;
     RECT  87.617 34.944 87.685 34.968 ;
     RECT  86.717 26.928 87.721 33.384 ;
     RECT  87.685 34.464 87.721 34.968 ;
     RECT  87.217 4.608 87.772 25.8 ;
     RECT  87.721 26.928 87.793 34.968 ;
     RECT  87.365 45.792 87.829 58.488 ;
     RECT  87.772 11.712 88.477 25.8 ;
     RECT  87.793 26.832 88.585 34.968 ;
     RECT  87.617 36.24 88.585 44.76 ;
     RECT  87.772 4.608 88.693 10.632 ;
     RECT  88.477 11.712 88.765 25.848 ;
     RECT  88.585 26.832 88.765 44.76 ;
     RECT  88.693 4.512 88.808 10.632 ;
     RECT  88.765 11.712 88.808 44.76 ;
     RECT  87.829 45.792 88.808 58.68 ;
     RECT  88.808 2.148 88.912 62.652 ;
     RECT  88.912 2.418 89.104 62.382 ;
     RECT  89.104 52.992 89.345 58.728 ;
     RECT  89.104 4.512 89.381 50.952 ;
     RECT  89.381 4.608 89.987 50.952 ;
     RECT  89.987 4.608 89.993 40.44 ;
     RECT  89.987 41.712 90.029 50.952 ;
     RECT  89.993 38.496 90.083 40.44 ;
     RECT  90.029 41.856 90.097 50.952 ;
     RECT  89.104 51.984 90.097 52.008 ;
     RECT  89.993 4.608 90.173 37.464 ;
     RECT  90.083 38.496 90.173 40.392 ;
     RECT  90.097 41.856 90.245 52.008 ;
     RECT  89.345 53.088 90.313 58.728 ;
     RECT  90.173 4.608 90.419 21.144 ;
     RECT  90.173 22.176 90.497 37.464 ;
     RECT  90.245 41.904 90.497 52.008 ;
     RECT  90.497 49.824 90.565 52.008 ;
     RECT  90.313 53.088 90.565 59.256 ;
     RECT  90.419 4.608 90.785 21 ;
     RECT  90.785 4.656 90.899 21 ;
     RECT  90.497 22.32 91.001 37.464 ;
     RECT  91.001 23.616 91.033 37.464 ;
     RECT  90.173 38.496 91.033 39.864 ;
     RECT  90.899 12.72 91.036 21 ;
     RECT  90.565 49.824 91.109 59.256 ;
     RECT  91.033 23.616 91.117 39.864 ;
     RECT  91.117 23.616 91.145 37.464 ;
     RECT  90.497 41.904 91.145 48.84 ;
     RECT  91.145 23.616 91.217 37.368 ;
     RECT  91.036 12.768 91.253 21 ;
     RECT  91.145 41.952 91.253 48.84 ;
     RECT  91.253 41.952 91.361 45.384 ;
     RECT  91.217 23.664 91.721 36.888 ;
     RECT  91.253 14.688 91.793 21 ;
     RECT  91.721 28.128 91.793 36.888 ;
     RECT  91.117 38.496 92.149 39.864 ;
     RECT  91.001 22.32 92.185 22.584 ;
     RECT  91.721 23.664 92.185 27.144 ;
     RECT  90.899 4.656 92.252 11.736 ;
     RECT  91.253 12.768 92.252 13.656 ;
     RECT  91.793 14.736 92.369 21 ;
     RECT  92.185 22.32 92.473 27.144 ;
     RECT  91.361 41.952 92.473 42.84 ;
     RECT  91.361 43.872 92.473 45.384 ;
     RECT  92.473 41.952 92.545 45.384 ;
     RECT  91.253 46.464 92.545 48.84 ;
     RECT  92.545 41.952 92.581 48.84 ;
     RECT  91.109 49.824 92.581 56.904 ;
     RECT  91.793 28.128 92.657 31.272 ;
     RECT  92.252 4.656 92.689 13.656 ;
     RECT  91.793 32.256 92.725 36.888 ;
     RECT  92.149 38.112 92.725 39.864 ;
     RECT  92.369 18.432 92.761 21 ;
     RECT  92.581 41.952 92.773 56.904 ;
     RECT  91.109 57.888 92.773 59.256 ;
     RECT  92.773 41.952 92.915 59.256 ;
     RECT  92.657 30.384 92.917 31.272 ;
     RECT  92.725 32.256 92.917 39.864 ;
     RECT  92.473 22.176 92.977 27.144 ;
     RECT  92.657 28.128 92.977 29.304 ;
     RECT  92.369 14.736 93.049 17.304 ;
     RECT  92.917 30.384 93.053 39.864 ;
     RECT  92.689 4.224 93.089 13.656 ;
     RECT  93.053 30.384 93.089 31.416 ;
     RECT  93.089 30.672 93.197 31.416 ;
     RECT  92.761 18.432 93.229 21.192 ;
     RECT  92.977 22.176 93.229 29.304 ;
     RECT  93.049 14.688 93.373 17.304 ;
     RECT  93.053 33.024 93.877 39.864 ;
     RECT  93.089 4.224 94.093 13.608 ;
     RECT  93.373 14.688 94.093 17.4 ;
     RECT  94.093 4.224 94.208 17.4 ;
     RECT  93.229 18.432 94.208 29.304 ;
     RECT  93.197 30.72 94.208 31.416 ;
     RECT  93.877 33.024 94.208 39.912 ;
     RECT  92.915 41.952 94.208 49.464 ;
     RECT  92.915 50.64 94.208 59.256 ;
     RECT  94.208 2.148 94.312 62.652 ;
     RECT  94.312 2.418 94.504 62.382 ;
     RECT  94.504 22.176 94.637 52.008 ;
     RECT  94.637 23.28 94.709 52.008 ;
     RECT  94.504 4.656 94.781 21.192 ;
     RECT  94.504 54.72 94.781 59.256 ;
     RECT  94.709 31.392 94.925 52.008 ;
     RECT  94.925 31.392 94.931 48.744 ;
     RECT  94.781 54.72 95.105 59.064 ;
     RECT  94.504 52.992 95.141 53.544 ;
     RECT  94.931 31.728 95.321 48.744 ;
     RECT  95.105 54.72 95.393 58.824 ;
     RECT  95.321 46.224 95.465 48.744 ;
     RECT  95.141 53.52 95.677 53.544 ;
     RECT  94.781 4.656 95.749 10.728 ;
     RECT  94.781 11.76 95.749 21.192 ;
     RECT  94.637 22.176 95.749 22.2 ;
     RECT  95.749 4.656 95.785 22.2 ;
     RECT  94.709 23.28 95.785 30.264 ;
     RECT  95.465 46.272 95.996 48.744 ;
     RECT  95.785 4.656 96.035 30.264 ;
     RECT  96.035 22.752 96.073 30.264 ;
     RECT  95.393 55.152 96.083 58.824 ;
     RECT  96.035 4.656 96.221 21.624 ;
     RECT  95.677 53.52 96.253 53.592 ;
     RECT  96.221 4.656 96.293 16.008 ;
     RECT  96.253 52.992 96.325 53.592 ;
     RECT  96.083 56.448 96.329 58.824 ;
     RECT  96.073 22.752 96.337 30.36 ;
     RECT  96.221 17.04 96.364 21.624 ;
     RECT  96.329 56.544 96.365 58.824 ;
     RECT  95.321 31.728 96.437 45.192 ;
     RECT  95.996 46.272 96.469 48.888 ;
     RECT  94.925 50.112 96.469 52.008 ;
     RECT  96.364 17.04 96.473 21.048 ;
     RECT  96.293 4.8 96.581 16.008 ;
     RECT  96.337 22.896 96.613 30.36 ;
     RECT  96.437 31.728 96.613 37.08 ;
     RECT  96.473 17.04 96.617 18.552 ;
     RECT  96.437 38.16 96.659 45.192 ;
     RECT  96.581 4.992 96.733 16.008 ;
     RECT  96.659 43.536 96.757 45.192 ;
     RECT  96.469 46.272 96.757 52.008 ;
     RECT  96.325 52.992 96.941 53.976 ;
     RECT  96.613 22.896 96.977 37.08 ;
     RECT  96.365 56.544 96.977 58.344 ;
     RECT  96.083 55.152 97.045 55.464 ;
     RECT  96.977 31.296 97.085 37.08 ;
     RECT  96.757 43.536 97.085 52.008 ;
     RECT  96.941 52.992 97.157 53.016 ;
     RECT  96.659 38.16 97.235 42.072 ;
     RECT  97.085 31.296 97.337 35.016 ;
     RECT  97.045 54.096 97.481 55.464 ;
     RECT  96.977 22.896 97.517 30.264 ;
     RECT  97.517 23.28 97.589 30.264 ;
     RECT  97.481 54.096 97.589 54.216 ;
     RECT  97.085 43.536 97.697 51.816 ;
     RECT  97.589 28.944 97.805 30.264 ;
     RECT  97.697 43.824 97.805 51.816 ;
     RECT  97.805 43.824 97.841 46.92 ;
     RECT  97.085 36.096 97.873 37.08 ;
     RECT  97.235 38.16 97.873 39.864 ;
     RECT  97.235 41.424 97.913 42.072 ;
     RECT  96.473 19.824 98.017 20.712 ;
     RECT  97.805 28.992 98.021 30.264 ;
     RECT  97.589 23.28 98.051 27.96 ;
     RECT  96.977 56.544 98.057 58.152 ;
     RECT  97.805 48.528 98.161 51.816 ;
     RECT  98.017 19.824 98.197 20.856 ;
     RECT  97.337 31.728 98.233 35.016 ;
     RECT  97.873 36.096 98.233 39.864 ;
     RECT  98.051 25.872 98.237 27.96 ;
     RECT  98.197 19.584 98.305 20.856 ;
     RECT  97.841 43.824 98.309 43.848 ;
     RECT  96.733 4.992 98.377 15.816 ;
     RECT  96.617 17.04 98.377 18.216 ;
     RECT  98.305 19.584 98.485 20.952 ;
     RECT  98.233 31.728 98.593 39.864 ;
     RECT  98.485 19.2 98.701 20.952 ;
     RECT  98.593 31.392 98.701 39.864 ;
     RECT  97.589 54.192 98.701 54.216 ;
     RECT  98.021 28.992 98.773 30.072 ;
     RECT  98.485 52.992 98.773 53.016 ;
     RECT  98.701 54.096 98.773 54.216 ;
     RECT  98.377 4.992 98.881 18.216 ;
     RECT  98.701 19.2 98.881 21.528 ;
     RECT  98.161 48.528 98.953 52.008 ;
     RECT  98.773 52.992 98.953 54.456 ;
     RECT  98.953 48.528 98.965 54.456 ;
     RECT  97.481 55.44 98.965 55.464 ;
     RECT  97.841 44.976 98.989 46.92 ;
     RECT  98.965 48.528 98.989 55.464 ;
     RECT  98.773 28.944 99.02 30.072 ;
     RECT  98.701 31.152 99.02 39.864 ;
     RECT  99.02 28.944 99.061 39.864 ;
     RECT  98.051 23.28 99.097 24.648 ;
     RECT  98.237 25.872 99.097 27.672 ;
     RECT  99.061 28.8 99.215 39.864 ;
     RECT  98.989 44.976 99.241 55.464 ;
     RECT  99.097 23.28 99.277 27.672 ;
     RECT  99.215 28.704 99.277 39.864 ;
     RECT  99.277 43.824 99.349 43.848 ;
     RECT  99.241 44.928 99.349 55.464 ;
     RECT  98.881 4.992 99.608 21.528 ;
     RECT  99.277 23.28 99.608 39.864 ;
     RECT  97.913 41.424 99.608 41.448 ;
     RECT  99.349 43.824 99.608 55.464 ;
     RECT  98.057 56.544 99.608 57.96 ;
     RECT  99.608 2.148 99.712 62.652 ;
     RECT  99.712 2.418 99.904 62.382 ;
     RECT  99.904 31.152 99.929 37.368 ;
     RECT  99.904 8.784 99.965 11.4 ;
     RECT  99.904 24.72 100.001 29.784 ;
     RECT  99.929 31.152 100.001 36.936 ;
     RECT  99.904 56.064 100.037 58.776 ;
     RECT  100.001 36.912 100.073 36.936 ;
     RECT  99.904 14.64 100.289 23.352 ;
     RECT  99.904 38.448 100.397 39.672 ;
     RECT  100.001 24.72 100.499 29.736 ;
     RECT  99.904 4.992 100.505 7.128 ;
     RECT  99.965 8.832 100.505 11.4 ;
     RECT  100.499 28.272 100.54 29.736 ;
     RECT  100.397 38.448 100.541 38.472 ;
     RECT  99.904 43.344 100.541 55.032 ;
     RECT  100.499 24.72 100.613 27.144 ;
     RECT  100.505 4.992 100.649 6.552 ;
     RECT  100.001 31.152 100.757 35.352 ;
     RECT  100.541 43.344 100.829 52.008 ;
     RECT  99.904 12.528 100.933 13.608 ;
     RECT  100.613 24.72 100.969 27.048 ;
     RECT  100.757 32.448 100.969 35.352 ;
     RECT  100.933 12.528 101.009 13.656 ;
     RECT  100.505 9.072 101.077 11.4 ;
     RECT  100.757 31.152 101.077 31.176 ;
     RECT  101.077 9.072 101.113 11.448 ;
     RECT  100.289 14.64 101.171 21 ;
     RECT  100.289 22.224 101.189 23.352 ;
     RECT  101.171 17.328 101.212 21 ;
     RECT  100.649 6.048 101.261 6.552 ;
     RECT  99.904 41.424 101.261 41.448 ;
     RECT  100.541 52.992 101.261 55.032 ;
     RECT  100.037 56.496 101.261 58.776 ;
     RECT  100.54 28.272 101.267 29.208 ;
     RECT  100.829 43.344 101.269 51.432 ;
     RECT  101.036 7.632 101.293 7.8 ;
     RECT  101.269 41.04 101.356 41.064 ;
     RECT  100.397 39.648 101.361 39.672 ;
     RECT  101.221 37.584 101.401 37.608 ;
     RECT  101.261 56.496 101.401 58.152 ;
     RECT  101.189 23.328 101.405 23.352 ;
     RECT  100.969 24.528 101.437 27.048 ;
     RECT  101.261 6.24 101.459 6.552 ;
     RECT  101.269 42.672 101.459 51.432 ;
     RECT  101.113 9.072 101.468 11.496 ;
     RECT  101.459 42.672 101.477 42.696 ;
     RECT  101.009 13.008 101.509 13.656 ;
     RECT  101.171 14.64 101.509 16.2 ;
     RECT  101.459 44.064 101.513 51.432 ;
     RECT  101.468 9.072 101.555 11.784 ;
     RECT  101.077 30.96 101.585 31.176 ;
     RECT  101.261 54.336 101.653 55.032 ;
     RECT  101.401 56.064 101.653 58.152 ;
     RECT  101.267 28.8 101.693 29.208 ;
     RECT  101.212 17.52 101.797 21 ;
     RECT  101.189 22.224 101.797 22.248 ;
     RECT  101.797 17.52 101.837 22.248 ;
     RECT  101.293 7.632 101.909 8.088 ;
     RECT  101.437 23.808 101.909 27.048 ;
     RECT  101.509 13.008 101.945 16.2 ;
     RECT  100.969 32.448 102.013 35.4 ;
     RECT  101.401 37.008 102.013 37.608 ;
     RECT  101.555 9.072 102.053 11.544 ;
     RECT  102.013 32.448 102.085 37.608 ;
     RECT  101.459 6.48 102.125 6.552 ;
     RECT  101.513 44.064 102.125 51.336 ;
     RECT  101.945 15.024 102.236 16.2 ;
     RECT  101.837 17.52 102.236 21.672 ;
     RECT  101.261 52.992 102.265 53.256 ;
     RECT  101.909 23.808 102.269 26.76 ;
     RECT  102.125 48.48 102.313 51.336 ;
     RECT  102.265 52.56 102.325 53.256 ;
     RECT  101.653 54.336 102.325 58.152 ;
     RECT  102.125 6.528 102.373 6.552 ;
     RECT  102.085 32.448 102.373 37.944 ;
     RECT  102.325 52.56 102.377 58.44 ;
     RECT  102.377 57.504 102.412 58.44 ;
     RECT  102.373 6.528 102.413 7.224 ;
     RECT  102.373 31.872 102.445 37.944 ;
     RECT  102.377 52.56 102.481 56.472 ;
     RECT  102.053 9.6 102.485 11.544 ;
     RECT  102.125 44.064 102.485 47.304 ;
     RECT  102.236 15.024 102.515 21.672 ;
     RECT  102.265 22.752 102.563 22.776 ;
     RECT  102.485 45.84 102.593 47.304 ;
     RECT  102.445 31.872 102.629 38.568 ;
     RECT  102.485 44.064 102.629 44.472 ;
     RECT  102.313 48.48 102.629 48.504 ;
     RECT  101.945 13.008 102.659 13.656 ;
     RECT  102.515 21.648 102.659 21.672 ;
     RECT  102.413 7.2 102.665 7.224 ;
     RECT  102.629 35.328 102.665 36.168 ;
     RECT  102.593 45.84 102.665 46.728 ;
     RECT  102.412 57.504 102.673 58.152 ;
     RECT  102.481 52.32 102.693 56.472 ;
     RECT  102.313 49.536 102.697 51.336 ;
     RECT  102.693 52.32 102.697 56.088 ;
     RECT  102.659 13.008 102.7 13.032 ;
     RECT  100.649 4.992 102.737 5.016 ;
     RECT  102.485 9.6 102.809 9.96 ;
     RECT  102.515 15.024 102.809 20.52 ;
     RECT  102.265 30.24 102.841 30.264 ;
     RECT  102.809 9.936 102.845 9.96 ;
     RECT  102.629 31.872 102.845 34.344 ;
     RECT  102.845 33.504 102.851 34.344 ;
     RECT  102.269 23.808 102.881 24.408 ;
     RECT  102.673 58.128 102.881 58.152 ;
     RECT  102.851 33.504 102.892 34.056 ;
     RECT  102.629 38.544 102.913 38.568 ;
     RECT  101.693 29.088 102.949 29.208 ;
     RECT  102.589 8.448 102.985 8.472 ;
     RECT  102.841 30.24 102.989 30.84 ;
     RECT  102.665 45.84 102.989 46.152 ;
     RECT  102.697 49.536 103.025 56.088 ;
     RECT  102.985 42.72 103.069 42.744 ;
     RECT  102.485 10.992 103.097 11.544 ;
     RECT  102.881 23.856 103.097 24.408 ;
     RECT  102.989 30.816 103.133 30.84 ;
     RECT  102.949 28.512 103.139 29.208 ;
     RECT  102.845 31.872 103.165 32.472 ;
     RECT  102.269 25.536 103.18 26.76 ;
     RECT  102.809 15.024 103.241 18.456 ;
     RECT  102.985 8.4 103.349 8.472 ;
     RECT  103.241 15.024 103.385 17.688 ;
     RECT  103.097 11.52 103.421 11.544 ;
     RECT  102.913 38.544 103.421 38.712 ;
     RECT  103.421 38.688 103.529 38.712 ;
     RECT  103.025 49.536 103.529 54.888 ;
     RECT  103.139 28.512 103.533 28.536 ;
     RECT  103.165 31.248 103.565 32.472 ;
     RECT  103.565 31.344 103.601 32.472 ;
     RECT  102.665 36.144 103.601 36.168 ;
     RECT  103.385 15.024 103.669 17.64 ;
     RECT  103.097 24.384 103.669 24.408 ;
     RECT  103.18 25.536 103.669 26.088 ;
     RECT  103.669 13.488 103.705 17.64 ;
     RECT  103.705 13.056 103.715 17.64 ;
     RECT  103.715 13.056 103.756 14.856 ;
     RECT  103.529 49.536 103.763 51.96 ;
     RECT  103.349 8.448 103.781 8.472 ;
     RECT  103.601 32.448 103.781 32.472 ;
     RECT  102.809 19.584 103.817 20.52 ;
     RECT  103.817 20.496 103.853 20.52 ;
     RECT  103.601 31.344 103.853 31.416 ;
     RECT  102.629 44.448 103.853 44.472 ;
     RECT  103.025 56.064 103.853 56.088 ;
     RECT  102.989 45.84 103.957 46.104 ;
     RECT  103.741 47.28 103.957 47.304 ;
     RECT  103.756 13.056 103.961 13.512 ;
     RECT  102.892 34.032 103.961 34.056 ;
     RECT  103.715 16.272 103.997 17.64 ;
     RECT  103.957 45.84 104.005 47.304 ;
     RECT  103.763 49.536 104.065 50.184 ;
     RECT  104.005 45.84 104.749 47.688 ;
     RECT  104.137 7.344 105.008 7.368 ;
     RECT  103.961 13.488 105.008 13.512 ;
     RECT  103.756 14.64 105.008 14.856 ;
     RECT  103.997 16.272 105.008 16.296 ;
     RECT  103.997 17.52 105.008 17.64 ;
     RECT  104.317 18.816 105.008 18.84 ;
     RECT  103.669 24.384 105.008 26.088 ;
     RECT  103.533 27.6 105.008 28.536 ;
     RECT  103.853 31.392 105.008 31.416 ;
     RECT  104.749 45.84 105.008 47.736 ;
     RECT  104.065 49.248 105.008 50.184 ;
     RECT  103.763 51.408 105.008 51.96 ;
     RECT  103.529 52.992 105.008 54.888 ;
     RECT  105.008 2.148 105.112 62.652 ;
     RECT  105.112 2.418 105.304 62.382 ;
     RECT  105.304 8.4 106.513 8.424 ;
     RECT  105.304 36.432 106.549 37.416 ;
     RECT  105.304 6.96 106.585 7.368 ;
     RECT  106.513 8.4 107.053 9.192 ;
     RECT  106.549 36.048 107.053 37.416 ;
     RECT  106.585 6.864 107.161 7.368 ;
     RECT  107.053 8.4 107.161 9.288 ;
     RECT  107.053 36.048 107.197 37.8 ;
     RECT  107.197 35.856 107.233 38.184 ;
     RECT  107.161 6.864 107.665 9.288 ;
     RECT  107.665 6.864 107.701 9.384 ;
     RECT  107.233 35.568 107.737 38.184 ;
     RECT  107.737 35.568 107.809 38.376 ;
     RECT  107.701 6.864 107.845 9.768 ;
     RECT  107.809 35.472 107.845 38.376 ;
     RECT  107.845 35.376 107.881 38.376 ;
     RECT  107.845 6.864 107.957 9.96 ;
     RECT  107.957 6.864 107.964 9.864 ;
     RECT  107.881 35.28 107.964 38.376 ;
     RECT  107.964 38.352 107.993 38.376 ;
    LAYER M5 ;
     RECT  51.408 0.016 54.408 0.611 ;
     RECT  9.936 0.016 12.936 1.763 ;
     RECT  22.992 0.016 29.064 1.763 ;
     RECT  32.208 0.016 37.896 1.763 ;
     RECT  42.192 0.016 48.264 1.763 ;
     RECT  10.032 1.763 12.936 1.811 ;
     RECT  42.288 1.763 48.264 1.811 ;
     RECT  23.088 1.763 29.064 1.859 ;
     RECT  42.48 1.811 46.536 1.859 ;
     RECT  51.504 0.611 54.408 1.859 ;
     RECT  23.568 1.859 29.064 1.907 ;
     RECT  42.672 1.859 46.536 1.907 ;
     RECT  27.984 1.907 29.064 1.955 ;
     RECT  47.664 1.811 48.264 1.955 ;
     RECT  10.416 1.811 12.936 2.137 ;
     RECT  51.504 1.859 53.928 2.137 ;
     RECT  2.4 2.137 2.52 2.151 ;
     RECT  7.8 2.137 7.92 2.151 ;
     RECT  10.416 2.137 13.32 2.151 ;
     RECT  18.6 2.137 18.72 2.151 ;
     RECT  29.4 2.137 29.52 2.151 ;
     RECT  40.2 2.137 40.32 2.151 ;
     RECT  56.4 2.137 56.52 2.151 ;
     RECT  61.8 2.137 61.92 2.151 ;
     RECT  67.2 2.137 67.32 2.151 ;
     RECT  72.6 2.137 72.72 2.151 ;
     RECT  78 2.137 78.12 2.151 ;
     RECT  83.4 2.137 83.52 2.151 ;
     RECT  88.8 2.137 88.92 2.151 ;
     RECT  94.2 2.137 94.32 2.151 ;
     RECT  99.6 2.137 99.72 2.151 ;
     RECT  105 2.137 105.12 2.151 ;
     RECT  47.664 1.955 47.88 2.243 ;
     RECT  10.416 2.151 13.512 2.291 ;
     RECT  40.2 2.151 40.512 2.581 ;
     RECT  27.984 1.955 28.2 2.915 ;
     RECT  28.08 2.915 28.2 3.013 ;
     RECT  29.4 2.151 29.712 3.013 ;
     RECT  11.376 2.291 12.072 3.107 ;
     RECT  51 2.137 53.928 3.347 ;
     RECT  12.048 3.107 12.072 3.443 ;
     RECT  28.08 3.013 29.712 3.443 ;
     RECT  32.208 1.763 37.8 3.443 ;
     RECT  51 3.347 53.736 3.443 ;
     RECT  28.176 3.443 29.712 3.491 ;
     RECT  34.128 3.443 37.8 3.491 ;
     RECT  42.864 1.907 46.536 3.491 ;
     RECT  23.568 1.907 26.472 4.019 ;
     RECT  32.208 3.443 33 4.019 ;
     RECT  36.72 3.491 37.8 4.019 ;
     RECT  24 4.019 26.472 4.067 ;
     RECT  32.448 4.019 33 4.067 ;
     RECT  36.816 4.019 37.8 4.067 ;
     RECT  43.92 3.491 46.536 4.067 ;
     RECT  25.392 4.067 26.472 4.115 ;
     RECT  78 2.151 78.312 4.117 ;
     RECT  79.488 3.973 79.512 4.117 ;
     RECT  42.864 3.491 42.888 4.211 ;
     RECT  43.92 4.067 44.616 4.211 ;
     RECT  78 4.117 79.512 4.259 ;
     RECT  86.16 3.925 86.184 4.261 ;
     RECT  13.2 2.291 13.512 4.405 ;
     RECT  76.896 4.261 76.92 4.405 ;
     RECT  13.056 4.405 13.512 4.501 ;
     RECT  88.8 2.151 89.112 4.501 ;
     RECT  55.056 2.245 55.08 4.549 ;
     RECT  25.536 4.115 26.472 4.595 ;
     RECT  34.128 3.491 35.736 4.595 ;
     RECT  44.592 4.211 44.616 4.595 ;
     RECT  51 3.443 53.448 4.595 ;
     RECT  29.136 3.491 29.712 4.643 ;
     RECT  51 4.595 51.912 4.643 ;
     RECT  79.488 4.259 79.512 4.643 ;
     RECT  63.216 3.925 63.24 4.645 ;
     RECT  24 4.067 24.408 4.691 ;
     RECT  34.272 4.595 35.496 4.691 ;
     RECT  63.216 4.645 64.056 4.691 ;
     RECT  88.704 4.501 89.112 4.693 ;
     RECT  76.368 4.405 76.92 4.739 ;
     RECT  39.6 2.581 40.512 4.741 ;
     RECT  61.8 2.151 62.112 4.741 ;
     RECT  21.648 3.925 21.672 4.837 ;
     RECT  12.864 4.501 13.512 4.933 ;
     RECT  76.896 4.739 76.92 4.979 ;
     RECT  51 4.643 51.528 5.027 ;
     RECT  67.2 2.151 67.512 5.029 ;
     RECT  85.68 4.261 86.184 5.075 ;
     RECT  32.448 4.067 32.472 5.077 ;
     RECT  78 4.259 78.312 5.077 ;
     RECT  94.2 2.151 94.512 5.077 ;
     RECT  55.056 4.549 55.224 5.123 ;
     RECT  45.6 4.067 46.536 5.125 ;
     RECT  72.6 2.151 72.912 5.125 ;
     RECT  21.648 4.837 21.768 5.171 ;
     RECT  32.448 5.077 33.192 5.171 ;
     RECT  64.032 4.691 64.056 5.171 ;
     RECT  85.68 5.075 85.704 5.219 ;
     RECT  52.992 4.595 53.448 5.269 ;
     RECT  74.688 4.933 74.712 5.269 ;
     RECT  45.6 5.125 46.872 5.315 ;
     RECT  29.4 4.643 29.712 5.365 ;
     RECT  71.424 3.733 71.448 5.459 ;
     RECT  45.6 5.315 46.776 5.461 ;
     RECT  52.992 5.269 53.592 5.461 ;
     RECT  55.056 5.123 55.08 5.461 ;
     RECT  52.992 5.461 55.08 5.507 ;
     RECT  11.952 4.933 13.512 5.557 ;
     RECT  33.168 5.171 33.192 5.605 ;
     RECT  34.272 4.691 35.112 5.605 ;
     RECT  72.6 5.125 73.368 5.605 ;
     RECT  71.808 5.605 73.368 5.651 ;
     RECT  21.744 5.171 21.768 5.653 ;
     RECT  11.952 5.557 14.184 5.699 ;
     RECT  48.672 4.501 48.696 5.699 ;
     RECT  64.992 5.653 65.016 5.701 ;
     RECT  79.776 5.125 79.8 5.747 ;
     RECT  24 4.691 24.312 5.749 ;
     RECT  18.6 2.151 18.912 5.797 ;
     RECT  67.2 5.029 67.848 5.845 ;
     RECT  67.2 5.845 67.944 5.989 ;
     RECT  33.168 5.605 35.112 6.035 ;
     RECT  74.688 5.269 74.856 6.035 ;
     RECT  94.08 5.077 94.512 6.035 ;
     RECT  29.4 5.365 29.976 6.085 ;
     RECT  24 5.749 24.456 6.179 ;
     RECT  31.968 5.653 31.992 6.181 ;
     RECT  33.168 6.035 33.192 6.181 ;
     RECT  42.96 4.501 42.984 6.181 ;
     RECT  61.152 4.741 62.112 6.229 ;
     RECT  52.992 5.507 54.36 6.275 ;
     RECT  74.784 6.035 74.856 6.275 ;
     RECT  31.968 6.181 33.192 6.371 ;
     RECT  27.312 6.229 27.336 6.565 ;
     RECT  52.992 6.275 53.592 6.611 ;
     RECT  11.952 5.699 11.976 6.661 ;
     RECT  13.2 5.699 14.184 6.661 ;
     RECT  34.272 6.035 35.112 6.661 ;
     RECT  27.312 6.565 27.96 6.709 ;
     RECT  29.04 6.085 29.976 6.709 ;
     RECT  56.4 2.151 56.712 6.709 ;
     RECT  57.744 6.229 57.768 6.709 ;
     RECT  18.6 5.797 19.512 6.757 ;
     RECT  67.056 5.989 67.944 6.757 ;
     RECT  18.6 6.757 19.608 6.805 ;
     RECT  24 6.179 24.312 6.805 ;
     RECT  64.992 5.701 65.832 6.805 ;
     RECT  66.96 6.757 67.944 6.805 ;
     RECT  56.4 6.709 57.768 6.899 ;
     RECT  48.864 6.229 48.888 6.995 ;
     RECT  52.992 6.611 53.016 7.043 ;
     RECT  44.976 5.461 46.776 7.141 ;
     RECT  42.96 6.181 43.368 7.187 ;
     RECT  44.496 7.141 46.776 7.187 ;
     RECT  83.4 2.151 83.712 7.189 ;
     RECT  71.808 5.651 72.912 7.237 ;
     RECT  34.272 6.661 35.88 7.285 ;
     RECT  60.576 6.229 62.112 7.285 ;
     RECT  77.904 5.077 78.312 7.285 ;
     RECT  27.312 6.709 29.976 7.331 ;
     RECT  98.064 5.845 98.088 7.333 ;
     RECT  11.952 6.661 14.184 7.379 ;
     RECT  98.064 7.333 98.328 7.379 ;
     RECT  39.552 4.741 40.512 7.381 ;
     RECT  84.816 7.237 84.84 7.381 ;
     RECT  12.912 7.379 14.184 7.427 ;
     RECT  27.936 7.331 29.976 7.427 ;
     RECT  83.184 7.189 83.712 7.427 ;
     RECT  77.904 7.285 78.744 7.429 ;
     RECT  31.968 6.371 32.472 7.475 ;
     RECT  77.328 7.429 78.744 7.475 ;
     RECT  93.024 6.277 93.048 7.475 ;
     RECT  64.992 6.805 67.944 7.523 ;
     RECT  90.624 6.085 90.648 7.573 ;
     RECT  17.136 6.805 17.16 7.619 ;
     RECT  31.968 7.475 31.992 7.619 ;
     RECT  90.624 7.573 90.84 7.619 ;
     RECT  27.936 7.427 29.88 7.667 ;
     RECT  39.456 7.381 40.512 7.717 ;
     RECT  43.344 7.187 43.368 7.717 ;
     RECT  44.496 7.187 46.728 7.717 ;
     RECT  95.76 6.229 95.784 7.765 ;
     RECT  101.424 6.229 101.448 7.765 ;
     RECT  64.992 7.523 65.016 7.811 ;
     RECT  41.568 5.989 41.592 7.859 ;
     RECT  25.536 4.595 25.56 7.861 ;
     RECT  13.2 7.427 14.184 7.909 ;
     RECT  21.744 5.653 22.728 7.909 ;
     RECT  34.224 7.285 35.88 7.909 ;
     RECT  37.056 6.181 37.08 7.909 ;
     RECT  84.816 7.381 84.936 7.909 ;
     RECT  7.8 2.151 8.112 7.957 ;
     RECT  18.6 6.805 19.944 7.957 ;
     RECT  83.28 7.427 83.712 7.957 ;
     RECT  84.816 7.909 84.984 7.957 ;
     RECT  18.6 7.957 20.52 8.003 ;
     RECT  25.392 7.861 25.56 8.003 ;
     RECT  34.224 7.909 37.08 8.003 ;
     RECT  83.28 7.957 84.984 8.003 ;
     RECT  28.368 7.667 29.88 8.051 ;
     RECT  71.568 7.237 72.912 8.099 ;
     RECT  88.56 4.693 89.112 8.197 ;
     RECT  60.432 7.285 62.112 8.339 ;
     RECT  21.744 7.909 22.824 8.341 ;
     RECT  83.4 8.003 84.984 8.389 ;
     RECT  48.576 7.381 48.6 8.435 ;
     RECT  56.4 6.899 56.856 8.483 ;
     RECT  38.784 7.717 40.512 8.485 ;
     RECT  43.344 7.717 46.728 8.485 ;
     RECT  71.952 8.099 72.912 8.485 ;
     RECT  43.344 8.485 47.304 8.579 ;
     RECT  82.224 7.957 82.248 8.723 ;
     RECT  55.248 8.389 55.272 8.869 ;
     RECT  56.4 8.483 56.712 8.869 ;
     RECT  63.552 7.957 63.576 8.963 ;
     RECT  77.328 7.475 78.648 8.963 ;
     RECT  90.816 7.619 90.84 8.965 ;
     RECT  23.808 6.805 24.312 9.011 ;
     RECT  57.744 8.485 57.768 9.013 ;
     RECT  38.784 8.485 40.632 9.059 ;
     RECT  57.744 9.013 58.152 9.059 ;
     RECT  25.536 8.003 25.56 9.061 ;
     RECT  39.456 9.059 40.632 9.061 ;
     RECT  87.888 8.197 89.112 9.061 ;
     RECT  26.736 8.533 26.76 9.155 ;
     RECT  87.6 9.061 89.112 9.155 ;
     RECT  95.76 7.765 96.312 9.155 ;
     RECT  83.4 8.389 85.128 9.299 ;
     RECT  28.368 8.051 28.392 9.397 ;
     RECT  29.4 8.051 29.88 9.397 ;
     RECT  54.144 7.381 54.168 9.491 ;
     RECT  13.2 7.909 14.232 9.541 ;
     RECT  28.368 9.397 29.88 9.541 ;
     RECT  34.224 8.003 36.648 9.683 ;
     RECT  25.536 9.061 25.656 9.685 ;
     RECT  55.248 8.869 56.712 9.731 ;
     RECT  21.648 8.341 22.824 9.779 ;
     RECT  101.088 7.765 101.448 9.779 ;
     RECT  7.8 7.957 8.232 9.781 ;
     RECT  34.224 9.683 35.256 9.827 ;
     RECT  71.952 8.485 73.704 9.827 ;
     RECT  20.496 8.003 20.52 9.875 ;
     RECT  36.624 9.683 36.648 9.877 ;
     RECT  90.576 8.965 90.84 9.923 ;
     RECT  39.456 9.061 41.592 9.925 ;
     RECT  107.856 9.829 107.88 9.971 ;
     RECT  90.816 9.923 90.84 10.019 ;
     RECT  18.6 8.003 18.912 10.069 ;
     RECT  70.56 7.909 70.584 10.115 ;
     RECT  28.368 9.541 30.696 10.163 ;
     RECT  32.976 8.341 33 10.165 ;
     RECT  34.224 9.827 35.112 10.165 ;
     RECT  10.56 7.285 10.584 10.213 ;
     RECT  25.392 9.685 25.656 10.213 ;
     RECT  22.704 9.779 22.824 10.259 ;
     RECT  25.392 10.213 25.752 10.307 ;
     RECT  43.344 8.579 46.2 10.307 ;
     RECT  44.496 10.307 46.2 10.355 ;
     RECT  58.128 9.059 58.152 10.355 ;
     RECT  87.6 9.155 87.624 10.357 ;
     RECT  88.704 9.155 89.112 10.357 ;
     RECT  13.104 9.541 14.232 10.451 ;
     RECT  44.496 10.355 44.52 10.451 ;
     RECT  6.288 9.637 6.312 10.453 ;
     RECT  21.648 9.779 21.672 10.453 ;
     RECT  51 5.027 51.312 10.501 ;
     RECT  6.288 10.453 6.648 10.595 ;
     RECT  7.68 9.781 8.232 10.595 ;
     RECT  75.84 9.685 75.864 10.595 ;
     RECT  36.624 9.877 37.224 10.643 ;
     RECT  59.232 10.597 59.256 10.645 ;
     RECT  74.784 6.275 74.808 10.691 ;
     RECT  28.368 10.163 29.88 10.741 ;
     RECT  72.6 9.827 73.704 10.789 ;
     RECT  83.4 9.299 83.976 10.789 ;
     RECT  32.976 10.165 35.112 10.835 ;
     RECT  58.704 10.645 59.256 10.835 ;
     RECT  27.936 10.741 29.88 10.883 ;
     RECT  31.872 10.501 31.896 10.883 ;
     RECT  43.344 10.307 43.464 10.883 ;
     RECT  54.096 9.637 54.12 10.883 ;
     RECT  87.6 10.357 89.112 10.883 ;
     RECT  82.896 10.789 83.976 11.173 ;
     RECT  85.104 9.299 85.128 11.173 ;
     RECT  28.368 10.883 29.88 11.219 ;
     RECT  95.76 9.155 95.784 11.221 ;
     RECT  95.76 11.221 96.312 11.269 ;
     RECT  95.76 11.269 97.08 11.363 ;
     RECT  4.992 7.381 5.016 11.365 ;
     RECT  59.232 10.835 59.256 11.365 ;
     RECT  60.768 8.339 62.112 11.365 ;
     RECT  66.624 7.523 67.944 11.365 ;
     RECT  72.6 10.789 73.992 11.365 ;
     RECT  87.696 10.883 89.112 11.365 ;
     RECT  93.168 8.245 93.192 11.365 ;
     RECT  13.104 10.451 14.184 11.459 ;
     RECT  20.832 10.453 21.672 11.459 ;
     RECT  32.976 10.835 33 11.459 ;
     RECT  39.456 9.925 41.976 11.459 ;
     RECT  51 10.501 51.672 11.459 ;
     RECT  87.696 11.365 89.4 11.459 ;
     RECT  101.088 9.779 101.112 11.459 ;
     RECT  15.648 9.781 15.672 11.507 ;
     RECT  25.488 10.307 25.752 11.507 ;
     RECT  45.6 10.355 46.2 11.509 ;
     RECT  78 8.963 78.648 11.509 ;
     RECT  44.784 11.509 46.2 11.701 ;
     RECT  47.28 8.579 47.304 11.701 ;
     RECT  7.8 10.595 8.232 11.749 ;
     RECT  18.432 10.069 18.912 11.749 ;
     RECT  44.784 11.701 47.304 11.795 ;
     RECT  10.56 10.213 11.448 11.843 ;
     RECT  82.896 11.173 85.128 11.845 ;
     RECT  94.2 6.035 94.512 11.845 ;
     RECT  22.704 10.259 22.728 11.941 ;
     RECT  39.456 11.459 41.592 11.941 ;
     RECT  72.336 11.365 73.992 11.941 ;
     RECT  98.304 7.379 98.328 11.941 ;
     RECT  88.512 11.459 89.4 11.987 ;
     RECT  6.624 10.595 6.648 12.035 ;
     RECT  22.704 11.941 22.92 12.035 ;
     RECT  88.512 11.987 89.112 12.035 ;
     RECT  75.6 11.413 75.624 12.179 ;
     RECT  92.304 11.365 93.192 12.179 ;
     RECT  59.232 11.365 62.112 12.227 ;
     RECT  65.712 11.365 67.944 12.227 ;
     RECT  80.4 11.125 80.424 12.227 ;
     RECT  95.76 11.363 96.024 12.227 ;
     RECT  90.96 11.653 90.984 12.229 ;
     RECT  24 9.011 24.312 12.325 ;
     RECT  25.488 11.507 25.656 12.325 ;
     RECT  24 12.325 25.656 12.371 ;
     RECT  93.168 12.179 93.192 12.515 ;
     RECT  4.992 11.365 5.496 12.517 ;
     RECT  10.56 11.843 10.584 12.563 ;
     RECT  55.248 9.731 55.272 12.563 ;
     RECT  63.552 11.797 63.576 12.563 ;
     RECT  82.08 11.845 85.128 12.563 ;
     RECT  18.432 11.749 19.512 12.611 ;
     RECT  18.432 12.611 19.416 12.755 ;
     RECT  70.752 11.317 70.776 12.755 ;
     RECT  90.864 12.229 90.984 12.755 ;
     RECT  98.208 11.941 98.328 12.755 ;
     RECT  56.4 9.731 56.712 12.805 ;
     RECT  28.368 11.219 29.712 12.853 ;
     RECT  97.056 11.363 97.08 12.947 ;
     RECT  78 11.509 78.696 12.997 ;
     RECT  101.52 11.749 101.544 12.997 ;
     RECT  7.8 11.749 8.616 13.043 ;
     RECT  24 12.371 25.512 13.091 ;
     RECT  44.928 11.795 47.304 13.091 ;
     RECT  72.336 11.941 74.376 13.091 ;
     RECT  90.864 12.755 90.888 13.093 ;
     RECT  21.648 11.459 21.672 13.139 ;
     RECT  38.784 11.941 41.592 13.139 ;
     RECT  6.48 12.517 6.504 13.187 ;
     RECT  25.488 13.091 25.512 13.187 ;
     RECT  39.456 13.139 41.592 13.331 ;
     RECT  22.752 12.035 22.92 13.381 ;
     RECT  24 13.091 24.312 13.381 ;
     RECT  72.336 13.091 72.912 13.429 ;
     RECT  37.2 10.643 37.224 13.477 ;
     RECT  59.232 12.227 59.256 13.477 ;
     RECT  60.768 12.227 62.112 13.477 ;
     RECT  90.624 13.093 90.888 13.525 ;
     RECT  36.24 13.477 37.224 13.621 ;
     RECT  88.8 12.035 89.112 13.621 ;
     RECT  13.2 11.459 13.512 13.669 ;
     RECT  4.512 12.517 5.496 13.715 ;
     RECT  18.48 12.755 19.416 13.715 ;
     RECT  59.232 13.477 62.112 13.715 ;
     RECT  4.512 13.715 4.536 13.811 ;
     RECT  95.856 12.227 96.024 13.813 ;
     RECT  18.48 13.715 18.912 13.955 ;
     RECT  34.224 10.835 35.112 13.957 ;
     RECT  66 12.227 67.512 14.005 ;
     RECT  88.08 13.621 89.112 14.005 ;
     RECT  28.368 12.853 29.832 14.149 ;
     RECT  82.896 12.563 85.128 14.149 ;
     RECT  82.896 14.149 85.272 14.195 ;
     RECT  88.08 14.005 89.208 14.197 ;
     RECT  90.24 13.525 90.888 14.197 ;
     RECT  36.24 13.621 37.608 14.243 ;
     RECT  61.68 13.715 62.112 14.243 ;
     RECT  41.568 13.331 41.592 14.291 ;
     RECT  71.808 13.429 72.912 14.291 ;
     RECT  101.52 12.997 102.648 14.291 ;
     RECT  22.752 13.381 24.312 14.341 ;
     RECT  22.272 14.341 24.312 14.387 ;
     RECT  44.928 13.091 46.632 14.387 ;
     RECT  65.808 14.005 67.512 14.485 ;
     RECT  43.344 10.883 43.368 14.629 ;
     RECT  94.2 11.845 94.728 14.723 ;
     RECT  59.232 13.715 60.12 14.725 ;
     RECT  88.08 14.197 90.888 14.725 ;
     RECT  94.2 14.723 94.632 14.773 ;
     RECT  95.76 13.813 96.024 14.773 ;
     RECT  22.272 14.387 22.968 14.819 ;
     RECT  93.504 14.773 94.632 14.867 ;
     RECT  28.368 14.149 29.88 14.963 ;
     RECT  88.08 14.725 91.32 15.061 ;
     RECT  65.808 14.485 67.848 15.203 ;
     RECT  7.8 13.043 8.112 15.301 ;
     RECT  44.928 14.387 45.912 15.349 ;
     RECT  51 11.459 51.312 15.349 ;
     RECT  76.608 13.045 76.632 15.349 ;
     RECT  78 12.997 79.272 15.349 ;
     RECT  44.448 15.349 45.912 15.395 ;
     RECT  87.312 15.061 91.32 15.395 ;
     RECT  42.48 14.629 43.368 15.443 ;
     RECT  65.808 15.203 67.512 15.443 ;
     RECT  103.68 14.389 103.704 15.443 ;
     RECT  82.896 14.195 84.264 15.445 ;
     RECT  85.248 14.195 85.272 15.445 ;
     RECT  54.48 14.197 54.504 15.491 ;
     RECT  98.304 12.755 98.328 15.493 ;
     RECT  102.624 14.291 102.648 15.493 ;
     RECT  98.064 15.493 98.328 15.539 ;
     RECT  12.096 13.045 12.12 15.637 ;
     RECT  13.104 13.669 13.512 15.637 ;
     RECT  29.4 14.963 29.88 15.637 ;
     RECT  93.504 14.867 94.512 15.683 ;
     RECT  48.432 14.197 48.456 15.731 ;
     RECT  66 15.443 67.512 15.731 ;
     RECT  36.864 14.243 37.608 15.733 ;
     RECT  36.576 15.733 37.608 15.779 ;
     RECT  16.992 13.669 17.016 15.829 ;
     RECT  82.896 15.445 85.272 15.875 ;
     RECT  72.288 14.291 72.912 15.877 ;
     RECT  51 15.349 51.624 15.925 ;
     RECT  52.8 7.957 52.824 15.925 ;
     RECT  70.416 14.773 70.44 15.925 ;
     RECT  24 14.387 24.312 15.973 ;
     RECT  16.992 15.829 17.592 16.019 ;
     RECT  22.416 14.819 22.968 16.019 ;
     RECT  51 15.925 52.824 16.019 ;
     RECT  59.232 14.725 60.456 16.019 ;
     RECT  76.608 15.349 79.272 16.019 ;
     RECT  87.312 15.395 87.768 16.019 ;
     RECT  95.76 14.773 96.696 16.019 ;
     RECT  102.288 15.493 102.648 16.211 ;
     RECT  39.456 13.331 40.512 16.405 ;
     RECT  22.416 16.019 22.776 16.501 ;
     RECT  28.368 14.963 28.392 16.501 ;
     RECT  56.112 12.805 56.712 16.501 ;
     RECT  88.8 15.395 91.32 16.547 ;
     RECT  82.896 15.875 84.264 16.549 ;
     RECT  33.504 13.957 35.112 16.595 ;
     RECT  36.576 15.779 37.464 16.595 ;
     RECT  60.096 16.019 60.456 16.595 ;
     RECT  66.096 15.731 67.512 16.595 ;
     RECT  76.608 16.019 76.632 16.595 ;
     RECT  94.032 15.683 94.512 16.595 ;
     RECT  33.792 16.595 35.112 16.643 ;
     RECT  49.344 15.877 49.368 16.645 ;
     RECT  60.432 16.595 60.456 16.691 ;
     RECT  70.272 15.925 70.44 16.885 ;
     RECT  39.072 16.405 40.512 16.931 ;
     RECT  12.096 15.637 13.512 16.981 ;
     RECT  74.352 13.091 74.376 17.027 ;
     RECT  55.248 16.501 56.712 17.029 ;
     RECT  69.072 16.405 69.096 17.075 ;
     RECT  81.072 16.501 81.096 17.075 ;
     RECT  82.848 16.549 84.264 17.123 ;
     RECT  88.8 16.547 90.456 17.123 ;
     RECT  72.24 15.877 72.912 17.267 ;
     RECT  15.696 15.925 15.72 17.315 ;
     RECT  82.896 17.123 84.264 17.315 ;
     RECT  58.656 17.029 58.68 17.363 ;
     RECT  95.76 16.019 96.024 17.363 ;
     RECT  101.136 16.357 101.16 17.363 ;
     RECT  87.744 16.019 87.768 17.411 ;
     RECT  88.8 17.123 90.168 17.411 ;
     RECT  39.456 16.931 40.512 17.459 ;
     RECT  4.8 15.877 4.824 17.461 ;
     RECT  22.368 16.501 22.776 17.461 ;
     RECT  43.344 15.443 43.368 17.509 ;
     RECT  54.672 17.029 56.712 17.555 ;
     RECT  36.576 16.595 36.6 17.603 ;
     RECT  29.4 15.637 30.552 17.605 ;
     RECT  49.344 16.645 49.416 17.605 ;
     RECT  51 16.019 52.488 17.605 ;
     RECT  98.064 15.539 98.088 17.605 ;
     RECT  99.6 2.151 99.912 17.605 ;
     RECT  20.544 16.453 20.568 17.651 ;
     RECT  44.448 15.395 44.472 17.651 ;
     RECT  11.376 16.981 13.512 17.699 ;
     RECT  24 15.973 24.408 17.699 ;
     RECT  47.856 17.029 47.88 17.699 ;
     RECT  98.064 17.605 99.912 17.699 ;
     RECT  55.248 17.555 56.712 17.843 ;
     RECT  42.768 17.509 43.368 17.845 ;
     RECT  7.8 15.301 8.232 17.891 ;
     RECT  34.704 16.643 35.112 18.037 ;
     RECT  14.928 17.413 15.096 18.131 ;
     RECT  41.616 16.501 41.64 18.181 ;
     RECT  49.344 17.605 52.488 18.181 ;
     RECT  63.456 14.197 63.48 18.181 ;
     RECT  95.904 17.363 96.024 18.181 ;
     RECT  66.624 16.595 67.512 18.275 ;
     RECT  32.208 17.605 32.232 18.373 ;
     RECT  4.56 17.461 4.824 18.419 ;
     RECT  32.208 18.373 32.376 18.419 ;
     RECT  78 16.019 79.272 18.563 ;
     RECT  78 18.563 78.552 18.565 ;
     RECT  88.8 17.411 89.112 18.565 ;
     RECT  42.768 17.845 43.752 18.659 ;
     RECT  49.248 18.181 52.488 18.659 ;
     RECT  82.896 17.315 83.712 18.707 ;
     RECT  4.8 18.419 4.824 18.709 ;
     RECT  17.136 16.019 17.592 18.757 ;
     RECT  18.6 13.955 18.912 18.757 ;
     RECT  45.6 15.395 45.912 18.757 ;
     RECT  70.272 16.885 70.536 18.757 ;
     RECT  88.704 18.565 89.112 18.757 ;
     RECT  90.144 17.411 90.168 18.757 ;
     RECT  94.2 16.595 94.512 18.757 ;
     RECT  34.704 18.037 35.928 18.803 ;
     RECT  17.136 18.757 18.912 18.851 ;
     RECT  41.616 18.181 41.736 18.851 ;
     RECT  49.248 18.659 51.816 18.851 ;
     RECT  95.904 18.181 96.168 18.851 ;
     RECT  49.248 18.851 49.464 18.947 ;
     RECT  85.248 15.875 85.272 18.995 ;
     RECT  4.8 18.709 5.112 19.091 ;
     RECT  63.12 18.181 63.48 19.091 ;
     RECT  34.8 18.803 35.928 19.139 ;
     RECT  88.704 18.757 91.08 19.139 ;
     RECT  11.376 17.699 12.12 19.235 ;
     RECT  98.64 17.699 99.912 19.235 ;
     RECT  102.288 16.211 102.312 19.237 ;
     RECT  102.288 19.237 102.648 19.331 ;
     RECT  15.024 18.131 15.096 19.333 ;
     RECT  56.112 17.843 56.712 19.333 ;
     RECT  68.976 19.237 69 19.333 ;
     RECT  96.048 18.851 96.168 19.333 ;
     RECT  68.976 19.333 69.048 19.381 ;
     RECT  4.8 19.091 4.824 19.427 ;
     RECT  22.224 17.461 22.776 19.427 ;
     RECT  41.712 18.851 41.736 19.621 ;
     RECT  42.768 18.659 43.368 19.621 ;
     RECT  88.704 19.139 90.168 19.667 ;
     RECT  77.232 18.565 78.552 19.669 ;
     RECT  58.128 17.941 58.152 19.765 ;
     RECT  28.176 16.501 28.392 19.813 ;
     RECT  49.44 18.947 49.464 19.813 ;
     RECT  83.4 18.707 83.712 19.813 ;
     RECT  41.712 19.621 43.368 19.907 ;
     RECT  58.128 19.765 58.584 19.907 ;
     RECT  68.928 19.381 69.048 19.907 ;
     RECT  32.352 18.419 32.376 19.909 ;
     RECT  20.112 18.037 20.136 20.003 ;
     RECT  41.712 19.907 42.168 20.003 ;
     RECT  24 17.699 24.312 20.053 ;
     RECT  29.4 17.605 30.648 20.053 ;
     RECT  14.928 19.333 15.096 20.101 ;
     RECT  53.472 19.333 53.496 20.101 ;
     RECT  13.2 17.699 13.512 20.149 ;
     RECT  17.424 18.851 18.912 20.149 ;
     RECT  27.504 19.813 28.392 20.149 ;
     RECT  29.4 20.053 31.032 20.149 ;
     RECT  99.6 19.235 99.912 20.149 ;
     RECT  83.4 19.813 84.36 20.197 ;
     RECT  27.504 20.149 31.032 20.293 ;
     RECT  43.344 19.907 43.368 20.293 ;
     RECT  88.8 19.667 90.168 20.293 ;
     RECT  43.344 20.293 43.896 20.339 ;
     RECT  53.472 20.101 53.928 20.339 ;
     RECT  77.184 19.669 79.224 20.339 ;
     RECT  22.752 19.427 22.776 20.387 ;
     RECT  99.6 20.149 100.296 20.387 ;
     RECT  75.312 17.029 75.336 20.389 ;
     RECT  14.688 20.101 15.096 20.435 ;
     RECT  53.472 20.339 53.832 20.435 ;
     RECT  27.504 20.293 31.368 20.437 ;
     RECT  32.352 19.909 32.472 20.437 ;
     RECT  66.96 18.275 67.512 20.437 ;
     RECT  70.272 18.757 71.064 20.485 ;
     RECT  72.6 17.267 72.912 20.485 ;
     RECT  74.016 19.765 74.04 20.485 ;
     RECT  103.68 19.909 103.704 20.531 ;
     RECT  27.504 20.437 32.472 20.579 ;
     RECT  70.272 20.485 71.496 20.579 ;
     RECT  72.6 20.485 74.04 20.581 ;
     RECT  75.312 20.389 76.2 20.581 ;
     RECT  27.504 20.579 31.512 20.627 ;
     RECT  70.272 20.579 70.296 20.627 ;
     RECT  72.6 20.581 76.2 20.675 ;
     RECT  17.088 20.149 18.912 20.819 ;
     RECT  53.472 20.435 53.496 20.819 ;
     RECT  64.992 18.757 65.016 20.819 ;
     RECT  68.928 19.907 69 20.867 ;
     RECT  23.904 20.053 24.312 20.869 ;
     RECT  60.576 18.757 60.6 20.869 ;
     RECT  61.8 14.243 62.112 20.869 ;
     RECT  71.472 20.579 71.496 20.869 ;
     RECT  72.6 20.675 74.472 20.869 ;
     RECT  60.576 20.869 62.112 21.011 ;
     RECT  83.4 20.197 84.984 21.061 ;
     RECT  58.128 19.907 58.152 21.109 ;
     RECT  17.088 20.819 17.448 21.155 ;
     RECT  31.008 20.627 31.512 21.155 ;
     RECT  39.6 17.459 40.512 21.155 ;
     RECT  55.92 19.333 56.712 21.155 ;
     RECT  88.8 20.293 90.408 21.155 ;
     RECT  102.48 19.331 102.648 21.155 ;
     RECT  11.424 19.235 12.12 21.203 ;
     RECT  82.656 21.061 84.984 21.203 ;
     RECT  66.528 20.437 67.512 21.253 ;
     RECT  71.472 20.869 74.472 21.299 ;
     RECT  13.2 20.149 13.608 21.301 ;
     RECT  27.504 20.627 29.712 21.397 ;
     RECT  23.904 20.869 24.408 21.443 ;
     RECT  13.2 21.301 13.656 21.541 ;
     RECT  14.832 20.435 15.096 21.541 ;
     RECT  45.6 18.757 46.44 21.541 ;
     RECT  96.048 19.333 96.312 21.589 ;
     RECT  88.8 21.155 90.072 21.635 ;
     RECT  96 21.589 96.312 21.635 ;
     RECT  43.872 20.339 43.896 21.637 ;
     RECT  68.976 20.867 69 21.637 ;
     RECT  82.656 21.203 84.84 21.637 ;
     RECT  96 21.635 96.072 21.637 ;
     RECT  27.36 21.397 29.712 21.683 ;
     RECT  33.072 20.965 33.288 21.683 ;
     RECT  49.44 19.813 49.56 21.683 ;
     RECT  102.624 21.155 102.648 21.683 ;
     RECT  21.072 21.061 21.096 21.731 ;
     RECT  43.296 21.637 43.896 21.731 ;
     RECT  58.128 21.109 58.68 21.781 ;
     RECT  60.576 21.011 60.6 21.781 ;
     RECT  27.36 21.683 28.392 21.971 ;
     RECT  45.504 21.541 46.44 22.021 ;
     RECT  48.24 21.109 48.264 22.021 ;
     RECT  16.992 21.637 17.016 22.069 ;
     RECT  13.2 21.541 15.096 22.117 ;
     RECT  25.584 21.253 25.608 22.117 ;
     RECT  56.112 21.155 56.712 22.117 ;
     RECT  58.128 21.781 59.304 22.117 ;
     RECT  24 21.443 24.408 22.165 ;
     RECT  25.584 22.117 25.8 22.165 ;
     RECT  31.344 21.155 31.512 22.165 ;
     RECT  34.8 19.139 35.112 22.165 ;
     RECT  36.096 21.637 36.12 22.165 ;
     RECT  42.144 20.003 42.168 22.165 ;
     RECT  43.296 21.731 43.32 22.165 ;
     RECT  93.408 18.757 94.512 22.211 ;
     RECT  49.536 21.683 49.56 22.213 ;
     RECT  66.528 21.253 67.608 22.259 ;
     RECT  75.6 20.675 76.2 22.259 ;
     RECT  49.536 22.213 49.608 22.355 ;
     RECT  66.96 22.259 67.608 22.547 ;
     RECT  39.84 21.155 40.512 22.597 ;
     RECT  42.144 22.165 43.32 22.597 ;
     RECT  82.56 21.637 84.84 22.691 ;
     RECT  18.6 20.819 18.912 22.741 ;
     RECT  24 22.165 25.8 22.741 ;
     RECT  53.136 21.637 53.16 22.741 ;
     RECT  65.088 21.397 65.112 22.741 ;
     RECT  95.76 21.637 96.072 22.741 ;
     RECT  33.072 21.683 33.192 22.787 ;
     RECT  65.088 22.741 65.16 22.789 ;
     RECT  11.712 21.203 12.12 22.835 ;
     RECT  16.512 22.069 17.016 22.835 ;
     RECT  24 22.741 26.184 22.835 ;
     RECT  56.112 22.117 59.304 22.835 ;
     RECT  60.48 21.781 60.6 22.835 ;
     RECT  74.448 21.299 74.472 22.835 ;
     RECT  77.184 20.339 78.552 22.835 ;
     RECT  80.112 22.165 80.136 22.835 ;
     RECT  13.2 22.117 15.432 22.883 ;
     RECT  30.816 22.165 31.512 22.883 ;
     RECT  59.28 22.835 59.304 22.883 ;
     RECT  64.896 22.789 65.16 22.979 ;
     RECT  25.584 22.835 26.184 22.981 ;
     RECT  34.8 22.165 36.12 23.027 ;
     RECT  39.84 22.597 43.32 23.029 ;
     RECT  12.096 22.835 12.12 23.171 ;
     RECT  15.072 22.883 15.432 23.317 ;
     RECT  34.8 23.027 35.88 23.317 ;
     RECT  45.504 22.021 48.264 23.317 ;
     RECT  76.176 22.259 76.2 23.317 ;
     RECT  71.472 21.299 73.464 23.363 ;
     RECT  88.8 21.635 89.832 23.411 ;
     RECT  61.8 21.011 62.112 23.461 ;
     RECT  65.088 22.979 65.16 23.509 ;
     RECT  68.976 21.637 69.096 23.555 ;
     RECT  44.976 23.317 48.264 23.557 ;
     RECT  49.536 22.355 49.56 23.557 ;
     RECT  44.736 23.557 49.56 23.699 ;
     RECT  65.088 23.509 65.592 23.699 ;
     RECT  39.648 23.029 43.32 23.843 ;
     RECT  83.4 22.691 84.84 23.845 ;
     RECT  27.504 21.971 28.392 23.893 ;
     RECT  29.4 21.683 29.712 23.893 ;
     RECT  56.112 22.835 58.152 23.893 ;
     RECT  95.76 22.741 96.312 23.893 ;
     RECT  61.8 23.461 62.232 23.939 ;
     RECT  55.92 23.893 58.152 23.941 ;
     RECT  39.84 23.843 43.32 23.987 ;
     RECT  44.976 23.699 49.56 23.987 ;
     RECT  52.8 22.741 53.16 23.987 ;
     RECT  55.92 23.941 59.016 23.987 ;
     RECT  65.088 23.699 65.112 23.987 ;
     RECT  74.64 23.077 74.664 23.987 ;
     RECT  55.92 23.987 56.712 24.035 ;
     RECT  22.56 22.165 22.584 24.085 ;
     RECT  76.176 23.317 76.872 24.179 ;
     RECT  5.664 20.725 5.688 24.277 ;
     RECT  102.528 22.741 102.552 24.419 ;
     RECT  42.144 23.987 42.792 24.467 ;
     RECT  45.6 23.987 49.56 24.467 ;
     RECT  71.472 23.363 71.496 24.467 ;
     RECT  13.2 22.883 13.848 24.469 ;
     RECT  76.176 24.179 76.2 24.469 ;
     RECT  78 22.835 78.552 24.469 ;
     RECT  30.864 22.883 31.512 24.515 ;
     RECT  82.848 23.845 84.84 24.515 ;
     RECT  34.512 23.317 35.88 24.563 ;
     RECT  53.088 23.987 53.16 24.565 ;
     RECT  18.6 22.741 19.608 24.611 ;
     RECT  53.088 24.565 53.592 24.611 ;
     RECT  33.072 22.787 33.096 24.659 ;
     RECT  34.8 24.563 35.88 24.659 ;
     RECT  58.128 23.987 59.016 24.659 ;
     RECT  42.768 24.467 42.792 24.707 ;
     RECT  22.56 24.085 22.872 24.803 ;
     RECT  48.24 24.467 49.56 24.899 ;
     RECT  22.848 24.803 22.872 25.043 ;
     RECT  75.36 24.469 76.2 25.045 ;
     RECT  77.472 24.469 78.552 25.091 ;
     RECT  15.072 23.317 16.008 25.139 ;
     RECT  21.024 24.325 21.048 25.139 ;
     RECT  53.136 24.611 53.592 25.139 ;
     RECT  95.76 23.893 96.936 25.139 ;
     RECT  74.784 25.045 76.2 25.285 ;
     RECT  83.4 24.515 84.84 25.331 ;
     RECT  67.2 22.547 67.608 25.429 ;
     RECT  68.976 23.555 69 25.429 ;
     RECT  78 25.091 78.552 25.429 ;
     RECT  63.456 19.091 63.48 25.475 ;
     RECT  27.504 23.893 29.712 25.573 ;
     RECT  4.992 24.277 5.688 25.715 ;
     RECT  9.888 23.893 9.912 25.715 ;
     RECT  49.152 24.899 49.56 25.715 ;
     RECT  53.568 25.139 53.592 25.715 ;
     RECT  58.128 24.659 58.152 25.715 ;
     RECT  74.784 25.285 76.968 25.715 ;
     RECT  96.912 25.139 96.936 25.715 ;
     RECT  99.6 20.387 99.912 25.717 ;
     RECT  13.104 24.469 13.848 25.765 ;
     RECT  25.584 22.981 26.232 25.765 ;
     RECT  13.104 25.765 14.136 25.859 ;
     RECT  34.8 24.659 35.448 25.859 ;
     RECT  99.504 25.717 99.912 25.861 ;
     RECT  67.2 25.429 69 25.957 ;
     RECT  34.8 25.859 35.304 26.003 ;
     RECT  18.6 24.611 18.912 26.101 ;
     RECT  99.264 25.861 99.912 26.149 ;
     RECT  11.424 25.621 11.448 26.197 ;
     RECT  72.48 23.363 73.464 26.197 ;
     RECT  82.32 24.661 82.344 26.197 ;
     RECT  83.4 25.331 83.832 26.197 ;
     RECT  4.992 25.715 5.016 26.243 ;
     RECT  11.424 26.197 11.592 26.243 ;
     RECT  15.36 25.139 16.008 26.243 ;
     RECT  27.504 25.573 29.88 26.243 ;
     RECT  60.48 22.835 60.504 26.293 ;
     RECT  61.8 23.939 62.112 26.293 ;
     RECT  82.32 26.197 83.832 26.389 ;
     RECT  84.816 25.331 84.84 26.389 ;
     RECT  95.76 25.139 95.784 26.437 ;
     RECT  99.168 26.149 99.912 26.533 ;
     RECT  45.6 24.467 46.68 26.579 ;
     RECT  15.408 26.243 16.008 26.629 ;
     RECT  98.016 25.381 98.04 26.675 ;
     RECT  99.072 26.533 99.912 26.675 ;
     RECT  72.48 26.197 74.088 26.677 ;
     RECT  103.584 25.669 103.608 26.677 ;
     RECT  7.8 17.891 8.112 26.773 ;
     RECT  34.8 26.003 35.112 26.773 ;
     RECT  48.048 26.629 48.072 26.773 ;
     RECT  60.48 26.293 62.112 26.773 ;
     RECT  42.432 26.293 42.456 26.819 ;
     RECT  48.048 26.773 48.216 26.819 ;
     RECT  49.536 25.715 49.56 26.819 ;
     RECT  37.008 26.773 37.032 26.915 ;
     RECT  60.48 26.773 62.664 26.915 ;
     RECT  49.632 26.869 49.656 26.917 ;
     RECT  51 18.851 51.816 26.917 ;
     RECT  34.512 26.773 35.112 26.965 ;
     RECT  33.792 26.965 35.112 27.059 ;
     RECT  49.632 26.917 51.816 27.059 ;
     RECT  50.016 27.059 51.816 27.107 ;
     RECT  76.176 25.715 76.968 27.203 ;
     RECT  50.16 27.107 51.816 27.205 ;
     RECT  27.504 26.243 29.712 27.253 ;
     RECT  7.8 26.773 8.424 27.301 ;
     RECT  11.568 26.243 11.592 27.301 ;
     RECT  15.408 26.629 16.824 27.301 ;
     RECT  39.84 23.987 40.512 27.301 ;
     RECT  44.544 24.661 44.568 27.301 ;
     RECT  56.112 24.035 56.712 27.301 ;
     RECT  72.48 26.677 74.712 27.301 ;
     RECT  10.608 27.301 11.592 27.347 ;
     RECT  27.504 27.253 29.832 27.395 ;
     RECT  66.528 25.957 69 27.395 ;
     RECT  39.744 27.301 40.512 27.445 ;
     RECT  71.184 27.301 74.712 27.445 ;
     RECT  82.32 26.389 84.84 27.635 ;
     RECT  103.104 26.677 103.608 27.635 ;
     RECT  15.36 27.301 16.824 27.637 ;
     RECT  71.184 27.445 75.048 27.731 ;
     RECT  38.832 27.445 40.512 27.733 ;
     RECT  88.8 23.411 89.112 27.733 ;
     RECT  90.576 27.349 90.6 27.733 ;
     RECT  38.784 27.733 40.512 27.781 ;
     RECT  95.76 26.437 96.408 27.829 ;
     RECT  36.864 27.301 36.888 27.877 ;
     RECT  48.192 26.819 48.216 27.877 ;
     RECT  99.264 26.675 99.912 27.877 ;
     RECT  5.52 27.205 5.544 27.923 ;
     RECT  88.8 27.733 90.6 28.115 ;
     RECT  64.56 26.629 64.584 28.117 ;
     RECT  64.56 28.117 64.968 28.163 ;
     RECT  34.8 27.059 35.112 28.165 ;
     RECT  38.208 27.781 40.512 28.211 ;
     RECT  50.16 27.205 52.104 28.211 ;
     RECT  13.2 25.859 14.136 28.261 ;
     RECT  18.6 26.101 19.032 28.261 ;
     RECT  33.792 27.059 33.816 28.261 ;
     RECT  34.8 28.165 35.304 28.261 ;
     RECT  99.264 27.877 100.488 28.261 ;
     RECT  102.096 26.725 102.12 28.261 ;
     RECT  95.664 27.829 96.408 28.403 ;
     RECT  33.792 28.261 35.304 28.405 ;
     RECT  41.616 28.165 41.64 28.405 ;
     RECT  50.16 28.211 51.312 28.405 ;
     RECT  60.48 26.915 62.112 28.405 ;
     RECT  7.8 27.301 8.664 28.451 ;
     RECT  71.184 27.731 74.328 28.451 ;
     RECT  94.2 22.211 94.512 28.453 ;
     RECT  95.664 28.403 96.36 28.453 ;
     RECT  33.792 28.405 35.352 28.501 ;
     RECT  36.432 27.877 36.888 28.501 ;
     RECT  43.92 27.301 44.568 28.547 ;
     RECT  88.8 28.115 90.312 28.547 ;
     RECT  94.2 28.453 96.36 28.547 ;
     RECT  15.36 27.637 17.064 28.741 ;
     RECT  32.64 26.725 32.664 28.741 ;
     RECT  33.792 28.501 36.888 28.741 ;
     RECT  10.608 27.347 10.632 28.787 ;
     RECT  99.264 28.261 102.12 28.789 ;
     RECT  99.072 28.789 102.12 28.835 ;
     RECT  45.6 26.579 46.44 28.837 ;
     RECT  76.176 27.203 76.2 28.837 ;
     RECT  15.264 28.741 17.064 28.883 ;
     RECT  78 25.429 78.792 28.979 ;
     RECT  20.496 28.885 20.52 29.029 ;
     RECT  64.848 28.163 64.968 29.075 ;
     RECT  15.36 28.883 16.824 29.123 ;
     RECT  32.64 28.741 36.888 29.123 ;
     RECT  66.528 27.395 67.896 29.123 ;
     RECT  71.184 28.451 73.32 29.123 ;
     RECT  94.2 28.547 94.776 29.123 ;
     RECT  102.096 28.835 102.12 29.123 ;
     RECT  18.6 28.261 19.368 29.219 ;
     RECT  34.8 29.123 36.888 29.219 ;
     RECT  90.288 28.547 90.312 29.219 ;
     RECT  103.104 27.635 103.128 29.219 ;
     RECT  13.2 28.261 14.184 29.221 ;
     RECT  12.336 29.221 14.184 29.267 ;
     RECT  22.8 27.301 22.824 29.269 ;
     RECT  5.952 28.741 5.976 29.365 ;
     RECT  41.616 28.405 42.504 29.411 ;
     RECT  49.392 28.405 51.312 29.459 ;
     RECT  45.6 28.837 46.68 29.461 ;
     RECT  7.8 28.451 8.376 29.507 ;
     RECT  38.832 28.211 40.512 29.507 ;
     RECT  76.032 28.837 76.2 29.557 ;
     RECT  22.176 29.269 22.824 29.603 ;
     RECT  76.032 29.557 76.392 29.603 ;
     RECT  10.368 28.789 10.392 29.651 ;
     RECT  31.488 24.515 31.512 29.653 ;
     RECT  78 28.979 78.456 29.653 ;
     RECT  20.496 29.029 20.952 29.699 ;
     RECT  27.504 27.395 29.712 29.699 ;
     RECT  31.488 29.653 31.656 29.699 ;
     RECT  82.32 27.635 82.344 29.701 ;
     RECT  83.4 27.635 84.84 29.701 ;
     RECT  27.504 29.699 28.248 29.747 ;
     RECT  99.072 28.835 100.488 29.747 ;
     RECT  15.36 29.123 16.584 29.843 ;
     RECT  74.304 28.451 74.328 29.843 ;
     RECT  24 22.835 24.312 30.037 ;
     RECT  22.8 29.603 22.824 30.083 ;
     RECT  24 30.037 24.552 30.133 ;
     RECT  25.584 25.765 26.52 30.133 ;
     RECT  86.064 30.037 86.088 30.133 ;
     RECT  5.952 29.365 6.312 30.181 ;
     RECT  7.8 29.507 8.232 30.181 ;
     RECT  31.632 29.699 31.656 30.181 ;
     RECT  32.64 29.123 33.816 30.181 ;
     RECT  34.8 29.219 35.304 30.181 ;
     RECT  39.648 29.507 40.512 30.181 ;
     RECT  41.616 29.411 41.64 30.181 ;
     RECT  49.392 29.459 49.416 30.227 ;
     RECT  96.336 28.547 96.36 30.229 ;
     RECT  52.32 28.357 52.344 30.275 ;
     RECT  58.032 29.701 58.056 30.275 ;
     RECT  60.432 28.405 62.112 30.275 ;
     RECT  64.944 29.075 64.968 30.275 ;
     RECT  67.104 29.123 67.896 30.275 ;
     RECT  82.32 29.701 84.84 30.275 ;
     RECT  96.336 30.229 96.456 30.275 ;
     RECT  99.072 29.747 99.912 30.323 ;
     RECT  72.48 29.123 73.32 30.371 ;
     RECT  76.176 29.603 76.392 30.371 ;
     RECT  96.432 30.275 96.456 30.371 ;
     RECT  44.256 28.547 44.568 30.373 ;
     RECT  80.832 30.277 80.856 30.419 ;
     RECT  24 30.133 26.52 30.421 ;
     RECT  55.488 27.301 56.712 30.421 ;
     RECT  5.952 30.181 8.232 30.467 ;
     RECT  45.6 29.461 46.824 30.563 ;
     RECT  55.488 30.421 57 30.611 ;
     RECT  63.696 28.693 63.72 30.611 ;
     RECT  29.28 29.699 29.712 30.661 ;
     RECT  86.064 30.133 86.424 30.661 ;
     RECT  5.952 30.467 5.976 30.709 ;
     RECT  12.336 29.267 13.512 30.709 ;
     RECT  18.6 29.219 19.032 30.709 ;
     RECT  20.496 29.699 20.52 30.709 ;
     RECT  27.504 29.747 27.96 30.709 ;
     RECT  39.648 30.181 41.64 30.709 ;
     RECT  31.632 30.181 35.304 30.755 ;
     RECT  39.312 30.709 41.688 30.757 ;
     RECT  36.432 29.219 36.888 30.851 ;
     RECT  39.168 30.757 41.688 30.851 ;
     RECT  45.6 30.563 46.632 30.851 ;
     RECT  86.064 30.661 86.616 30.851 ;
     RECT  41.616 30.851 41.688 30.853 ;
     RECT  18.6 30.709 20.52 30.899 ;
     RECT  41.616 30.853 41.976 30.899 ;
     RECT  32.928 30.755 35.304 30.947 ;
     RECT  48.144 27.877 48.216 30.947 ;
     RECT  86.4 30.851 86.616 30.947 ;
     RECT  34.8 30.947 35.304 30.949 ;
     RECT  36.432 30.851 36.504 30.949 ;
     RECT  88.8 28.547 89.112 31.045 ;
     RECT  32.928 30.947 33.816 31.091 ;
     RECT  15.36 29.843 16.296 31.093 ;
     RECT  82.32 30.275 82.344 31.139 ;
     RECT  23.712 30.421 26.52 31.141 ;
     RECT  27.504 30.709 28.056 31.141 ;
     RECT  12.336 30.709 14.232 31.235 ;
     RECT  15.36 31.093 16.536 31.235 ;
     RECT  23.712 31.141 28.056 31.235 ;
     RECT  2.4 2.151 2.712 31.237 ;
     RECT  5.04 30.709 5.976 31.379 ;
     RECT  18.6 30.899 19.416 31.379 ;
     RECT  20.496 30.899 20.52 31.379 ;
     RECT  32.928 31.091 32.952 31.379 ;
     RECT  77.808 29.653 78.456 31.379 ;
     RECT  29.232 30.661 29.712 31.381 ;
     RECT  71.184 29.123 71.208 31.381 ;
     RECT  94.2 29.123 94.512 31.381 ;
     RECT  7.248 30.467 8.232 31.427 ;
     RECT  29.088 31.381 29.712 31.523 ;
     RECT  67.104 30.275 67.608 31.525 ;
     RECT  66.24 31.525 67.608 31.573 ;
     RECT  66.24 31.573 67.656 31.715 ;
     RECT  99.408 30.323 99.912 31.763 ;
     RECT  10.848 31.285 10.872 31.765 ;
     RECT  68.976 27.395 69 31.765 ;
     RECT  88.8 31.045 89.688 31.765 ;
     RECT  76.176 30.371 76.2 31.861 ;
     RECT  29.232 31.523 29.712 31.909 ;
     RECT  88.8 31.765 90.504 31.909 ;
     RECT  10.656 31.765 10.872 31.955 ;
     RECT  15.36 31.235 16.296 31.955 ;
     RECT  24 31.235 28.056 31.955 ;
     RECT  55.488 30.611 56.712 31.955 ;
     RECT  99.456 31.763 99.912 31.955 ;
     RECT  34.8 30.949 36.504 31.957 ;
     RECT  27.504 31.955 28.056 32.195 ;
     RECT  83.4 30.275 83.712 32.197 ;
     RECT  84.816 30.275 84.84 32.197 ;
     RECT  49.536 31.285 49.56 32.293 ;
     RECT  66.24 31.715 67.608 32.339 ;
     RECT  15.984 31.955 16.296 32.435 ;
     RECT  49.536 32.293 49.704 32.435 ;
     RECT  2.4 31.237 3.528 32.483 ;
     RECT  88.704 31.909 90.504 32.483 ;
     RECT  72.48 30.371 72.912 32.485 ;
     RECT  7.8 31.427 8.232 32.531 ;
     RECT  5.952 31.379 5.976 32.579 ;
     RECT  99.504 31.955 99.912 32.579 ;
     RECT  43.92 30.373 44.568 32.627 ;
     RECT  34.416 31.957 36.504 32.725 ;
     RECT  39.168 30.851 40.512 32.917 ;
     RECT  41.664 30.899 41.976 32.917 ;
     RECT  45.6 30.851 46.536 32.917 ;
     RECT  48.144 30.947 48.168 32.917 ;
     RECT  16.224 32.435 16.296 32.963 ;
     RECT  24 31.955 25.8 33.013 ;
     RECT  38.784 32.917 41.976 33.013 ;
     RECT  76.176 31.861 76.968 33.059 ;
     RECT  12.336 31.235 13.512 33.061 ;
     RECT  60.864 30.275 62.112 33.061 ;
     RECT  60.576 33.061 62.112 33.107 ;
     RECT  72.24 32.485 72.912 33.109 ;
     RECT  72.24 33.109 73.08 33.251 ;
     RECT  88.704 32.483 89.112 33.251 ;
     RECT  38.64 33.013 41.976 33.299 ;
     RECT  70.608 31.381 71.208 33.493 ;
     RECT  4.848 31.621 4.872 33.541 ;
     RECT  18.6 31.379 18.912 33.541 ;
     RECT  34.416 32.725 36.696 33.541 ;
     RECT  56.256 31.955 56.712 33.541 ;
     RECT  82.08 31.861 82.104 33.541 ;
     RECT  83.4 32.197 84.84 33.541 ;
     RECT  10.656 31.955 10.68 33.589 ;
     RECT  92.928 25.621 92.952 33.589 ;
     RECT  94.2 31.381 94.92 33.589 ;
     RECT  82.08 33.541 84.84 33.635 ;
     RECT  78 31.379 78.456 33.637 ;
     RECT  92.928 33.589 94.92 33.683 ;
     RECT  72.24 33.251 72.912 34.019 ;
     RECT  44.112 32.627 44.568 34.069 ;
     RECT  67.2 32.339 67.608 34.069 ;
     RECT  23.616 33.013 25.8 34.115 ;
     RECT  33.888 33.541 36.696 34.115 ;
     RECT  90.48 32.483 90.504 34.165 ;
     RECT  29.232 31.909 30.216 34.259 ;
     RECT  55.872 33.541 56.712 34.259 ;
     RECT  102.816 32.437 102.84 34.309 ;
     RECT  21.12 33.589 21.144 34.355 ;
     RECT  33.888 34.115 36.408 34.355 ;
     RECT  70.176 33.493 71.208 34.355 ;
     RECT  102.384 34.309 102.84 34.355 ;
     RECT  88.8 33.251 89.112 34.357 ;
     RECT  90.336 34.165 90.504 34.357 ;
     RECT  54.624 32.437 54.648 34.501 ;
     RECT  54.144 34.501 54.648 34.547 ;
     RECT  60.576 33.107 60.6 34.693 ;
     RECT  61.8 33.107 62.112 34.693 ;
     RECT  4.272 33.541 4.872 34.741 ;
     RECT  7.8 32.531 8.112 34.741 ;
     RECT  52.32 33.013 52.344 34.787 ;
     RECT  77.472 33.637 79.416 34.787 ;
     RECT  102.384 34.355 102.408 34.787 ;
     RECT  93.792 33.683 94.92 34.883 ;
     RECT  38.64 33.299 40.512 34.931 ;
     RECT  41.664 33.299 41.976 34.933 ;
     RECT  88.8 34.357 90.504 35.029 ;
     RECT  10.656 33.589 11.16 35.075 ;
     RECT  50.88 29.459 51.312 35.075 ;
     RECT  59.328 34.405 59.352 35.077 ;
     RECT  60.576 34.693 62.112 35.077 ;
     RECT  86.4 30.947 86.424 35.125 ;
     RECT  86.16 35.125 86.424 35.171 ;
     RECT  66.528 34.069 67.608 35.173 ;
     RECT  72.288 34.019 72.912 35.173 ;
     RECT  43.632 34.069 44.568 35.219 ;
     RECT  12.336 33.061 13.608 35.269 ;
     RECT  16.224 32.963 16.248 35.317 ;
     RECT  70.656 34.355 71.208 35.317 ;
     RECT  72.288 35.173 73.032 35.317 ;
     RECT  4.272 34.741 5.064 35.363 ;
     RECT  7.8 34.741 8.808 35.363 ;
     RECT  43.632 35.219 44.376 35.363 ;
     RECT  59.328 35.077 62.112 35.363 ;
     RECT  34.128 34.355 36.408 35.411 ;
     RECT  78 34.787 79.416 35.411 ;
     RECT  96.624 34.213 96.648 35.411 ;
     RECT  43.632 35.363 43.656 35.461 ;
     RECT  43.344 35.461 43.656 35.507 ;
     RECT  49.536 32.435 49.56 35.507 ;
     RECT  54.144 34.547 54.168 35.509 ;
     RECT  4.848 35.363 5.064 35.557 ;
     RECT  21.456 34.933 21.48 35.603 ;
     RECT  45.6 32.917 48.168 35.605 ;
     RECT  58.32 35.461 58.344 35.605 ;
     RECT  39.264 34.931 40.512 35.653 ;
     RECT  41.568 34.933 41.976 35.653 ;
     RECT  80.448 34.741 80.472 35.653 ;
     RECT  79.728 35.653 80.472 35.699 ;
     RECT  17.712 33.541 18.912 35.747 ;
     RECT  39.264 35.653 41.976 35.795 ;
     RECT  70.656 35.317 73.032 35.797 ;
     RECT  70.656 35.797 73.368 35.843 ;
     RECT  10.656 35.075 10.776 35.845 ;
     RECT  23.616 34.115 24.648 35.845 ;
     RECT  25.776 34.115 25.8 35.845 ;
     RECT  88.8 35.029 90.552 35.891 ;
     RECT  41.568 35.795 41.976 35.939 ;
     RECT  54.144 35.509 54.408 35.939 ;
     RECT  59.328 35.363 60.6 35.939 ;
     RECT  56.256 34.259 56.712 35.941 ;
     RECT  82.464 33.635 84.84 35.941 ;
     RECT  94.08 34.883 94.92 35.987 ;
     RECT  29.232 34.259 29.712 35.989 ;
     RECT  88.8 35.891 90.216 36.035 ;
     RECT  79.728 35.699 80.04 36.131 ;
     RECT  12.336 35.269 14.28 36.133 ;
     RECT  82.464 35.941 84.936 36.227 ;
     RECT  41.664 35.939 41.976 36.373 ;
     RECT  43.344 35.507 43.368 36.373 ;
     RECT  10.56 35.845 10.776 36.421 ;
     RECT  23.616 35.845 25.8 36.421 ;
     RECT  76.176 33.059 76.2 36.469 ;
     RECT  22.8 36.421 25.8 36.515 ;
     RECT  33.024 35.077 33.048 36.515 ;
     RECT  66.528 35.173 67.656 36.515 ;
     RECT  80.016 36.131 80.04 36.515 ;
     RECT  71.184 35.843 73.368 36.563 ;
     RECT  78 35.411 78.648 36.563 ;
     RECT  76.176 36.469 76.968 36.661 ;
     RECT  27.504 32.195 27.96 36.709 ;
     RECT  83.28 36.227 84.936 36.709 ;
     RECT  59.328 35.939 59.352 36.755 ;
     RECT  37.104 35.605 37.224 36.757 ;
     RECT  39.264 35.795 40.512 36.757 ;
     RECT  80.88 36.661 80.904 36.803 ;
     RECT  83.28 36.709 85.032 36.899 ;
     RECT  90.192 36.035 90.216 36.899 ;
     RECT  12.336 36.133 14.904 36.947 ;
     RECT  9.648 36.421 10.776 36.995 ;
     RECT  75.264 36.661 76.968 37.043 ;
     RECT  83.28 36.899 84.936 37.043 ;
     RECT  9.648 36.995 9.672 37.091 ;
     RECT  10.656 36.995 10.776 37.091 ;
     RECT  49.632 35.845 49.656 37.091 ;
     RECT  58.128 35.605 58.344 37.091 ;
     RECT  83.4 37.043 84.936 37.091 ;
     RECT  38.832 36.757 40.512 37.139 ;
     RECT  18.192 35.747 18.912 37.187 ;
     RECT  59.52 37.093 59.544 37.331 ;
     RECT  94.2 35.987 94.92 37.381 ;
     RECT  45.6 35.605 48.456 37.571 ;
     RECT  21.696 35.845 21.72 37.573 ;
     RECT  22.8 36.515 24.648 37.573 ;
     RECT  71.184 36.563 71.208 37.573 ;
     RECT  72.6 36.563 73.368 37.573 ;
     RECT  56.256 35.941 56.808 37.619 ;
     RECT  60.576 35.939 60.6 37.619 ;
     RECT  21.696 37.573 24.648 37.667 ;
     RECT  23.376 37.667 24.648 37.715 ;
     RECT  37.104 36.757 37.32 37.859 ;
     RECT  12.336 36.947 13.512 38.053 ;
     RECT  94.2 37.381 95.16 38.101 ;
     RECT  4.848 35.557 5.496 38.147 ;
     RECT  41.664 36.373 43.368 38.147 ;
     RECT  18.6 37.187 18.912 38.149 ;
     RECT  12.336 38.053 13.608 38.195 ;
     RECT  79.584 37.573 79.608 38.195 ;
     RECT  21.696 37.667 22.248 38.243 ;
     RECT  31.632 30.755 31.656 38.243 ;
     RECT  37.296 37.859 37.32 38.243 ;
     RECT  94.08 38.101 95.16 38.291 ;
     RECT  5.328 38.147 5.496 38.387 ;
     RECT  84.816 37.091 84.936 38.389 ;
     RECT  86.16 35.171 86.184 38.389 ;
     RECT  20.16 37.573 20.184 38.435 ;
     RECT  41.664 38.147 41.688 38.435 ;
     RECT  14.88 36.947 14.904 38.437 ;
     RECT  16.224 35.317 16.584 38.437 ;
     RECT  27.312 36.709 27.96 38.437 ;
     RECT  28.944 35.989 29.712 38.437 ;
     RECT  38.928 37.139 40.512 38.485 ;
     RECT  42.816 38.147 43.368 38.485 ;
     RECT  45.6 37.571 46.872 38.533 ;
     RECT  88.8 36.035 89.112 38.533 ;
     RECT  14.88 38.437 16.584 38.627 ;
     RECT  58.32 37.091 58.344 38.677 ;
     RECT  38.928 38.485 40.968 38.723 ;
     RECT  72.432 37.573 73.368 38.723 ;
     RECT  23.376 37.715 24.504 38.725 ;
     RECT  54.384 35.939 54.408 38.725 ;
     RECT  84.816 38.389 86.184 38.771 ;
     RECT  56.256 37.619 56.712 38.773 ;
     RECT  5.328 38.387 5.352 38.819 ;
     RECT  27.312 38.437 29.712 38.819 ;
     RECT  49.824 38.005 49.848 38.915 ;
     RECT  71.184 37.573 71.448 38.915 ;
     RECT  88.368 38.533 89.112 38.965 ;
     RECT  64.8 35.557 64.824 39.059 ;
     RECT  67.2 36.515 67.656 39.061 ;
     RECT  83.4 37.091 83.712 39.061 ;
     RECT  88.368 38.965 90.072 39.107 ;
     RECT  86.16 38.771 86.184 39.155 ;
     RECT  22.8 38.725 24.504 39.203 ;
     RECT  83.184 39.061 83.712 39.203 ;
     RECT  42.816 38.485 43.8 39.205 ;
     RECT  9.504 38.149 9.528 39.253 ;
     RECT  42.816 39.205 44.424 39.253 ;
     RECT  53.568 38.725 54.408 39.253 ;
     RECT  9.12 39.253 9.528 39.299 ;
     RECT  7.8 35.363 8.112 39.301 ;
     RECT  34.128 35.411 35.592 39.301 ;
     RECT  37.008 38.965 37.032 39.301 ;
     RECT  61.8 35.363 62.112 39.301 ;
     RECT  78 36.563 78.552 39.301 ;
     RECT  83.4 39.203 83.712 39.301 ;
     RECT  84.816 38.771 84.84 39.301 ;
     RECT  58.128 38.677 58.344 39.347 ;
     RECT  53.568 39.253 54.696 39.349 ;
     RECT  71.184 38.915 71.208 39.395 ;
     RECT  16.224 38.627 16.584 39.445 ;
     RECT  17.664 38.149 18.912 39.445 ;
     RECT  91.056 38.149 91.08 39.491 ;
     RECT  25.776 36.515 25.8 39.539 ;
     RECT  53.04 39.349 54.696 39.539 ;
     RECT  72.432 38.723 73.32 39.539 ;
     RECT  16.224 39.445 18.912 39.587 ;
     RECT  33.888 39.301 37.032 39.635 ;
     RECT  94.08 38.291 94.728 39.635 ;
     RECT  94.2 39.635 94.728 39.779 ;
     RECT  13.2 38.195 13.512 39.829 ;
     RECT  14.88 38.627 14.904 39.829 ;
     RECT  10.656 37.091 10.68 39.877 ;
     RECT  27.936 38.819 29.712 39.877 ;
     RECT  9.12 39.299 9.144 39.923 ;
     RECT  36.144 39.635 37.032 39.923 ;
     RECT  63.696 38.677 63.72 39.923 ;
     RECT  6.816 39.301 8.112 39.971 ;
     RECT  42.432 39.253 44.424 39.971 ;
     RECT  53.568 39.539 54.696 40.019 ;
     RECT  88.368 39.107 89.976 40.165 ;
     RECT  10.656 39.877 10.968 40.259 ;
     RECT  68.688 31.765 69 40.259 ;
     RECT  27.936 39.877 30.504 40.261 ;
     RECT  56.064 38.773 56.712 40.261 ;
     RECT  26.88 39.061 26.904 40.307 ;
     RECT  67.104 39.061 67.656 40.309 ;
     RECT  77.472 39.301 78.552 40.405 ;
     RECT  13.2 39.829 14.904 40.451 ;
     RECT  33.888 39.635 35.112 40.451 ;
     RECT  16.56 39.587 18.912 40.499 ;
     RECT  97.2 39.781 97.224 40.499 ;
     RECT  27.936 40.261 31.368 40.547 ;
     RECT  49.872 39.301 49.896 40.547 ;
     RECT  88.368 40.165 90.072 40.547 ;
     RECT  60.672 38.149 60.696 40.549 ;
     RECT  61.8 39.301 62.232 40.549 ;
     RECT  45.6 38.533 47.112 40.595 ;
     RECT  48.48 37.573 48.504 40.597 ;
     RECT  55.584 40.261 56.712 40.645 ;
     RECT  83.4 39.301 84.84 40.645 ;
     RECT  10.944 40.259 10.968 40.691 ;
     RECT  45.6 40.595 46.872 40.691 ;
     RECT  43.776 39.971 44.424 40.741 ;
     RECT  68.688 40.259 68.808 40.835 ;
     RECT  33.12 40.837 33.144 40.933 ;
     RECT  60.672 40.549 62.232 40.933 ;
     RECT  23.04 39.203 24.504 40.979 ;
     RECT  13.2 40.451 13.512 40.981 ;
     RECT  58.32 39.347 58.344 40.981 ;
     RECT  82.464 40.645 84.84 40.981 ;
     RECT  34.704 40.451 35.112 41.075 ;
     RECT  72.48 39.539 73.32 41.075 ;
     RECT  87.168 38.149 87.192 41.075 ;
     RECT  37.632 40.453 37.656 41.123 ;
     RECT  55.584 40.645 56.808 41.171 ;
     RECT  23.04 40.979 24.312 41.221 ;
     RECT  67.056 40.309 67.656 41.221 ;
     RECT  32.928 40.933 33.144 41.267 ;
     RECT  56.4 41.171 56.808 41.269 ;
     RECT  14.88 40.451 14.904 41.317 ;
     RECT  60 40.933 62.232 41.317 ;
     RECT  14.88 41.317 15.288 41.363 ;
     RECT  32.928 41.267 33 41.411 ;
     RECT  36.144 39.923 36.168 41.411 ;
     RECT  67.056 41.221 67.944 41.411 ;
     RECT  21.648 40.261 21.672 41.413 ;
     RECT  22.8 41.221 24.312 41.413 ;
     RECT  16.56 40.499 16.584 41.459 ;
     RECT  60 41.317 62.76 41.459 ;
     RECT  94.2 39.779 94.512 41.509 ;
     RECT  27.936 40.547 29.712 41.557 ;
     RECT  31.344 40.547 31.368 41.651 ;
     RECT  53.568 40.019 54.408 41.651 ;
     RECT  71.232 40.405 71.256 41.651 ;
     RECT  77.472 40.405 78.696 41.651 ;
     RECT  82.032 40.981 84.84 41.651 ;
     RECT  13.104 40.981 13.512 41.699 ;
     RECT  67.056 41.411 67.656 41.701 ;
     RECT  75.264 37.043 76.2 41.795 ;
     RECT  54.384 41.651 54.408 41.941 ;
     RECT  26.976 41.557 29.712 41.989 ;
     RECT  21.648 41.413 24.312 42.131 ;
     RECT  54.384 41.941 55.176 42.131 ;
     RECT  17.616 40.499 18.912 42.179 ;
     RECT  48.336 40.597 48.504 42.179 ;
     RECT  56.4 41.269 57.048 42.181 ;
     RECT  72.6 41.075 73.32 42.181 ;
     RECT  10.848 41.605 10.872 42.227 ;
     RECT  32.976 41.411 33 42.227 ;
     RECT  58.32 40.981 58.392 42.227 ;
     RECT  60 41.459 62.112 42.227 ;
     RECT  82.464 41.651 84.84 42.227 ;
     RECT  43.776 40.741 44.616 42.229 ;
     RECT  45.6 40.691 45.912 42.229 ;
     RECT  48.48 42.179 48.504 42.275 ;
     RECT  49.824 40.645 49.848 42.275 ;
     RECT  13.2 41.699 13.512 42.277 ;
     RECT  22.8 42.131 24.312 42.371 ;
     RECT  58.32 42.227 58.344 42.371 ;
     RECT  83.4 42.227 84.84 42.371 ;
     RECT  60.672 42.227 62.112 42.419 ;
     RECT  56.4 42.181 57.144 42.467 ;
     RECT  38.928 38.723 40.512 42.565 ;
     RECT  26.976 41.989 30.168 42.611 ;
     RECT  80.016 42.325 80.04 42.613 ;
     RECT  101.28 39.637 101.304 42.661 ;
     RECT  101.28 42.661 101.448 42.707 ;
     RECT  38.928 42.565 40.92 42.757 ;
     RECT  66.72 41.701 67.656 42.757 ;
     RECT  26.976 42.611 27.096 42.803 ;
     RECT  64.128 40.981 64.152 42.803 ;
     RECT  61.8 42.419 62.112 42.805 ;
     RECT  72.6 42.181 73.896 42.851 ;
     RECT  72.6 42.851 72.912 42.997 ;
     RECT  75.264 41.795 75.288 42.997 ;
     RECT  66.72 42.757 67.752 43.043 ;
     RECT  61.8 42.805 62.28 43.091 ;
     RECT  37.968 42.757 40.92 43.093 ;
     RECT  37.968 43.093 41.208 43.187 ;
     RECT  71.664 42.997 72.912 43.187 ;
     RECT  28.464 42.611 30.168 43.235 ;
     RECT  13.2 42.277 13.656 43.237 ;
     RECT  15.264 41.363 15.288 43.237 ;
     RECT  34.8 41.075 35.112 43.237 ;
     RECT  36.96 42.133 36.984 43.283 ;
     RECT  43.776 42.229 45.912 43.331 ;
     RECT  21.648 42.131 21.672 43.379 ;
     RECT  101.424 42.707 101.448 43.379 ;
     RECT  56.4 42.467 56.808 43.429 ;
     RECT  23.04 42.371 24.312 43.523 ;
     RECT  42.432 39.971 42.456 43.525 ;
     RECT  78 41.651 78.456 43.573 ;
     RECT  56.4 43.429 57 43.619 ;
     RECT  75.024 42.997 75.288 43.619 ;
     RECT  49.104 42.709 49.128 43.717 ;
     RECT  64.992 43.429 65.016 43.763 ;
     RECT  68.496 43.333 68.52 43.763 ;
     RECT  94.2 41.509 94.632 43.763 ;
     RECT  11.952 42.565 11.976 43.811 ;
     RECT  51 35.075 51.312 43.813 ;
     RECT  78 43.573 78.648 43.813 ;
     RECT  80.016 42.613 80.088 43.813 ;
     RECT  16.992 43.141 17.016 43.861 ;
     RECT  51 43.813 51.912 43.861 ;
     RECT  60.672 42.419 60.696 43.861 ;
     RECT  60.672 43.861 60.792 43.907 ;
     RECT  71.76 43.187 72.912 43.907 ;
     RECT  42.432 43.525 42.792 43.909 ;
     RECT  43.776 43.331 43.8 43.909 ;
     RECT  47.856 43.573 47.88 43.909 ;
     RECT  88.8 40.547 90.072 43.955 ;
     RECT  44.928 43.331 45.912 44.003 ;
     RECT  84.816 42.371 84.84 44.003 ;
     RECT  16.992 43.861 17.208 44.051 ;
     RECT  45.12 44.003 45.912 44.051 ;
     RECT  47.76 43.909 47.88 44.147 ;
     RECT  26.976 42.803 27 44.245 ;
     RECT  32.832 43.285 32.856 44.339 ;
     RECT  78 43.813 80.088 44.339 ;
     RECT  54.384 42.131 54.456 44.341 ;
     RECT  24 43.523 24.312 44.389 ;
     RECT  13.2 43.237 15.288 44.437 ;
     RECT  18.24 42.179 18.912 44.437 ;
     RECT  66.72 43.043 67.512 44.437 ;
     RECT  13.104 44.437 15.288 44.483 ;
     RECT  26.208 44.245 27 44.483 ;
     RECT  58.032 43.285 58.056 44.483 ;
     RECT  103.008 42.709 103.032 44.483 ;
     RECT  50.592 43.861 51.912 44.531 ;
     RECT  38.928 43.187 41.208 44.627 ;
     RECT  49.008 43.717 49.128 44.677 ;
     RECT  72.6 43.907 72.912 44.725 ;
     RECT  78 44.339 79.416 44.725 ;
     RECT  37.584 43.861 37.608 44.773 ;
     RECT  53.04 44.677 53.064 44.819 ;
     RECT  18.24 44.437 19.032 44.963 ;
     RECT  49.008 44.677 49.368 44.963 ;
     RECT  24 44.389 24.744 44.965 ;
     RECT  26.208 44.483 26.232 44.965 ;
     RECT  54.384 44.341 55.272 44.965 ;
     RECT  72.6 44.725 73.032 44.965 ;
     RECT  33.072 44.677 33.096 45.011 ;
     RECT  10.8 43.861 11.448 45.013 ;
     RECT  49.008 44.963 49.128 45.013 ;
     RECT  10.224 45.013 11.448 45.059 ;
     RECT  24 44.965 26.232 45.059 ;
     RECT  50.88 44.531 51.912 45.059 ;
     RECT  91.152 44.581 91.176 45.059 ;
     RECT  101.328 43.813 101.352 45.059 ;
     RECT  36.96 44.773 37.608 45.061 ;
     RECT  72.6 44.965 73.512 45.109 ;
     RECT  36.288 45.061 37.608 45.155 ;
     RECT  95.52 44.341 95.544 45.155 ;
     RECT  18.6 44.963 19.032 45.157 ;
     RECT  69.36 44.389 69.384 45.157 ;
     RECT  13.104 44.483 13.656 45.203 ;
     RECT  47.856 44.147 47.88 45.205 ;
     RECT  92.736 34.501 92.76 45.205 ;
     RECT  17.088 44.051 17.208 45.251 ;
     RECT  54.336 44.965 55.272 45.253 ;
     RECT  56.4 43.619 56.712 45.253 ;
     RECT  60.768 43.907 60.792 45.253 ;
     RECT  72.384 45.109 73.512 45.253 ;
     RECT  47.52 45.205 47.88 45.301 ;
     RECT  60.144 45.253 60.792 45.301 ;
     RECT  99.6 32.579 99.912 45.301 ;
     RECT  69.168 45.157 69.384 45.395 ;
     RECT  61.8 43.091 62.112 45.541 ;
     RECT  65.52 44.437 67.512 45.541 ;
     RECT  10.224 45.059 10.824 45.587 ;
     RECT  22.8 45.013 22.824 45.587 ;
     RECT  97.728 44.917 97.752 45.587 ;
     RECT  88.8 43.955 89.112 45.589 ;
     RECT  42.432 43.909 43.8 45.635 ;
     RECT  48.96 45.013 49.128 45.635 ;
     RECT  34.56 43.237 35.112 45.731 ;
     RECT  42.432 45.635 42.504 45.779 ;
     RECT  21.792 44.437 21.816 45.971 ;
     RECT  38.928 44.627 40.728 45.971 ;
     RECT  47.376 45.301 47.88 46.021 ;
     RECT  81.792 45.205 81.816 46.021 ;
     RECT  83.4 42.371 83.712 46.021 ;
     RECT  36.288 45.155 37.032 46.067 ;
     RECT  24 45.059 24.312 46.069 ;
     RECT  54.336 45.253 56.712 46.069 ;
     RECT  88.8 45.589 89.208 46.069 ;
     RECT  105 2.151 105.312 46.069 ;
     RECT  54.336 46.069 56.808 46.115 ;
     RECT  51 45.059 51.912 46.117 ;
     RECT  75.024 43.619 75.048 46.117 ;
     RECT  81.792 46.021 83.712 46.117 ;
     RECT  52.992 45.781 53.016 46.213 ;
     RECT  69.312 45.395 69.384 46.357 ;
     RECT  81.36 46.117 83.712 46.405 ;
     RECT  74.976 46.117 75.048 46.501 ;
     RECT  80.784 46.405 83.712 46.547 ;
     RECT  104.832 46.069 105.312 46.549 ;
     RECT  84.96 44.965 84.984 46.597 ;
     RECT  38.928 45.971 40.632 46.645 ;
     RECT  50.544 46.117 51.912 46.645 ;
     RECT  52.992 46.213 53.208 46.645 ;
     RECT  77.76 44.725 79.416 46.645 ;
     RECT  80.784 46.547 81.48 46.645 ;
     RECT  88.224 46.069 89.208 46.645 ;
     RECT  20.88 46.501 20.904 46.693 ;
     RECT  55.248 46.115 56.808 46.787 ;
     RECT  71.76 45.253 73.512 46.787 ;
     RECT  74.976 46.501 75.24 46.787 ;
     RECT  77.76 46.645 81.48 46.787 ;
     RECT  13.104 45.203 13.608 46.835 ;
     RECT  50.544 46.645 53.208 46.835 ;
     RECT  55.296 46.787 56.808 46.835 ;
     RECT  77.76 46.787 79.368 46.835 ;
     RECT  96.624 42.805 96.648 46.885 ;
     RECT  18.6 45.157 19.464 46.931 ;
     RECT  56.4 46.835 56.808 46.981 ;
     RECT  25.344 45.059 25.992 47.029 ;
     RECT  82.512 46.547 83.712 47.075 ;
     RECT  80.784 46.787 81.48 47.123 ;
     RECT  17.472 45.637 17.496 47.125 ;
     RECT  18.6 46.931 19.032 47.125 ;
     RECT  28.464 43.235 29.712 47.125 ;
     RECT  56.4 46.981 56.952 47.219 ;
     RECT  42.48 45.779 42.504 47.221 ;
     RECT  23.328 46.069 24.312 47.269 ;
     RECT  25.344 47.029 26.088 47.269 ;
     RECT  58.656 45.781 58.68 47.269 ;
     RECT  59.856 45.301 60.792 47.269 ;
     RECT  88.224 46.645 89.496 47.269 ;
     RECT  90.816 47.125 90.84 47.269 ;
     RECT  96.624 46.885 97.56 47.269 ;
     RECT  80.784 47.123 81.336 47.315 ;
     RECT  88.224 47.269 90.84 47.315 ;
     RECT  99.6 45.301 100.008 47.317 ;
     RECT  17.472 47.125 19.032 47.603 ;
     RECT  13.104 46.835 13.512 47.651 ;
     RECT  38.736 46.645 40.632 47.651 ;
     RECT  75.024 46.787 75.24 47.699 ;
     RECT  45.6 44.051 45.912 47.701 ;
     RECT  82.752 47.075 83.712 47.701 ;
     RECT  55.296 46.835 55.32 47.797 ;
     RECT  18.24 47.603 19.032 47.843 ;
     RECT  65.376 45.541 67.512 47.843 ;
     RECT  96.048 47.269 97.56 47.843 ;
     RECT  43.776 45.635 43.8 47.845 ;
     RECT  61.8 45.541 62.424 47.845 ;
     RECT  63.744 45.541 63.768 47.845 ;
     RECT  86.784 46.933 86.808 47.845 ;
     RECT  52.416 46.835 53.208 47.891 ;
     RECT  58.656 47.269 60.792 47.891 ;
     RECT  47.376 46.021 48.168 47.939 ;
     RECT  50.544 46.835 51.312 47.939 ;
     RECT  60.384 47.891 60.792 47.939 ;
     RECT  77.76 46.835 79.176 47.939 ;
     RECT  20.688 46.693 20.904 48.083 ;
     RECT  15.264 44.483 15.288 48.133 ;
     RECT  72.6 46.787 73.512 48.133 ;
     RECT  68.928 46.357 69.384 48.181 ;
     RECT  66.672 47.843 67.512 48.325 ;
     RECT  68.928 48.181 69.864 48.325 ;
     RECT  82.752 47.701 83.976 48.325 ;
     RECT  84.96 46.597 85.08 48.325 ;
     RECT  23.328 47.269 26.088 48.371 ;
     RECT  52.464 47.891 53.208 48.371 ;
     RECT  71.808 48.133 73.512 48.371 ;
     RECT  82.752 48.325 85.08 48.373 ;
     RECT  86.592 47.845 86.808 48.373 ;
     RECT  22.176 47.173 22.2 48.421 ;
     RECT  23.328 48.371 25.656 48.421 ;
     RECT  66.672 48.325 69.864 48.421 ;
     RECT  82.752 48.373 86.808 48.421 ;
     RECT  54.672 47.797 55.32 48.467 ;
     RECT  81.312 47.315 81.336 48.467 ;
     RECT  43.776 47.845 43.944 48.515 ;
     RECT  58.656 47.891 59.256 48.563 ;
     RECT  54.672 48.467 54.744 48.613 ;
     RECT  99.6 47.317 100.296 48.659 ;
     RECT  102.24 47.269 102.264 48.709 ;
     RECT  66.672 48.421 70.824 48.803 ;
     RECT  82.752 48.421 87.048 48.805 ;
     RECT  91.824 45.205 92.76 48.851 ;
     RECT  82.752 48.805 87.192 48.853 ;
     RECT  96.048 47.843 96.648 48.899 ;
     RECT  38.976 47.651 40.632 48.901 ;
     RECT  45.408 47.701 45.912 48.947 ;
     RECT  15.264 48.133 16.248 48.949 ;
     RECT  34.8 45.731 35.112 48.949 ;
     RECT  36.144 46.357 36.168 48.949 ;
     RECT  22.176 48.421 25.656 48.995 ;
     RECT  82.56 48.853 87.192 48.995 ;
     RECT  15.264 48.949 16.584 49.043 ;
     RECT  20.88 48.083 20.904 49.043 ;
     RECT  23.424 48.995 25.656 49.091 ;
     RECT  67.2 48.803 70.824 49.091 ;
     RECT  23.472 49.091 25.656 49.187 ;
     RECT  83.4 48.995 87.192 49.187 ;
     RECT  60.768 47.939 60.792 49.285 ;
     RECT  61.8 47.845 63.768 49.285 ;
     RECT  75.024 47.699 75.048 49.477 ;
     RECT  76.128 47.845 76.152 49.477 ;
     RECT  52.464 48.371 52.488 49.525 ;
     RECT  99.6 48.659 99.912 49.525 ;
     RECT  71.808 48.371 73.128 49.573 ;
     RECT  100.896 48.949 100.92 49.573 ;
     RECT  101.904 48.709 102.264 49.573 ;
     RECT  23.712 49.187 25.656 49.619 ;
     RECT  43.776 48.515 43.8 49.619 ;
     RECT  67.2 49.091 69.864 49.619 ;
     RECT  71.808 49.573 73.224 49.619 ;
     RECT  100.896 49.573 102.264 49.619 ;
     RECT  34.8 48.949 36.168 49.715 ;
     RECT  48.144 47.939 48.168 49.717 ;
     RECT  77.76 47.939 78.84 49.717 ;
     RECT  96.192 48.899 96.648 49.717 ;
     RECT  47.904 49.717 48.168 49.763 ;
     RECT  100.992 49.619 101.016 49.763 ;
     RECT  102.24 49.619 102.264 49.813 ;
     RECT  33.168 48.085 33.192 49.859 ;
     RECT  96.192 49.717 96.696 49.859 ;
     RECT  34.8 49.715 35.928 49.909 ;
     RECT  102.24 49.813 102.312 50.005 ;
     RECT  102.24 50.005 102.6 50.051 ;
     RECT  54.576 48.613 54.744 50.053 ;
     RECT  92.736 48.851 92.76 50.101 ;
     RECT  92.736 50.101 92.904 50.147 ;
     RECT  42.48 47.221 42.744 50.195 ;
     RECT  83.4 49.187 83.976 50.245 ;
     RECT  60.768 49.285 63.768 50.291 ;
     RECT  38.976 48.901 41.256 50.339 ;
     RECT  77.76 49.717 79.128 50.387 ;
     RECT  88.8 47.315 90.84 50.485 ;
     RECT  88.608 50.485 90.84 50.627 ;
     RECT  92.88 50.147 92.904 50.629 ;
     RECT  94.2 43.763 94.512 50.629 ;
     RECT  98.688 49.525 99.912 50.677 ;
     RECT  104.016 46.549 105.312 50.677 ;
     RECT  56.4 47.219 56.904 50.725 ;
     RECT  25.632 49.619 25.656 50.771 ;
     RECT  88.608 50.627 89.448 50.771 ;
     RECT  102.288 50.051 102.6 50.771 ;
     RECT  96.192 49.859 96.648 50.819 ;
     RECT  84.96 49.187 87.192 50.867 ;
     RECT  92.88 50.629 94.512 50.867 ;
     RECT  15.84 49.043 16.584 50.963 ;
     RECT  63.744 50.291 63.768 50.963 ;
     RECT  60.768 50.291 62.664 50.965 ;
     RECT  52.464 49.525 52.776 51.011 ;
     RECT  83.28 50.245 83.976 51.109 ;
     RECT  10.8 45.587 10.824 51.157 ;
     RECT  67.2 49.619 69.816 51.157 ;
     RECT  85.248 50.867 87.192 51.157 ;
     RECT  51 47.939 51.312 51.205 ;
     RECT  58.656 48.563 58.68 51.205 ;
     RECT  60.192 50.965 62.664 51.205 ;
     RECT  83.232 51.109 83.976 51.205 ;
     RECT  85.248 51.157 87.432 51.251 ;
     RECT  54.144 50.053 54.744 51.301 ;
     RECT  28.464 47.125 29.928 51.347 ;
     RECT  34.464 49.909 35.928 51.347 ;
     RECT  58.656 51.205 62.664 51.347 ;
     RECT  96.288 50.819 96.648 51.347 ;
     RECT  10.512 51.157 10.824 51.443 ;
     RECT  96.624 51.347 96.648 51.443 ;
     RECT  88.608 50.771 89.112 51.491 ;
     RECT  65.376 47.843 65.544 51.493 ;
     RECT  54.144 51.301 54.84 51.587 ;
     RECT  67.2 51.157 70.44 51.637 ;
     RECT  66.576 51.637 70.44 51.683 ;
     RECT  7.8 39.971 8.112 51.781 ;
     RECT  18.24 47.843 18.912 51.781 ;
     RECT  22.176 48.995 22.2 51.781 ;
     RECT  23.712 49.619 24.312 51.781 ;
     RECT  72.6 49.619 73.224 51.781 ;
     RECT  98.016 50.677 99.912 51.827 ;
     RECT  42.72 50.195 42.744 51.877 ;
     RECT  22.176 51.781 24.312 51.923 ;
     RECT  42.288 51.877 42.744 51.923 ;
     RECT  50.736 51.205 51.312 51.923 ;
     RECT  59.232 51.347 62.664 51.923 ;
     RECT  82.608 51.205 83.976 51.923 ;
     RECT  103.728 50.677 105.312 51.923 ;
     RECT  10.512 51.443 10.536 51.971 ;
     RECT  64.752 51.493 65.544 51.971 ;
     RECT  75.024 49.477 76.152 51.971 ;
     RECT  104.016 51.923 105.312 51.971 ;
     RECT  70.416 51.683 70.44 52.213 ;
     RECT  70.416 52.213 70.728 52.259 ;
     RECT  13.2 47.651 13.512 52.261 ;
     RECT  34.8 51.347 35.928 52.403 ;
     RECT  70.656 52.259 70.728 52.405 ;
     RECT  47.904 49.763 47.928 52.499 ;
     RECT  85.248 51.251 85.656 52.499 ;
     RECT  83.136 51.923 83.976 52.547 ;
     RECT  7.8 51.781 8.904 52.693 ;
     RECT  54.576 51.587 54.84 52.741 ;
     RECT  29.4 51.347 29.928 52.835 ;
     RECT  32.256 52.693 32.28 52.835 ;
     RECT  59.232 51.923 59.688 52.885 ;
     RECT  86.688 51.251 87.432 52.885 ;
     RECT  88.8 51.491 89.112 52.885 ;
     RECT  56.4 50.725 57.624 52.933 ;
     RECT  56.4 52.933 57.912 52.979 ;
     RECT  98.976 51.827 99.912 52.981 ;
     RECT  7.8 52.693 9.336 53.027 ;
     RECT  102.288 50.771 102.312 53.029 ;
     RECT  18.192 51.781 18.912 53.075 ;
     RECT  42.288 51.923 42.408 53.075 ;
     RECT  54.144 52.741 54.84 53.075 ;
     RECT  61.584 51.923 62.664 53.075 ;
     RECT  75.024 51.971 75.864 53.075 ;
     RECT  86.688 52.885 89.112 53.077 ;
     RECT  90.816 50.627 90.84 53.123 ;
     RECT  16.56 50.963 16.584 53.221 ;
     RECT  22.752 51.923 22.824 53.221 ;
     RECT  24 51.923 24.312 53.221 ;
     RECT  16.56 53.221 17.016 53.267 ;
     RECT  78 50.387 79.128 53.267 ;
     RECT  86.688 53.077 89.688 53.315 ;
     RECT  18.6 53.075 18.912 53.317 ;
     RECT  72.6 51.781 73.848 53.363 ;
     RECT  75.84 53.075 75.864 53.509 ;
     RECT  101.808 53.029 102.312 53.509 ;
     RECT  42.384 53.075 42.408 53.555 ;
     RECT  44.16 52.981 44.184 53.555 ;
     RECT  86.688 53.315 89.4 53.555 ;
     RECT  72.6 53.363 73.56 53.557 ;
     RECT  54.144 53.075 54.744 53.699 ;
     RECT  70.656 52.405 70.92 53.843 ;
     RECT  64.752 51.971 65.256 54.083 ;
     RECT  59.232 52.885 60.6 54.085 ;
     RECT  61.584 53.075 62.232 54.085 ;
     RECT  78 53.267 78.984 54.085 ;
     RECT  57.888 52.979 57.912 54.131 ;
     RECT  85.248 52.499 85.272 54.133 ;
     RECT  22.752 53.221 24.312 54.179 ;
     RECT  27.888 52.885 27.912 54.179 ;
     RECT  59.232 54.085 62.232 54.179 ;
     RECT  72.48 53.557 73.56 54.179 ;
     RECT  84.96 54.133 85.272 54.179 ;
     RECT  61.536 54.179 62.232 54.227 ;
     RECT  52.464 51.011 52.488 54.371 ;
     RECT  75.84 53.509 76.152 54.371 ;
     RECT  80.352 53.557 80.376 54.371 ;
     RECT  92.928 50.867 94.512 54.371 ;
     RECT  77.808 54.085 78.984 54.469 ;
     RECT  63.456 54.373 63.48 54.517 ;
     RECT  16.992 53.267 17.016 54.563 ;
     RECT  49.68 50.821 49.704 54.611 ;
     RECT  83.232 52.547 83.976 54.613 ;
     RECT  86.688 53.555 89.112 54.613 ;
     RECT  104.256 51.971 105.312 54.659 ;
     RECT  86.688 54.613 89.208 54.661 ;
     RECT  7.8 53.027 8.52 54.755 ;
     RECT  13.008 52.261 13.512 54.755 ;
     RECT  59.232 54.179 59.88 54.755 ;
     RECT  70.704 53.843 70.92 54.851 ;
     RECT  23.04 54.179 24.312 54.853 ;
     RECT  66.576 51.683 69.336 54.947 ;
     RECT  63.456 54.517 64.008 55.139 ;
     RECT  75.84 54.371 75.864 55.139 ;
     RECT  74.736 54.325 74.76 55.141 ;
     RECT  77.136 54.469 78.984 55.189 ;
     RECT  86.688 54.661 90.12 55.189 ;
     RECT  59.232 54.755 59.688 55.235 ;
     RECT  93.504 54.371 94.512 55.235 ;
     RECT  53.616 54.661 53.64 55.331 ;
     RECT  54.624 53.699 54.744 55.331 ;
     RECT  65.232 54.083 65.256 55.331 ;
     RECT  66.576 54.947 68.952 55.331 ;
     RECT  86.688 55.189 90.504 55.331 ;
     RECT  83.088 54.613 83.976 55.379 ;
     RECT  38.976 50.339 40.512 55.427 ;
     RECT  98.496 52.981 99.912 55.475 ;
     RECT  70.896 54.851 70.92 55.477 ;
     RECT  61.536 54.227 62.112 55.523 ;
     RECT  90.096 55.331 90.504 55.523 ;
     RECT  18.6 53.317 19.32 55.525 ;
     RECT  59.232 55.235 59.304 55.571 ;
     RECT  63.456 55.139 63.48 55.571 ;
     RECT  14.784 54.373 14.808 55.667 ;
     RECT  18.48 55.525 19.32 55.907 ;
     RECT  26.112 53.029 26.136 55.907 ;
     RECT  59.28 55.571 59.304 55.907 ;
     RECT  86.688 55.331 89.112 55.907 ;
     RECT  90.144 55.523 90.504 55.907 ;
     RECT  90.144 55.907 90.408 55.955 ;
     RECT  72.48 54.179 73.224 56.003 ;
     RECT  54.72 55.331 54.744 56.051 ;
     RECT  88.224 55.907 89.112 56.099 ;
     RECT  23.04 54.853 24.408 56.243 ;
     RECT  20.544 55.237 20.568 56.387 ;
     RECT  83.4 55.379 83.976 56.437 ;
     RECT  84.96 54.179 85.128 56.437 ;
     RECT  101.808 53.509 102.36 56.437 ;
     RECT  66.576 55.331 68.904 56.483 ;
     RECT  67.104 56.483 68.904 56.723 ;
     RECT  70.896 55.477 71.256 56.723 ;
     RECT  74.544 55.141 74.76 56.725 ;
     RECT  18.48 55.907 18.912 57.059 ;
     RECT  26.208 56.389 26.232 57.059 ;
     RECT  67.104 56.723 67.512 57.059 ;
     RECT  74.544 56.725 75.672 57.059 ;
     RECT  77.136 55.189 80.184 57.059 ;
     RECT  83.4 56.437 85.128 57.059 ;
     RECT  86.688 55.907 87 57.059 ;
     RECT  23.04 56.243 24.312 57.203 ;
     RECT  29.4 52.835 29.712 57.253 ;
     RECT  74.736 57.059 75.672 57.299 ;
     RECT  101.808 56.437 102.648 57.347 ;
     RECT  29.4 57.253 30.36 57.443 ;
     RECT  90.144 55.955 90.168 57.443 ;
     RECT  72.48 56.003 72.912 57.493 ;
     RECT  102.336 57.347 102.648 57.539 ;
     RECT  94.2 55.235 94.512 57.589 ;
     RECT  72.384 57.493 72.912 57.635 ;
     RECT  74.736 57.299 74.76 57.635 ;
     RECT  98.496 55.475 98.52 57.635 ;
     RECT  69.264 56.965 69.288 57.683 ;
     RECT  70.896 56.723 70.92 57.683 ;
     RECT  77.136 57.059 79.656 57.683 ;
     RECT  88.32 56.099 89.112 57.683 ;
     RECT  93.456 57.589 94.512 57.685 ;
     RECT  77.136 57.683 78.984 57.731 ;
     RECT  77.136 57.731 78.696 57.827 ;
     RECT  77.136 57.827 78.312 58.211 ;
     RECT  83.4 57.059 84.984 58.355 ;
     RECT  102.336 57.539 102.36 58.451 ;
     RECT  84.96 58.355 84.984 58.499 ;
     RECT  92.784 57.685 94.512 58.499 ;
     RECT  96.048 53.509 96.072 58.691 ;
     RECT  91.584 58.645 91.608 59.267 ;
     RECT  92.784 58.499 92.808 59.267 ;
     RECT  2.4 32.483 2.712 62.649 ;
     RECT  7.8 54.755 8.112 62.649 ;
     RECT  13.2 54.755 13.512 62.649 ;
     RECT  18.6 57.059 18.912 62.649 ;
     RECT  24 57.203 24.312 62.649 ;
     RECT  29.4 57.443 29.712 62.649 ;
     RECT  34.8 52.403 35.112 62.649 ;
     RECT  39.312 55.427 40.512 62.649 ;
     RECT  45.6 48.947 45.912 62.649 ;
     RECT  51 51.923 51.312 62.649 ;
     RECT  56.4 52.979 56.712 62.649 ;
     RECT  61.8 55.523 62.112 62.649 ;
     RECT  67.2 57.059 67.512 62.649 ;
     RECT  72.6 57.635 72.912 62.649 ;
     RECT  78 58.211 78.312 62.649 ;
     RECT  83.4 58.355 83.712 62.649 ;
     RECT  88.8 57.683 89.112 62.649 ;
     RECT  94.2 58.499 94.512 62.649 ;
     RECT  99.6 55.475 99.912 62.649 ;
     RECT  105 54.659 105.312 62.649 ;
     RECT  2.4 62.649 2.52 62.663 ;
     RECT  7.8 62.649 7.92 62.663 ;
     RECT  13.2 62.649 13.32 62.663 ;
     RECT  18.6 62.649 18.72 62.663 ;
     RECT  24 62.649 24.12 62.663 ;
     RECT  29.4 62.649 29.52 62.663 ;
     RECT  34.8 62.649 34.92 62.663 ;
     RECT  39.312 62.649 40.32 62.663 ;
     RECT  45.6 62.649 45.72 62.663 ;
     RECT  51 62.649 51.12 62.663 ;
     RECT  56.4 62.649 56.52 62.663 ;
     RECT  61.8 62.649 61.92 62.663 ;
     RECT  67.2 62.649 67.32 62.663 ;
     RECT  72.6 62.649 72.72 62.663 ;
     RECT  78 62.649 78.12 62.663 ;
     RECT  83.4 62.649 83.52 62.663 ;
     RECT  88.8 62.649 88.92 62.663 ;
     RECT  94.2 62.649 94.32 62.663 ;
     RECT  99.6 62.649 99.72 62.663 ;
     RECT  105 62.649 105.12 62.663 ;
     RECT  39.312 62.663 39.336 64.784 ;
  END
END ot_v41_bf_seg_cl
END LIBRARY
